VERSION 5.8 ;
BUSBITCHARS "[]" ;
DIVIDERCHAR "/" ;
UNITS
    DATABASE MICRONS 1000 ;
END UNITS

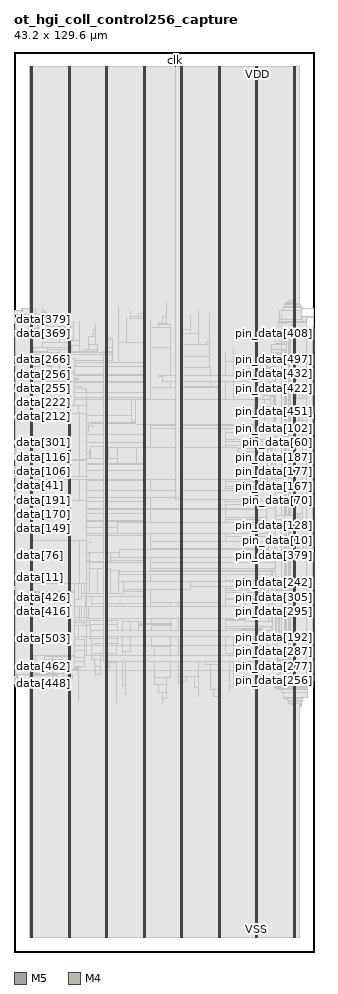
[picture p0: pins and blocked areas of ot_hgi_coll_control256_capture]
MACRO ot_hgi_coll_control256_capture
  FOREIGN ot_hgi_coll_control256_capture 0 0 ;
  CLASS BLOCK ;
  SIZE 43.2 BY 129.6 ;
  PIN clk
    DIRECTION INPUT ;
    USE SIGNAL ;
    PORT
      LAYER M5 ;
        RECT  23.184 129.516 23.208 129.6 ;
    END
    PORT
      LAYER M5 ;
        RECT  23.184 127.463 23.208 129.552 ;
    END
  END clk
  PIN data[0]
    DIRECTION INPUT ;
    USE SIGNAL ;
    PORT
      LAYER M4 ;
        RECT  0 52.848 0.084 52.872 ;
    END
  END data[0]
  PIN data[100]
    DIRECTION INPUT ;
    USE SIGNAL ;
    PORT
      LAYER M4 ;
        RECT  0 68.592 0.084 68.616 ;
    END
  END data[100]
  PIN data[101]
    DIRECTION INPUT ;
    USE SIGNAL ;
    PORT
      LAYER M4 ;
        RECT  0 68.688 0.084 68.712 ;
    END
  END data[101]
  PIN data[102]
    DIRECTION INPUT ;
    USE SIGNAL ;
    PORT
      LAYER M4 ;
        RECT  0 68.784 0.084 68.808 ;
    END
  END data[102]
  PIN data[103]
    DIRECTION INPUT ;
    USE SIGNAL ;
    PORT
      LAYER M4 ;
        RECT  0 68.88 0.084 68.904 ;
    END
  END data[103]
  PIN data[104]
    DIRECTION INPUT ;
    USE SIGNAL ;
    PORT
      LAYER M4 ;
        RECT  0 68.976 0.084 69 ;
    END
  END data[104]
  PIN data[105]
    DIRECTION INPUT ;
    USE SIGNAL ;
    PORT
      LAYER M4 ;
        RECT  0 69.072 0.084 69.096 ;
    END
  END data[105]
  PIN data[106]
    DIRECTION INPUT ;
    USE SIGNAL ;
    PORT
      LAYER M4 ;
        RECT  0 69.168 0.084 69.192 ;
    END
  END data[106]
  PIN data[107]
    DIRECTION INPUT ;
    USE SIGNAL ;
    PORT
      LAYER M4 ;
        RECT  0 69.264 0.084 69.288 ;
    END
  END data[107]
  PIN data[108]
    DIRECTION INPUT ;
    USE SIGNAL ;
    PORT
      LAYER M4 ;
        RECT  0 69.36 0.084 69.384 ;
    END
  END data[108]
  PIN data[109]
    DIRECTION INPUT ;
    USE SIGNAL ;
    PORT
      LAYER M4 ;
        RECT  0 69.456 0.084 69.48 ;
    END
  END data[109]
  PIN data[10]
    DIRECTION INPUT ;
    USE SIGNAL ;
    PORT
      LAYER M4 ;
        RECT  0 53.808 0.084 53.832 ;
    END
  END data[10]
  PIN data[110]
    DIRECTION INPUT ;
    USE SIGNAL ;
    PORT
      LAYER M4 ;
        RECT  0 69.552 0.084 69.576 ;
    END
  END data[110]
  PIN data[111]
    DIRECTION INPUT ;
    USE SIGNAL ;
    PORT
      LAYER M4 ;
        RECT  0 69.648 0.084 69.672 ;
    END
  END data[111]
  PIN data[112]
    DIRECTION INPUT ;
    USE SIGNAL ;
    PORT
      LAYER M4 ;
        RECT  0 69.744 0.084 69.768 ;
    END
  END data[112]
  PIN data[113]
    DIRECTION INPUT ;
    USE SIGNAL ;
    PORT
      LAYER M4 ;
        RECT  0 69.84 0.084 69.864 ;
    END
  END data[113]
  PIN data[114]
    DIRECTION INPUT ;
    USE SIGNAL ;
    PORT
      LAYER M4 ;
        RECT  0 69.936 0.084 69.96 ;
    END
  END data[114]
  PIN data[115]
    DIRECTION INPUT ;
    USE SIGNAL ;
    PORT
      LAYER M4 ;
        RECT  0 70.032 0.084 70.056 ;
    END
  END data[115]
  PIN data[116]
    DIRECTION INPUT ;
    USE SIGNAL ;
    PORT
      LAYER M4 ;
        RECT  0 70.128 0.084 70.152 ;
    END
  END data[116]
  PIN data[117]
    DIRECTION INPUT ;
    USE SIGNAL ;
    PORT
      LAYER M4 ;
        RECT  0 70.224 0.084 70.248 ;
    END
  END data[117]
  PIN data[118]
    DIRECTION INPUT ;
    USE SIGNAL ;
    PORT
      LAYER M4 ;
        RECT  0 70.32 0.084 70.344 ;
    END
  END data[118]
  PIN data[119]
    DIRECTION INPUT ;
    USE SIGNAL ;
    PORT
      LAYER M4 ;
        RECT  0 70.416 0.084 70.44 ;
    END
  END data[119]
  PIN data[11]
    DIRECTION INPUT ;
    USE SIGNAL ;
    PORT
      LAYER M4 ;
        RECT  0 53.904 0.084 53.928 ;
    END
  END data[11]
  PIN data[120]
    DIRECTION INPUT ;
    USE SIGNAL ;
    PORT
      LAYER M4 ;
        RECT  0 70.512 0.084 70.536 ;
    END
  END data[120]
  PIN data[121]
    DIRECTION INPUT ;
    USE SIGNAL ;
    PORT
      LAYER M4 ;
        RECT  0 70.608 0.084 70.632 ;
    END
  END data[121]
  PIN data[122]
    DIRECTION INPUT ;
    USE SIGNAL ;
    PORT
      LAYER M4 ;
        RECT  0 70.704 0.084 70.728 ;
    END
  END data[122]
  PIN data[123]
    DIRECTION INPUT ;
    USE SIGNAL ;
    PORT
      LAYER M4 ;
        RECT  0 70.8 0.084 70.824 ;
    END
  END data[123]
  PIN data[124]
    DIRECTION INPUT ;
    USE SIGNAL ;
    PORT
      LAYER M4 ;
        RECT  0 70.896 0.084 70.92 ;
    END
  END data[124]
  PIN data[125]
    DIRECTION INPUT ;
    USE SIGNAL ;
    PORT
      LAYER M4 ;
        RECT  0 70.992 0.084 71.016 ;
    END
  END data[125]
  PIN data[126]
    DIRECTION INPUT ;
    USE SIGNAL ;
    PORT
      LAYER M4 ;
        RECT  0 71.088 0.084 71.112 ;
    END
  END data[126]
  PIN data[127]
    DIRECTION INPUT ;
    USE SIGNAL ;
    PORT
      LAYER M4 ;
        RECT  0 71.184 0.084 71.208 ;
    END
  END data[127]
  PIN data[128]
    DIRECTION INPUT ;
    USE SIGNAL ;
    PORT
      LAYER M4 ;
        RECT  0 58.992 0.084 59.016 ;
    END
  END data[128]
  PIN data[129]
    DIRECTION INPUT ;
    USE SIGNAL ;
    PORT
      LAYER M4 ;
        RECT  0 59.088 0.084 59.112 ;
    END
  END data[129]
  PIN data[12]
    DIRECTION INPUT ;
    USE SIGNAL ;
    PORT
      LAYER M4 ;
        RECT  0 54 0.084 54.024 ;
    END
  END data[12]
  PIN data[130]
    DIRECTION INPUT ;
    USE SIGNAL ;
    PORT
      LAYER M4 ;
        RECT  0 59.184 0.084 59.208 ;
    END
  END data[130]
  PIN data[131]
    DIRECTION INPUT ;
    USE SIGNAL ;
    PORT
      LAYER M4 ;
        RECT  0 59.28 0.084 59.304 ;
    END
  END data[131]
  PIN data[132]
    DIRECTION INPUT ;
    USE SIGNAL ;
    PORT
      LAYER M4 ;
        RECT  0 59.376 0.084 59.4 ;
    END
  END data[132]
  PIN data[133]
    DIRECTION INPUT ;
    USE SIGNAL ;
    PORT
      LAYER M4 ;
        RECT  0 59.472 0.084 59.496 ;
    END
  END data[133]
  PIN data[134]
    DIRECTION INPUT ;
    USE SIGNAL ;
    PORT
      LAYER M4 ;
        RECT  0 59.568 0.084 59.592 ;
    END
  END data[134]
  PIN data[135]
    DIRECTION INPUT ;
    USE SIGNAL ;
    PORT
      LAYER M4 ;
        RECT  0 59.664 0.084 59.688 ;
    END
  END data[135]
  PIN data[136]
    DIRECTION INPUT ;
    USE SIGNAL ;
    PORT
      LAYER M4 ;
        RECT  0 59.76 0.084 59.784 ;
    END
  END data[136]
  PIN data[137]
    DIRECTION INPUT ;
    USE SIGNAL ;
    PORT
      LAYER M4 ;
        RECT  0 59.856 0.084 59.88 ;
    END
  END data[137]
  PIN data[138]
    DIRECTION INPUT ;
    USE SIGNAL ;
    PORT
      LAYER M4 ;
        RECT  0 59.952 0.084 59.976 ;
    END
  END data[138]
  PIN data[139]
    DIRECTION INPUT ;
    USE SIGNAL ;
    PORT
      LAYER M4 ;
        RECT  0 60.048 0.084 60.072 ;
    END
  END data[139]
  PIN data[13]
    DIRECTION INPUT ;
    USE SIGNAL ;
    PORT
      LAYER M4 ;
        RECT  0 54.096 0.084 54.12 ;
    END
  END data[13]
  PIN data[140]
    DIRECTION INPUT ;
    USE SIGNAL ;
    PORT
      LAYER M4 ;
        RECT  0 60.144 0.084 60.168 ;
    END
  END data[140]
  PIN data[141]
    DIRECTION INPUT ;
    USE SIGNAL ;
    PORT
      LAYER M4 ;
        RECT  0 60.24 0.084 60.264 ;
    END
  END data[141]
  PIN data[142]
    DIRECTION INPUT ;
    USE SIGNAL ;
    PORT
      LAYER M4 ;
        RECT  0 60.336 0.084 60.36 ;
    END
  END data[142]
  PIN data[143]
    DIRECTION INPUT ;
    USE SIGNAL ;
    PORT
      LAYER M4 ;
        RECT  0 60.432 0.084 60.456 ;
    END
  END data[143]
  PIN data[144]
    DIRECTION INPUT ;
    USE SIGNAL ;
    PORT
      LAYER M4 ;
        RECT  0 60.528 0.084 60.552 ;
    END
  END data[144]
  PIN data[145]
    DIRECTION INPUT ;
    USE SIGNAL ;
    PORT
      LAYER M4 ;
        RECT  0 60.624 0.084 60.648 ;
    END
  END data[145]
  PIN data[146]
    DIRECTION INPUT ;
    USE SIGNAL ;
    PORT
      LAYER M4 ;
        RECT  0 60.72 0.084 60.744 ;
    END
  END data[146]
  PIN data[147]
    DIRECTION INPUT ;
    USE SIGNAL ;
    PORT
      LAYER M4 ;
        RECT  0 60.816 0.084 60.84 ;
    END
  END data[147]
  PIN data[148]
    DIRECTION INPUT ;
    USE SIGNAL ;
    PORT
      LAYER M4 ;
        RECT  0 60.912 0.084 60.936 ;
    END
  END data[148]
  PIN data[149]
    DIRECTION INPUT ;
    USE SIGNAL ;
    PORT
      LAYER M4 ;
        RECT  0 61.008 0.084 61.032 ;
    END
  END data[149]
  PIN data[14]
    DIRECTION INPUT ;
    USE SIGNAL ;
    PORT
      LAYER M4 ;
        RECT  0 54.192 0.084 54.216 ;
    END
  END data[14]
  PIN data[150]
    DIRECTION INPUT ;
    USE SIGNAL ;
    PORT
      LAYER M4 ;
        RECT  0 61.104 0.084 61.128 ;
    END
  END data[150]
  PIN data[151]
    DIRECTION INPUT ;
    USE SIGNAL ;
    PORT
      LAYER M4 ;
        RECT  0 61.2 0.084 61.224 ;
    END
  END data[151]
  PIN data[152]
    DIRECTION INPUT ;
    USE SIGNAL ;
    PORT
      LAYER M4 ;
        RECT  0 61.296 0.084 61.32 ;
    END
  END data[152]
  PIN data[153]
    DIRECTION INPUT ;
    USE SIGNAL ;
    PORT
      LAYER M4 ;
        RECT  0 61.392 0.084 61.416 ;
    END
  END data[153]
  PIN data[154]
    DIRECTION INPUT ;
    USE SIGNAL ;
    PORT
      LAYER M4 ;
        RECT  0 61.488 0.084 61.512 ;
    END
  END data[154]
  PIN data[155]
    DIRECTION INPUT ;
    USE SIGNAL ;
    PORT
      LAYER M4 ;
        RECT  0 61.584 0.084 61.608 ;
    END
  END data[155]
  PIN data[156]
    DIRECTION INPUT ;
    USE SIGNAL ;
    PORT
      LAYER M4 ;
        RECT  0 61.68 0.084 61.704 ;
    END
  END data[156]
  PIN data[157]
    DIRECTION INPUT ;
    USE SIGNAL ;
    PORT
      LAYER M4 ;
        RECT  0 61.776 0.084 61.8 ;
    END
  END data[157]
  PIN data[158]
    DIRECTION INPUT ;
    USE SIGNAL ;
    PORT
      LAYER M4 ;
        RECT  0 61.872 0.084 61.896 ;
    END
  END data[158]
  PIN data[159]
    DIRECTION INPUT ;
    USE SIGNAL ;
    PORT
      LAYER M4 ;
        RECT  0 61.968 0.084 61.992 ;
    END
  END data[159]
  PIN data[15]
    DIRECTION INPUT ;
    USE SIGNAL ;
    PORT
      LAYER M4 ;
        RECT  0 54.288 0.084 54.312 ;
    END
  END data[15]
  PIN data[160]
    DIRECTION INPUT ;
    USE SIGNAL ;
    PORT
      LAYER M4 ;
        RECT  0 62.064 0.084 62.088 ;
    END
  END data[160]
  PIN data[161]
    DIRECTION INPUT ;
    USE SIGNAL ;
    PORT
      LAYER M4 ;
        RECT  0 62.16 0.084 62.184 ;
    END
  END data[161]
  PIN data[162]
    DIRECTION INPUT ;
    USE SIGNAL ;
    PORT
      LAYER M4 ;
        RECT  0 62.256 0.084 62.28 ;
    END
  END data[162]
  PIN data[163]
    DIRECTION INPUT ;
    USE SIGNAL ;
    PORT
      LAYER M4 ;
        RECT  0 62.352 0.084 62.376 ;
    END
  END data[163]
  PIN data[164]
    DIRECTION INPUT ;
    USE SIGNAL ;
    PORT
      LAYER M4 ;
        RECT  0 62.448 0.084 62.472 ;
    END
  END data[164]
  PIN data[165]
    DIRECTION INPUT ;
    USE SIGNAL ;
    PORT
      LAYER M4 ;
        RECT  0 62.544 0.084 62.568 ;
    END
  END data[165]
  PIN data[166]
    DIRECTION INPUT ;
    USE SIGNAL ;
    PORT
      LAYER M4 ;
        RECT  0 62.64 0.084 62.664 ;
    END
  END data[166]
  PIN data[167]
    DIRECTION INPUT ;
    USE SIGNAL ;
    PORT
      LAYER M4 ;
        RECT  0 62.736 0.084 62.76 ;
    END
  END data[167]
  PIN data[168]
    DIRECTION INPUT ;
    USE SIGNAL ;
    PORT
      LAYER M4 ;
        RECT  0 62.832 0.084 62.856 ;
    END
  END data[168]
  PIN data[169]
    DIRECTION INPUT ;
    USE SIGNAL ;
    PORT
      LAYER M4 ;
        RECT  0 62.928 0.084 62.952 ;
    END
  END data[169]
  PIN data[16]
    DIRECTION INPUT ;
    USE SIGNAL ;
    PORT
      LAYER M4 ;
        RECT  0 54.384 0.084 54.408 ;
    END
  END data[16]
  PIN data[170]
    DIRECTION INPUT ;
    USE SIGNAL ;
    PORT
      LAYER M4 ;
        RECT  0 63.024 0.084 63.048 ;
    END
  END data[170]
  PIN data[171]
    DIRECTION INPUT ;
    USE SIGNAL ;
    PORT
      LAYER M4 ;
        RECT  0 63.12 0.084 63.144 ;
    END
  END data[171]
  PIN data[172]
    DIRECTION INPUT ;
    USE SIGNAL ;
    PORT
      LAYER M4 ;
        RECT  0 63.216 0.084 63.24 ;
    END
  END data[172]
  PIN data[173]
    DIRECTION INPUT ;
    USE SIGNAL ;
    PORT
      LAYER M4 ;
        RECT  0 63.312 0.084 63.336 ;
    END
  END data[173]
  PIN data[174]
    DIRECTION INPUT ;
    USE SIGNAL ;
    PORT
      LAYER M4 ;
        RECT  0 63.408 0.084 63.432 ;
    END
  END data[174]
  PIN data[175]
    DIRECTION INPUT ;
    USE SIGNAL ;
    PORT
      LAYER M4 ;
        RECT  0 63.504 0.084 63.528 ;
    END
  END data[175]
  PIN data[176]
    DIRECTION INPUT ;
    USE SIGNAL ;
    PORT
      LAYER M4 ;
        RECT  0 63.6 0.084 63.624 ;
    END
  END data[176]
  PIN data[177]
    DIRECTION INPUT ;
    USE SIGNAL ;
    PORT
      LAYER M4 ;
        RECT  0 63.696 0.084 63.72 ;
    END
  END data[177]
  PIN data[178]
    DIRECTION INPUT ;
    USE SIGNAL ;
    PORT
      LAYER M4 ;
        RECT  0 63.792 0.084 63.816 ;
    END
  END data[178]
  PIN data[179]
    DIRECTION INPUT ;
    USE SIGNAL ;
    PORT
      LAYER M4 ;
        RECT  0 63.888 0.084 63.912 ;
    END
  END data[179]
  PIN data[17]
    DIRECTION INPUT ;
    USE SIGNAL ;
    PORT
      LAYER M4 ;
        RECT  0 54.48 0.084 54.504 ;
    END
  END data[17]
  PIN data[180]
    DIRECTION INPUT ;
    USE SIGNAL ;
    PORT
      LAYER M4 ;
        RECT  0 63.984 0.084 64.008 ;
    END
  END data[180]
  PIN data[181]
    DIRECTION INPUT ;
    USE SIGNAL ;
    PORT
      LAYER M4 ;
        RECT  0 64.08 0.084 64.104 ;
    END
  END data[181]
  PIN data[182]
    DIRECTION INPUT ;
    USE SIGNAL ;
    PORT
      LAYER M4 ;
        RECT  0 64.176 0.084 64.2 ;
    END
  END data[182]
  PIN data[183]
    DIRECTION INPUT ;
    USE SIGNAL ;
    PORT
      LAYER M4 ;
        RECT  0 64.272 0.084 64.296 ;
    END
  END data[183]
  PIN data[184]
    DIRECTION INPUT ;
    USE SIGNAL ;
    PORT
      LAYER M4 ;
        RECT  0 64.368 0.084 64.392 ;
    END
  END data[184]
  PIN data[185]
    DIRECTION INPUT ;
    USE SIGNAL ;
    PORT
      LAYER M4 ;
        RECT  0 64.464 0.084 64.488 ;
    END
  END data[185]
  PIN data[186]
    DIRECTION INPUT ;
    USE SIGNAL ;
    PORT
      LAYER M4 ;
        RECT  0 64.56 0.084 64.584 ;
    END
  END data[186]
  PIN data[187]
    DIRECTION INPUT ;
    USE SIGNAL ;
    PORT
      LAYER M4 ;
        RECT  0 64.656 0.084 64.68 ;
    END
  END data[187]
  PIN data[188]
    DIRECTION INPUT ;
    USE SIGNAL ;
    PORT
      LAYER M4 ;
        RECT  0 64.752 0.084 64.776 ;
    END
  END data[188]
  PIN data[189]
    DIRECTION INPUT ;
    USE SIGNAL ;
    PORT
      LAYER M4 ;
        RECT  0 64.848 0.084 64.872 ;
    END
  END data[189]
  PIN data[18]
    DIRECTION INPUT ;
    USE SIGNAL ;
    PORT
      LAYER M4 ;
        RECT  0 54.576 0.084 54.6 ;
    END
  END data[18]
  PIN data[190]
    DIRECTION INPUT ;
    USE SIGNAL ;
    PORT
      LAYER M4 ;
        RECT  0 64.944 0.084 64.968 ;
    END
  END data[190]
  PIN data[191]
    DIRECTION INPUT ;
    USE SIGNAL ;
    PORT
      LAYER M4 ;
        RECT  0 65.04 0.084 65.064 ;
    END
  END data[191]
  PIN data[192]
    DIRECTION INPUT ;
    USE SIGNAL ;
    PORT
      LAYER M4 ;
        RECT  0 75.12 0.084 75.144 ;
    END
  END data[192]
  PIN data[193]
    DIRECTION INPUT ;
    USE SIGNAL ;
    PORT
      LAYER M4 ;
        RECT  0 75.216 0.084 75.24 ;
    END
  END data[193]
  PIN data[194]
    DIRECTION INPUT ;
    USE SIGNAL ;
    PORT
      LAYER M4 ;
        RECT  0 75.312 0.084 75.336 ;
    END
  END data[194]
  PIN data[195]
    DIRECTION INPUT ;
    USE SIGNAL ;
    PORT
      LAYER M4 ;
        RECT  0 75.408 0.084 75.432 ;
    END
  END data[195]
  PIN data[196]
    DIRECTION INPUT ;
    USE SIGNAL ;
    PORT
      LAYER M4 ;
        RECT  0 75.504 0.084 75.528 ;
    END
  END data[196]
  PIN data[197]
    DIRECTION INPUT ;
    USE SIGNAL ;
    PORT
      LAYER M4 ;
        RECT  0 75.6 0.084 75.624 ;
    END
  END data[197]
  PIN data[198]
    DIRECTION INPUT ;
    USE SIGNAL ;
    PORT
      LAYER M4 ;
        RECT  0 75.696 0.084 75.72 ;
    END
  END data[198]
  PIN data[199]
    DIRECTION INPUT ;
    USE SIGNAL ;
    PORT
      LAYER M4 ;
        RECT  0 75.792 0.084 75.816 ;
    END
  END data[199]
  PIN data[19]
    DIRECTION INPUT ;
    USE SIGNAL ;
    PORT
      LAYER M4 ;
        RECT  0 54.672 0.084 54.696 ;
    END
  END data[19]
  PIN data[1]
    DIRECTION INPUT ;
    USE SIGNAL ;
    PORT
      LAYER M4 ;
        RECT  0 52.944 0.084 52.968 ;
    END
  END data[1]
  PIN data[200]
    DIRECTION INPUT ;
    USE SIGNAL ;
    PORT
      LAYER M4 ;
        RECT  0 75.888 0.084 75.912 ;
    END
  END data[200]
  PIN data[201]
    DIRECTION INPUT ;
    USE SIGNAL ;
    PORT
      LAYER M4 ;
        RECT  0 75.984 0.084 76.008 ;
    END
  END data[201]
  PIN data[202]
    DIRECTION INPUT ;
    USE SIGNAL ;
    PORT
      LAYER M4 ;
        RECT  0 76.08 0.084 76.104 ;
    END
  END data[202]
  PIN data[203]
    DIRECTION INPUT ;
    USE SIGNAL ;
    PORT
      LAYER M4 ;
        RECT  0 76.176 0.084 76.2 ;
    END
  END data[203]
  PIN data[204]
    DIRECTION INPUT ;
    USE SIGNAL ;
    PORT
      LAYER M4 ;
        RECT  0 76.272 0.084 76.296 ;
    END
  END data[204]
  PIN data[205]
    DIRECTION INPUT ;
    USE SIGNAL ;
    PORT
      LAYER M4 ;
        RECT  0 76.368 0.084 76.392 ;
    END
  END data[205]
  PIN data[206]
    DIRECTION INPUT ;
    USE SIGNAL ;
    PORT
      LAYER M4 ;
        RECT  0 76.464 0.084 76.488 ;
    END
  END data[206]
  PIN data[207]
    DIRECTION INPUT ;
    USE SIGNAL ;
    PORT
      LAYER M4 ;
        RECT  0 76.56 0.084 76.584 ;
    END
  END data[207]
  PIN data[208]
    DIRECTION INPUT ;
    USE SIGNAL ;
    PORT
      LAYER M4 ;
        RECT  0 76.656 0.084 76.68 ;
    END
  END data[208]
  PIN data[209]
    DIRECTION INPUT ;
    USE SIGNAL ;
    PORT
      LAYER M4 ;
        RECT  0 76.752 0.084 76.776 ;
    END
  END data[209]
  PIN data[20]
    DIRECTION INPUT ;
    USE SIGNAL ;
    PORT
      LAYER M4 ;
        RECT  0 54.768 0.084 54.792 ;
    END
  END data[20]
  PIN data[210]
    DIRECTION INPUT ;
    USE SIGNAL ;
    PORT
      LAYER M4 ;
        RECT  0 76.848 0.084 76.872 ;
    END
  END data[210]
  PIN data[211]
    DIRECTION INPUT ;
    USE SIGNAL ;
    PORT
      LAYER M4 ;
        RECT  0 76.944 0.084 76.968 ;
    END
  END data[211]
  PIN data[212]
    DIRECTION INPUT ;
    USE SIGNAL ;
    PORT
      LAYER M4 ;
        RECT  0 77.04 0.084 77.064 ;
    END
  END data[212]
  PIN data[213]
    DIRECTION INPUT ;
    USE SIGNAL ;
    PORT
      LAYER M4 ;
        RECT  0 77.136 0.084 77.16 ;
    END
  END data[213]
  PIN data[214]
    DIRECTION INPUT ;
    USE SIGNAL ;
    PORT
      LAYER M4 ;
        RECT  0 77.232 0.084 77.256 ;
    END
  END data[214]
  PIN data[215]
    DIRECTION INPUT ;
    USE SIGNAL ;
    PORT
      LAYER M4 ;
        RECT  0 77.328 0.084 77.352 ;
    END
  END data[215]
  PIN data[216]
    DIRECTION INPUT ;
    USE SIGNAL ;
    PORT
      LAYER M4 ;
        RECT  0 77.424 0.084 77.448 ;
    END
  END data[216]
  PIN data[217]
    DIRECTION INPUT ;
    USE SIGNAL ;
    PORT
      LAYER M4 ;
        RECT  0 77.52 0.084 77.544 ;
    END
  END data[217]
  PIN data[218]
    DIRECTION INPUT ;
    USE SIGNAL ;
    PORT
      LAYER M4 ;
        RECT  0 77.616 0.084 77.64 ;
    END
  END data[218]
  PIN data[219]
    DIRECTION INPUT ;
    USE SIGNAL ;
    PORT
      LAYER M4 ;
        RECT  0 77.712 0.084 77.736 ;
    END
  END data[219]
  PIN data[21]
    DIRECTION INPUT ;
    USE SIGNAL ;
    PORT
      LAYER M4 ;
        RECT  0 54.864 0.084 54.888 ;
    END
  END data[21]
  PIN data[220]
    DIRECTION INPUT ;
    USE SIGNAL ;
    PORT
      LAYER M4 ;
        RECT  0 77.808 0.084 77.832 ;
    END
  END data[220]
  PIN data[221]
    DIRECTION INPUT ;
    USE SIGNAL ;
    PORT
      LAYER M4 ;
        RECT  0 77.904 0.084 77.928 ;
    END
  END data[221]
  PIN data[222]
    DIRECTION INPUT ;
    USE SIGNAL ;
    PORT
      LAYER M4 ;
        RECT  0 78 0.084 78.024 ;
    END
  END data[222]
  PIN data[223]
    DIRECTION INPUT ;
    USE SIGNAL ;
    PORT
      LAYER M4 ;
        RECT  0 78.096 0.084 78.12 ;
    END
  END data[223]
  PIN data[224]
    DIRECTION INPUT ;
    USE SIGNAL ;
    PORT
      LAYER M4 ;
        RECT  0 78.192 0.084 78.216 ;
    END
  END data[224]
  PIN data[225]
    DIRECTION INPUT ;
    USE SIGNAL ;
    PORT
      LAYER M4 ;
        RECT  0 78.288 0.084 78.312 ;
    END
  END data[225]
  PIN data[226]
    DIRECTION INPUT ;
    USE SIGNAL ;
    PORT
      LAYER M4 ;
        RECT  0 78.384 0.084 78.408 ;
    END
  END data[226]
  PIN data[227]
    DIRECTION INPUT ;
    USE SIGNAL ;
    PORT
      LAYER M4 ;
        RECT  0 78.48 0.084 78.504 ;
    END
  END data[227]
  PIN data[228]
    DIRECTION INPUT ;
    USE SIGNAL ;
    PORT
      LAYER M4 ;
        RECT  0 78.576 0.084 78.6 ;
    END
  END data[228]
  PIN data[229]
    DIRECTION INPUT ;
    USE SIGNAL ;
    PORT
      LAYER M4 ;
        RECT  0 78.672 0.084 78.696 ;
    END
  END data[229]
  PIN data[22]
    DIRECTION INPUT ;
    USE SIGNAL ;
    PORT
      LAYER M4 ;
        RECT  0 54.96 0.084 54.984 ;
    END
  END data[22]
  PIN data[230]
    DIRECTION INPUT ;
    USE SIGNAL ;
    PORT
      LAYER M4 ;
        RECT  0 78.768 0.084 78.792 ;
    END
  END data[230]
  PIN data[231]
    DIRECTION INPUT ;
    USE SIGNAL ;
    PORT
      LAYER M4 ;
        RECT  0 78.864 0.084 78.888 ;
    END
  END data[231]
  PIN data[232]
    DIRECTION INPUT ;
    USE SIGNAL ;
    PORT
      LAYER M4 ;
        RECT  0 78.96 0.084 78.984 ;
    END
  END data[232]
  PIN data[233]
    DIRECTION INPUT ;
    USE SIGNAL ;
    PORT
      LAYER M4 ;
        RECT  0 79.056 0.084 79.08 ;
    END
  END data[233]
  PIN data[234]
    DIRECTION INPUT ;
    USE SIGNAL ;
    PORT
      LAYER M4 ;
        RECT  0 79.152 0.084 79.176 ;
    END
  END data[234]
  PIN data[235]
    DIRECTION INPUT ;
    USE SIGNAL ;
    PORT
      LAYER M4 ;
        RECT  0 79.248 0.084 79.272 ;
    END
  END data[235]
  PIN data[236]
    DIRECTION INPUT ;
    USE SIGNAL ;
    PORT
      LAYER M4 ;
        RECT  0 79.344 0.084 79.368 ;
    END
  END data[236]
  PIN data[237]
    DIRECTION INPUT ;
    USE SIGNAL ;
    PORT
      LAYER M4 ;
        RECT  0 79.44 0.084 79.464 ;
    END
  END data[237]
  PIN data[238]
    DIRECTION INPUT ;
    USE SIGNAL ;
    PORT
      LAYER M4 ;
        RECT  0 79.536 0.084 79.56 ;
    END
  END data[238]
  PIN data[239]
    DIRECTION INPUT ;
    USE SIGNAL ;
    PORT
      LAYER M4 ;
        RECT  0 79.632 0.084 79.656 ;
    END
  END data[239]
  PIN data[23]
    DIRECTION INPUT ;
    USE SIGNAL ;
    PORT
      LAYER M4 ;
        RECT  0 55.056 0.084 55.08 ;
    END
  END data[23]
  PIN data[240]
    DIRECTION INPUT ;
    USE SIGNAL ;
    PORT
      LAYER M4 ;
        RECT  0 79.728 0.084 79.752 ;
    END
  END data[240]
  PIN data[241]
    DIRECTION INPUT ;
    USE SIGNAL ;
    PORT
      LAYER M4 ;
        RECT  0 79.824 0.084 79.848 ;
    END
  END data[241]
  PIN data[242]
    DIRECTION INPUT ;
    USE SIGNAL ;
    PORT
      LAYER M4 ;
        RECT  0 79.92 0.084 79.944 ;
    END
  END data[242]
  PIN data[243]
    DIRECTION INPUT ;
    USE SIGNAL ;
    PORT
      LAYER M4 ;
        RECT  0 80.016 0.084 80.04 ;
    END
  END data[243]
  PIN data[244]
    DIRECTION INPUT ;
    USE SIGNAL ;
    PORT
      LAYER M4 ;
        RECT  0 80.112 0.084 80.136 ;
    END
  END data[244]
  PIN data[245]
    DIRECTION INPUT ;
    USE SIGNAL ;
    PORT
      LAYER M4 ;
        RECT  0 80.208 0.084 80.232 ;
    END
  END data[245]
  PIN data[246]
    DIRECTION INPUT ;
    USE SIGNAL ;
    PORT
      LAYER M4 ;
        RECT  0 80.304 0.084 80.328 ;
    END
  END data[246]
  PIN data[247]
    DIRECTION INPUT ;
    USE SIGNAL ;
    PORT
      LAYER M4 ;
        RECT  0 80.4 0.084 80.424 ;
    END
  END data[247]
  PIN data[248]
    DIRECTION INPUT ;
    USE SIGNAL ;
    PORT
      LAYER M4 ;
        RECT  0 80.496 0.084 80.52 ;
    END
  END data[248]
  PIN data[249]
    DIRECTION INPUT ;
    USE SIGNAL ;
    PORT
      LAYER M4 ;
        RECT  0 80.592 0.084 80.616 ;
    END
  END data[249]
  PIN data[24]
    DIRECTION INPUT ;
    USE SIGNAL ;
    PORT
      LAYER M4 ;
        RECT  0 55.152 0.084 55.176 ;
    END
  END data[24]
  PIN data[250]
    DIRECTION INPUT ;
    USE SIGNAL ;
    PORT
      LAYER M4 ;
        RECT  0 80.688 0.084 80.712 ;
    END
  END data[250]
  PIN data[251]
    DIRECTION INPUT ;
    USE SIGNAL ;
    PORT
      LAYER M4 ;
        RECT  0 80.784 0.084 80.808 ;
    END
  END data[251]
  PIN data[252]
    DIRECTION INPUT ;
    USE SIGNAL ;
    PORT
      LAYER M4 ;
        RECT  0 80.88 0.084 80.904 ;
    END
  END data[252]
  PIN data[253]
    DIRECTION INPUT ;
    USE SIGNAL ;
    PORT
      LAYER M4 ;
        RECT  0 80.976 0.084 81 ;
    END
  END data[253]
  PIN data[254]
    DIRECTION INPUT ;
    USE SIGNAL ;
    PORT
      LAYER M4 ;
        RECT  0 81.072 0.084 81.096 ;
    END
  END data[254]
  PIN data[255]
    DIRECTION INPUT ;
    USE SIGNAL ;
    PORT
      LAYER M4 ;
        RECT  0 81.168 0.084 81.192 ;
    END
  END data[255]
  PIN data[256]
    DIRECTION INPUT ;
    USE SIGNAL ;
    PORT
      LAYER M4 ;
        RECT  0 84.336 0.084 84.36 ;
    END
  END data[256]
  PIN data[257]
    DIRECTION INPUT ;
    USE SIGNAL ;
    PORT
      LAYER M4 ;
        RECT  0 84.432 0.084 84.456 ;
    END
  END data[257]
  PIN data[258]
    DIRECTION INPUT ;
    USE SIGNAL ;
    PORT
      LAYER M4 ;
        RECT  0 84.528 0.084 84.552 ;
    END
  END data[258]
  PIN data[259]
    DIRECTION INPUT ;
    USE SIGNAL ;
    PORT
      LAYER M4 ;
        RECT  0 84.624 0.084 84.648 ;
    END
  END data[259]
  PIN data[25]
    DIRECTION INPUT ;
    USE SIGNAL ;
    PORT
      LAYER M4 ;
        RECT  0 55.248 0.084 55.272 ;
    END
  END data[25]
  PIN data[260]
    DIRECTION INPUT ;
    USE SIGNAL ;
    PORT
      LAYER M4 ;
        RECT  0 84.72 0.084 84.744 ;
    END
  END data[260]
  PIN data[261]
    DIRECTION INPUT ;
    USE SIGNAL ;
    PORT
      LAYER M4 ;
        RECT  0 84.816 0.084 84.84 ;
    END
  END data[261]
  PIN data[262]
    DIRECTION INPUT ;
    USE SIGNAL ;
    PORT
      LAYER M4 ;
        RECT  0 84.912 0.084 84.936 ;
    END
  END data[262]
  PIN data[263]
    DIRECTION INPUT ;
    USE SIGNAL ;
    PORT
      LAYER M4 ;
        RECT  0 85.008 0.084 85.032 ;
    END
  END data[263]
  PIN data[264]
    DIRECTION INPUT ;
    USE SIGNAL ;
    PORT
      LAYER M4 ;
        RECT  0 85.104 0.084 85.128 ;
    END
  END data[264]
  PIN data[265]
    DIRECTION INPUT ;
    USE SIGNAL ;
    PORT
      LAYER M4 ;
        RECT  0 85.2 0.084 85.224 ;
    END
  END data[265]
  PIN data[266]
    DIRECTION INPUT ;
    USE SIGNAL ;
    PORT
      LAYER M4 ;
        RECT  0 85.296 0.084 85.32 ;
    END
  END data[266]
  PIN data[267]
    DIRECTION INPUT ;
    USE SIGNAL ;
    PORT
      LAYER M4 ;
        RECT  0 85.392 0.084 85.416 ;
    END
  END data[267]
  PIN data[268]
    DIRECTION INPUT ;
    USE SIGNAL ;
    PORT
      LAYER M4 ;
        RECT  0 85.488 0.084 85.512 ;
    END
  END data[268]
  PIN data[269]
    DIRECTION INPUT ;
    USE SIGNAL ;
    PORT
      LAYER M4 ;
        RECT  0 85.584 0.084 85.608 ;
    END
  END data[269]
  PIN data[26]
    DIRECTION INPUT ;
    USE SIGNAL ;
    PORT
      LAYER M4 ;
        RECT  0 55.344 0.084 55.368 ;
    END
  END data[26]
  PIN data[270]
    DIRECTION INPUT ;
    USE SIGNAL ;
    PORT
      LAYER M4 ;
        RECT  0 85.68 0.084 85.704 ;
    END
  END data[270]
  PIN data[271]
    DIRECTION INPUT ;
    USE SIGNAL ;
    PORT
      LAYER M4 ;
        RECT  0 85.776 0.084 85.8 ;
    END
  END data[271]
  PIN data[272]
    DIRECTION INPUT ;
    USE SIGNAL ;
    PORT
      LAYER M4 ;
        RECT  0 85.872 0.084 85.896 ;
    END
  END data[272]
  PIN data[273]
    DIRECTION INPUT ;
    USE SIGNAL ;
    PORT
      LAYER M4 ;
        RECT  0 85.968 0.084 85.992 ;
    END
  END data[273]
  PIN data[274]
    DIRECTION INPUT ;
    USE SIGNAL ;
    PORT
      LAYER M4 ;
        RECT  0 86.064 0.084 86.088 ;
    END
  END data[274]
  PIN data[275]
    DIRECTION INPUT ;
    USE SIGNAL ;
    PORT
      LAYER M4 ;
        RECT  0 86.16 0.084 86.184 ;
    END
  END data[275]
  PIN data[276]
    DIRECTION INPUT ;
    USE SIGNAL ;
    PORT
      LAYER M4 ;
        RECT  0 86.256 0.084 86.28 ;
    END
  END data[276]
  PIN data[277]
    DIRECTION INPUT ;
    USE SIGNAL ;
    PORT
      LAYER M4 ;
        RECT  0 86.352 0.084 86.376 ;
    END
  END data[277]
  PIN data[278]
    DIRECTION INPUT ;
    USE SIGNAL ;
    PORT
      LAYER M4 ;
        RECT  0 86.448 0.084 86.472 ;
    END
  END data[278]
  PIN data[279]
    DIRECTION INPUT ;
    USE SIGNAL ;
    PORT
      LAYER M4 ;
        RECT  0 86.544 0.084 86.568 ;
    END
  END data[279]
  PIN data[27]
    DIRECTION INPUT ;
    USE SIGNAL ;
    PORT
      LAYER M4 ;
        RECT  0 55.44 0.084 55.464 ;
    END
  END data[27]
  PIN data[280]
    DIRECTION INPUT ;
    USE SIGNAL ;
    PORT
      LAYER M4 ;
        RECT  0 86.64 0.084 86.664 ;
    END
  END data[280]
  PIN data[281]
    DIRECTION INPUT ;
    USE SIGNAL ;
    PORT
      LAYER M4 ;
        RECT  0 86.736 0.084 86.76 ;
    END
  END data[281]
  PIN data[282]
    DIRECTION INPUT ;
    USE SIGNAL ;
    PORT
      LAYER M4 ;
        RECT  0 86.832 0.084 86.856 ;
    END
  END data[282]
  PIN data[283]
    DIRECTION INPUT ;
    USE SIGNAL ;
    PORT
      LAYER M4 ;
        RECT  0 86.928 0.084 86.952 ;
    END
  END data[283]
  PIN data[284]
    DIRECTION INPUT ;
    USE SIGNAL ;
    PORT
      LAYER M4 ;
        RECT  0 87.024 0.084 87.048 ;
    END
  END data[284]
  PIN data[285]
    DIRECTION INPUT ;
    USE SIGNAL ;
    PORT
      LAYER M4 ;
        RECT  0 87.12 0.084 87.144 ;
    END
  END data[285]
  PIN data[286]
    DIRECTION INPUT ;
    USE SIGNAL ;
    PORT
      LAYER M4 ;
        RECT  0 87.216 0.084 87.24 ;
    END
  END data[286]
  PIN data[287]
    DIRECTION INPUT ;
    USE SIGNAL ;
    PORT
      LAYER M4 ;
        RECT  0 87.312 0.084 87.336 ;
    END
  END data[287]
  PIN data[288]
    DIRECTION INPUT ;
    USE SIGNAL ;
    PORT
      LAYER M4 ;
        RECT  0 72.048 0.084 72.072 ;
    END
  END data[288]
  PIN data[289]
    DIRECTION INPUT ;
    USE SIGNAL ;
    PORT
      LAYER M4 ;
        RECT  0 72.144 0.084 72.168 ;
    END
  END data[289]
  PIN data[28]
    DIRECTION INPUT ;
    USE SIGNAL ;
    PORT
      LAYER M4 ;
        RECT  0 55.536 0.084 55.56 ;
    END
  END data[28]
  PIN data[290]
    DIRECTION INPUT ;
    USE SIGNAL ;
    PORT
      LAYER M4 ;
        RECT  0 72.24 0.084 72.264 ;
    END
  END data[290]
  PIN data[291]
    DIRECTION INPUT ;
    USE SIGNAL ;
    PORT
      LAYER M4 ;
        RECT  0 72.336 0.084 72.36 ;
    END
  END data[291]
  PIN data[292]
    DIRECTION INPUT ;
    USE SIGNAL ;
    PORT
      LAYER M4 ;
        RECT  0 72.432 0.084 72.456 ;
    END
  END data[292]
  PIN data[293]
    DIRECTION INPUT ;
    USE SIGNAL ;
    PORT
      LAYER M4 ;
        RECT  0 72.528 0.084 72.552 ;
    END
  END data[293]
  PIN data[294]
    DIRECTION INPUT ;
    USE SIGNAL ;
    PORT
      LAYER M4 ;
        RECT  0 72.624 0.084 72.648 ;
    END
  END data[294]
  PIN data[295]
    DIRECTION INPUT ;
    USE SIGNAL ;
    PORT
      LAYER M4 ;
        RECT  0 72.72 0.084 72.744 ;
    END
  END data[295]
  PIN data[296]
    DIRECTION INPUT ;
    USE SIGNAL ;
    PORT
      LAYER M4 ;
        RECT  0 72.816 0.084 72.84 ;
    END
  END data[296]
  PIN data[297]
    DIRECTION INPUT ;
    USE SIGNAL ;
    PORT
      LAYER M4 ;
        RECT  0 72.912 0.084 72.936 ;
    END
  END data[297]
  PIN data[298]
    DIRECTION INPUT ;
    USE SIGNAL ;
    PORT
      LAYER M4 ;
        RECT  0 73.008 0.084 73.032 ;
    END
  END data[298]
  PIN data[299]
    DIRECTION INPUT ;
    USE SIGNAL ;
    PORT
      LAYER M4 ;
        RECT  0 73.104 0.084 73.128 ;
    END
  END data[299]
  PIN data[29]
    DIRECTION INPUT ;
    USE SIGNAL ;
    PORT
      LAYER M4 ;
        RECT  0 55.632 0.084 55.656 ;
    END
  END data[29]
  PIN data[2]
    DIRECTION INPUT ;
    USE SIGNAL ;
    PORT
      LAYER M4 ;
        RECT  0 53.04 0.084 53.064 ;
    END
  END data[2]
  PIN data[300]
    DIRECTION INPUT ;
    USE SIGNAL ;
    PORT
      LAYER M4 ;
        RECT  0 73.2 0.084 73.224 ;
    END
  END data[300]
  PIN data[301]
    DIRECTION INPUT ;
    USE SIGNAL ;
    PORT
      LAYER M4 ;
        RECT  0 73.296 0.084 73.32 ;
    END
  END data[301]
  PIN data[302]
    DIRECTION INPUT ;
    USE SIGNAL ;
    PORT
      LAYER M4 ;
        RECT  0 73.392 0.084 73.416 ;
    END
  END data[302]
  PIN data[303]
    DIRECTION INPUT ;
    USE SIGNAL ;
    PORT
      LAYER M4 ;
        RECT  0 73.488 0.084 73.512 ;
    END
  END data[303]
  PIN data[304]
    DIRECTION INPUT ;
    USE SIGNAL ;
    PORT
      LAYER M4 ;
        RECT  0 73.584 0.084 73.608 ;
    END
  END data[304]
  PIN data[305]
    DIRECTION INPUT ;
    USE SIGNAL ;
    PORT
      LAYER M4 ;
        RECT  0 73.68 0.084 73.704 ;
    END
  END data[305]
  PIN data[306]
    DIRECTION INPUT ;
    USE SIGNAL ;
    PORT
      LAYER M4 ;
        RECT  0 73.776 0.084 73.8 ;
    END
  END data[306]
  PIN data[307]
    DIRECTION INPUT ;
    USE SIGNAL ;
    PORT
      LAYER M4 ;
        RECT  0 73.872 0.084 73.896 ;
    END
  END data[307]
  PIN data[308]
    DIRECTION INPUT ;
    USE SIGNAL ;
    PORT
      LAYER M4 ;
        RECT  0 73.968 0.084 73.992 ;
    END
  END data[308]
  PIN data[309]
    DIRECTION INPUT ;
    USE SIGNAL ;
    PORT
      LAYER M4 ;
        RECT  0 74.064 0.084 74.088 ;
    END
  END data[309]
  PIN data[30]
    DIRECTION INPUT ;
    USE SIGNAL ;
    PORT
      LAYER M4 ;
        RECT  0 55.728 0.084 55.752 ;
    END
  END data[30]
  PIN data[310]
    DIRECTION INPUT ;
    USE SIGNAL ;
    PORT
      LAYER M4 ;
        RECT  0 74.16 0.084 74.184 ;
    END
  END data[310]
  PIN data[311]
    DIRECTION INPUT ;
    USE SIGNAL ;
    PORT
      LAYER M4 ;
        RECT  0 74.256 0.084 74.28 ;
    END
  END data[311]
  PIN data[312]
    DIRECTION INPUT ;
    USE SIGNAL ;
    PORT
      LAYER M4 ;
        RECT  0 74.352 0.084 74.376 ;
    END
  END data[312]
  PIN data[313]
    DIRECTION INPUT ;
    USE SIGNAL ;
    PORT
      LAYER M4 ;
        RECT  0 74.448 0.084 74.472 ;
    END
  END data[313]
  PIN data[314]
    DIRECTION INPUT ;
    USE SIGNAL ;
    PORT
      LAYER M4 ;
        RECT  0 74.544 0.084 74.568 ;
    END
  END data[314]
  PIN data[315]
    DIRECTION INPUT ;
    USE SIGNAL ;
    PORT
      LAYER M4 ;
        RECT  0 74.64 0.084 74.664 ;
    END
  END data[315]
  PIN data[316]
    DIRECTION INPUT ;
    USE SIGNAL ;
    PORT
      LAYER M4 ;
        RECT  0 74.736 0.084 74.76 ;
    END
  END data[316]
  PIN data[317]
    DIRECTION INPUT ;
    USE SIGNAL ;
    PORT
      LAYER M4 ;
        RECT  0 74.832 0.084 74.856 ;
    END
  END data[317]
  PIN data[318]
    DIRECTION INPUT ;
    USE SIGNAL ;
    PORT
      LAYER M4 ;
        RECT  0 74.928 0.084 74.952 ;
    END
  END data[318]
  PIN data[319]
    DIRECTION INPUT ;
    USE SIGNAL ;
    PORT
      LAYER M4 ;
        RECT  0 75.024 0.084 75.048 ;
    END
  END data[319]
  PIN data[31]
    DIRECTION INPUT ;
    USE SIGNAL ;
    PORT
      LAYER M4 ;
        RECT  0 55.824 0.084 55.848 ;
    END
  END data[31]
  PIN data[320]
    DIRECTION INPUT ;
    USE SIGNAL ;
    PORT
      LAYER M4 ;
        RECT  0 81.264 0.084 81.288 ;
    END
  END data[320]
  PIN data[321]
    DIRECTION INPUT ;
    USE SIGNAL ;
    PORT
      LAYER M4 ;
        RECT  0 81.36 0.084 81.384 ;
    END
  END data[321]
  PIN data[322]
    DIRECTION INPUT ;
    USE SIGNAL ;
    PORT
      LAYER M4 ;
        RECT  0 81.456 0.084 81.48 ;
    END
  END data[322]
  PIN data[323]
    DIRECTION INPUT ;
    USE SIGNAL ;
    PORT
      LAYER M4 ;
        RECT  0 81.552 0.084 81.576 ;
    END
  END data[323]
  PIN data[324]
    DIRECTION INPUT ;
    USE SIGNAL ;
    PORT
      LAYER M4 ;
        RECT  0 81.648 0.084 81.672 ;
    END
  END data[324]
  PIN data[325]
    DIRECTION INPUT ;
    USE SIGNAL ;
    PORT
      LAYER M4 ;
        RECT  0 81.744 0.084 81.768 ;
    END
  END data[325]
  PIN data[326]
    DIRECTION INPUT ;
    USE SIGNAL ;
    PORT
      LAYER M4 ;
        RECT  0 81.84 0.084 81.864 ;
    END
  END data[326]
  PIN data[327]
    DIRECTION INPUT ;
    USE SIGNAL ;
    PORT
      LAYER M4 ;
        RECT  0 81.936 0.084 81.96 ;
    END
  END data[327]
  PIN data[328]
    DIRECTION INPUT ;
    USE SIGNAL ;
    PORT
      LAYER M4 ;
        RECT  0 82.032 0.084 82.056 ;
    END
  END data[328]
  PIN data[329]
    DIRECTION INPUT ;
    USE SIGNAL ;
    PORT
      LAYER M4 ;
        RECT  0 82.128 0.084 82.152 ;
    END
  END data[329]
  PIN data[32]
    DIRECTION INPUT ;
    USE SIGNAL ;
    PORT
      LAYER M4 ;
        RECT  0 65.136 0.084 65.16 ;
    END
  END data[32]
  PIN data[330]
    DIRECTION INPUT ;
    USE SIGNAL ;
    PORT
      LAYER M4 ;
        RECT  0 82.224 0.084 82.248 ;
    END
  END data[330]
  PIN data[331]
    DIRECTION INPUT ;
    USE SIGNAL ;
    PORT
      LAYER M4 ;
        RECT  0 82.32 0.084 82.344 ;
    END
  END data[331]
  PIN data[332]
    DIRECTION INPUT ;
    USE SIGNAL ;
    PORT
      LAYER M4 ;
        RECT  0 82.416 0.084 82.44 ;
    END
  END data[332]
  PIN data[333]
    DIRECTION INPUT ;
    USE SIGNAL ;
    PORT
      LAYER M4 ;
        RECT  0 82.512 0.084 82.536 ;
    END
  END data[333]
  PIN data[334]
    DIRECTION INPUT ;
    USE SIGNAL ;
    PORT
      LAYER M4 ;
        RECT  0 82.608 0.084 82.632 ;
    END
  END data[334]
  PIN data[335]
    DIRECTION INPUT ;
    USE SIGNAL ;
    PORT
      LAYER M4 ;
        RECT  0 82.704 0.084 82.728 ;
    END
  END data[335]
  PIN data[336]
    DIRECTION INPUT ;
    USE SIGNAL ;
    PORT
      LAYER M4 ;
        RECT  0 82.8 0.084 82.824 ;
    END
  END data[336]
  PIN data[337]
    DIRECTION INPUT ;
    USE SIGNAL ;
    PORT
      LAYER M4 ;
        RECT  0 82.896 0.084 82.92 ;
    END
  END data[337]
  PIN data[338]
    DIRECTION INPUT ;
    USE SIGNAL ;
    PORT
      LAYER M4 ;
        RECT  0 82.992 0.084 83.016 ;
    END
  END data[338]
  PIN data[339]
    DIRECTION INPUT ;
    USE SIGNAL ;
    PORT
      LAYER M4 ;
        RECT  0 83.088 0.084 83.112 ;
    END
  END data[339]
  PIN data[33]
    DIRECTION INPUT ;
    USE SIGNAL ;
    PORT
      LAYER M4 ;
        RECT  0 65.232 0.084 65.256 ;
    END
  END data[33]
  PIN data[340]
    DIRECTION INPUT ;
    USE SIGNAL ;
    PORT
      LAYER M4 ;
        RECT  0 83.184 0.084 83.208 ;
    END
  END data[340]
  PIN data[341]
    DIRECTION INPUT ;
    USE SIGNAL ;
    PORT
      LAYER M4 ;
        RECT  0 83.28 0.084 83.304 ;
    END
  END data[341]
  PIN data[342]
    DIRECTION INPUT ;
    USE SIGNAL ;
    PORT
      LAYER M4 ;
        RECT  0 83.376 0.084 83.4 ;
    END
  END data[342]
  PIN data[343]
    DIRECTION INPUT ;
    USE SIGNAL ;
    PORT
      LAYER M4 ;
        RECT  0 83.472 0.084 83.496 ;
    END
  END data[343]
  PIN data[344]
    DIRECTION INPUT ;
    USE SIGNAL ;
    PORT
      LAYER M4 ;
        RECT  0 83.568 0.084 83.592 ;
    END
  END data[344]
  PIN data[345]
    DIRECTION INPUT ;
    USE SIGNAL ;
    PORT
      LAYER M4 ;
        RECT  0 83.664 0.084 83.688 ;
    END
  END data[345]
  PIN data[346]
    DIRECTION INPUT ;
    USE SIGNAL ;
    PORT
      LAYER M4 ;
        RECT  0 83.76 0.084 83.784 ;
    END
  END data[346]
  PIN data[347]
    DIRECTION INPUT ;
    USE SIGNAL ;
    PORT
      LAYER M4 ;
        RECT  0 83.856 0.084 83.88 ;
    END
  END data[347]
  PIN data[348]
    DIRECTION INPUT ;
    USE SIGNAL ;
    PORT
      LAYER M4 ;
        RECT  0 83.952 0.084 83.976 ;
    END
  END data[348]
  PIN data[349]
    DIRECTION INPUT ;
    USE SIGNAL ;
    PORT
      LAYER M4 ;
        RECT  0 84.048 0.084 84.072 ;
    END
  END data[349]
  PIN data[34]
    DIRECTION INPUT ;
    USE SIGNAL ;
    PORT
      LAYER M4 ;
        RECT  0 65.328 0.084 65.352 ;
    END
  END data[34]
  PIN data[350]
    DIRECTION INPUT ;
    USE SIGNAL ;
    PORT
      LAYER M4 ;
        RECT  0 84.144 0.084 84.168 ;
    END
  END data[350]
  PIN data[351]
    DIRECTION INPUT ;
    USE SIGNAL ;
    PORT
      LAYER M4 ;
        RECT  0 84.24 0.084 84.264 ;
    END
  END data[351]
  PIN data[352]
    DIRECTION INPUT ;
    USE SIGNAL ;
    PORT
      LAYER M4 ;
        RECT  0 87.408 0.084 87.432 ;
    END
  END data[352]
  PIN data[353]
    DIRECTION INPUT ;
    USE SIGNAL ;
    PORT
      LAYER M4 ;
        RECT  0 87.504 0.084 87.528 ;
    END
  END data[353]
  PIN data[354]
    DIRECTION INPUT ;
    USE SIGNAL ;
    PORT
      LAYER M4 ;
        RECT  0 87.6 0.084 87.624 ;
    END
  END data[354]
  PIN data[355]
    DIRECTION INPUT ;
    USE SIGNAL ;
    PORT
      LAYER M4 ;
        RECT  0 87.696 0.084 87.72 ;
    END
  END data[355]
  PIN data[356]
    DIRECTION INPUT ;
    USE SIGNAL ;
    PORT
      LAYER M4 ;
        RECT  0 87.792 0.084 87.816 ;
    END
  END data[356]
  PIN data[357]
    DIRECTION INPUT ;
    USE SIGNAL ;
    PORT
      LAYER M4 ;
        RECT  0 87.888 0.084 87.912 ;
    END
  END data[357]
  PIN data[358]
    DIRECTION INPUT ;
    USE SIGNAL ;
    PORT
      LAYER M4 ;
        RECT  0 87.984 0.084 88.008 ;
    END
  END data[358]
  PIN data[359]
    DIRECTION INPUT ;
    USE SIGNAL ;
    PORT
      LAYER M4 ;
        RECT  0 88.08 0.084 88.104 ;
    END
  END data[359]
  PIN data[35]
    DIRECTION INPUT ;
    USE SIGNAL ;
    PORT
      LAYER M4 ;
        RECT  0 65.424 0.084 65.448 ;
    END
  END data[35]
  PIN data[360]
    DIRECTION INPUT ;
    USE SIGNAL ;
    PORT
      LAYER M4 ;
        RECT  0 88.176 0.084 88.2 ;
    END
  END data[360]
  PIN data[361]
    DIRECTION INPUT ;
    USE SIGNAL ;
    PORT
      LAYER M4 ;
        RECT  0 88.272 0.084 88.296 ;
    END
  END data[361]
  PIN data[362]
    DIRECTION INPUT ;
    USE SIGNAL ;
    PORT
      LAYER M4 ;
        RECT  0 88.368 0.084 88.392 ;
    END
  END data[362]
  PIN data[363]
    DIRECTION INPUT ;
    USE SIGNAL ;
    PORT
      LAYER M4 ;
        RECT  0 88.464 0.084 88.488 ;
    END
  END data[363]
  PIN data[364]
    DIRECTION INPUT ;
    USE SIGNAL ;
    PORT
      LAYER M4 ;
        RECT  0 88.56 0.084 88.584 ;
    END
  END data[364]
  PIN data[365]
    DIRECTION INPUT ;
    USE SIGNAL ;
    PORT
      LAYER M4 ;
        RECT  0 88.656 0.084 88.68 ;
    END
  END data[365]
  PIN data[366]
    DIRECTION INPUT ;
    USE SIGNAL ;
    PORT
      LAYER M4 ;
        RECT  0 88.752 0.084 88.776 ;
    END
  END data[366]
  PIN data[367]
    DIRECTION INPUT ;
    USE SIGNAL ;
    PORT
      LAYER M4 ;
        RECT  0 88.848 0.084 88.872 ;
    END
  END data[367]
  PIN data[368]
    DIRECTION INPUT ;
    USE SIGNAL ;
    PORT
      LAYER M4 ;
        RECT  0 88.944 0.084 88.968 ;
    END
  END data[368]
  PIN data[369]
    DIRECTION INPUT ;
    USE SIGNAL ;
    PORT
      LAYER M4 ;
        RECT  0 89.04 0.084 89.064 ;
    END
  END data[369]
  PIN data[36]
    DIRECTION INPUT ;
    USE SIGNAL ;
    PORT
      LAYER M4 ;
        RECT  0 65.52 0.084 65.544 ;
    END
  END data[36]
  PIN data[370]
    DIRECTION INPUT ;
    USE SIGNAL ;
    PORT
      LAYER M4 ;
        RECT  0 89.136 0.084 89.16 ;
    END
  END data[370]
  PIN data[371]
    DIRECTION INPUT ;
    USE SIGNAL ;
    PORT
      LAYER M4 ;
        RECT  0 89.232 0.084 89.256 ;
    END
  END data[371]
  PIN data[372]
    DIRECTION INPUT ;
    USE SIGNAL ;
    PORT
      LAYER M4 ;
        RECT  0 89.328 0.084 89.352 ;
    END
  END data[372]
  PIN data[373]
    DIRECTION INPUT ;
    USE SIGNAL ;
    PORT
      LAYER M4 ;
        RECT  0 89.424 0.084 89.448 ;
    END
  END data[373]
  PIN data[374]
    DIRECTION INPUT ;
    USE SIGNAL ;
    PORT
      LAYER M4 ;
        RECT  0 89.52 0.084 89.544 ;
    END
  END data[374]
  PIN data[375]
    DIRECTION INPUT ;
    USE SIGNAL ;
    PORT
      LAYER M4 ;
        RECT  0 89.616 0.084 89.64 ;
    END
  END data[375]
  PIN data[376]
    DIRECTION INPUT ;
    USE SIGNAL ;
    PORT
      LAYER M4 ;
        RECT  0 89.712 0.084 89.736 ;
    END
  END data[376]
  PIN data[377]
    DIRECTION INPUT ;
    USE SIGNAL ;
    PORT
      LAYER M4 ;
        RECT  0 89.808 0.084 89.832 ;
    END
  END data[377]
  PIN data[378]
    DIRECTION INPUT ;
    USE SIGNAL ;
    PORT
      LAYER M4 ;
        RECT  0 89.904 0.084 89.928 ;
    END
  END data[378]
  PIN data[379]
    DIRECTION INPUT ;
    USE SIGNAL ;
    PORT
      LAYER M4 ;
        RECT  0 90 0.084 90.024 ;
    END
  END data[379]
  PIN data[37]
    DIRECTION INPUT ;
    USE SIGNAL ;
    PORT
      LAYER M4 ;
        RECT  0 65.616 0.084 65.64 ;
    END
  END data[37]
  PIN data[380]
    DIRECTION INPUT ;
    USE SIGNAL ;
    PORT
      LAYER M4 ;
        RECT  0 90.096 0.084 90.12 ;
    END
  END data[380]
  PIN data[381]
    DIRECTION INPUT ;
    USE SIGNAL ;
    PORT
      LAYER M4 ;
        RECT  0 90.192 0.084 90.216 ;
    END
  END data[381]
  PIN data[382]
    DIRECTION INPUT ;
    USE SIGNAL ;
    PORT
      LAYER M4 ;
        RECT  0 90.288 0.084 90.312 ;
    END
  END data[382]
  PIN data[383]
    DIRECTION INPUT ;
    USE SIGNAL ;
    PORT
      LAYER M4 ;
        RECT  0 90.384 0.084 90.408 ;
    END
  END data[383]
  PIN data[384]
    DIRECTION INPUT ;
    USE SIGNAL ;
    PORT
      LAYER M4 ;
        RECT  0 45.936 0.084 45.96 ;
    END
  END data[384]
  PIN data[385]
    DIRECTION INPUT ;
    USE SIGNAL ;
    PORT
      LAYER M4 ;
        RECT  0 46.032 0.084 46.056 ;
    END
  END data[385]
  PIN data[386]
    DIRECTION INPUT ;
    USE SIGNAL ;
    PORT
      LAYER M4 ;
        RECT  0 46.128 0.084 46.152 ;
    END
  END data[386]
  PIN data[387]
    DIRECTION INPUT ;
    USE SIGNAL ;
    PORT
      LAYER M4 ;
        RECT  0 46.224 0.084 46.248 ;
    END
  END data[387]
  PIN data[388]
    DIRECTION INPUT ;
    USE SIGNAL ;
    PORT
      LAYER M4 ;
        RECT  0 46.32 0.084 46.344 ;
    END
  END data[388]
  PIN data[389]
    DIRECTION INPUT ;
    USE SIGNAL ;
    PORT
      LAYER M4 ;
        RECT  0 46.416 0.084 46.44 ;
    END
  END data[389]
  PIN data[38]
    DIRECTION INPUT ;
    USE SIGNAL ;
    PORT
      LAYER M4 ;
        RECT  0 65.712 0.084 65.736 ;
    END
  END data[38]
  PIN data[390]
    DIRECTION INPUT ;
    USE SIGNAL ;
    PORT
      LAYER M4 ;
        RECT  0 46.512 0.084 46.536 ;
    END
  END data[390]
  PIN data[391]
    DIRECTION INPUT ;
    USE SIGNAL ;
    PORT
      LAYER M4 ;
        RECT  0 46.608 0.084 46.632 ;
    END
  END data[391]
  PIN data[392]
    DIRECTION INPUT ;
    USE SIGNAL ;
    PORT
      LAYER M4 ;
        RECT  0 46.704 0.084 46.728 ;
    END
  END data[392]
  PIN data[393]
    DIRECTION INPUT ;
    USE SIGNAL ;
    PORT
      LAYER M4 ;
        RECT  0 46.8 0.084 46.824 ;
    END
  END data[393]
  PIN data[394]
    DIRECTION INPUT ;
    USE SIGNAL ;
    PORT
      LAYER M4 ;
        RECT  0 46.896 0.084 46.92 ;
    END
  END data[394]
  PIN data[395]
    DIRECTION INPUT ;
    USE SIGNAL ;
    PORT
      LAYER M4 ;
        RECT  0 46.992 0.084 47.016 ;
    END
  END data[395]
  PIN data[396]
    DIRECTION INPUT ;
    USE SIGNAL ;
    PORT
      LAYER M4 ;
        RECT  0 47.088 0.084 47.112 ;
    END
  END data[396]
  PIN data[397]
    DIRECTION INPUT ;
    USE SIGNAL ;
    PORT
      LAYER M4 ;
        RECT  0 47.184 0.084 47.208 ;
    END
  END data[397]
  PIN data[398]
    DIRECTION INPUT ;
    USE SIGNAL ;
    PORT
      LAYER M4 ;
        RECT  0 47.28 0.084 47.304 ;
    END
  END data[398]
  PIN data[399]
    DIRECTION INPUT ;
    USE SIGNAL ;
    PORT
      LAYER M4 ;
        RECT  0 47.376 0.084 47.4 ;
    END
  END data[399]
  PIN data[39]
    DIRECTION INPUT ;
    USE SIGNAL ;
    PORT
      LAYER M4 ;
        RECT  0 65.808 0.084 65.832 ;
    END
  END data[39]
  PIN data[3]
    DIRECTION INPUT ;
    USE SIGNAL ;
    PORT
      LAYER M4 ;
        RECT  0 53.136 0.084 53.16 ;
    END
  END data[3]
  PIN data[400]
    DIRECTION INPUT ;
    USE SIGNAL ;
    PORT
      LAYER M4 ;
        RECT  0 47.472 0.084 47.496 ;
    END
  END data[400]
  PIN data[401]
    DIRECTION INPUT ;
    USE SIGNAL ;
    PORT
      LAYER M4 ;
        RECT  0 47.568 0.084 47.592 ;
    END
  END data[401]
  PIN data[402]
    DIRECTION INPUT ;
    USE SIGNAL ;
    PORT
      LAYER M4 ;
        RECT  0 47.664 0.084 47.688 ;
    END
  END data[402]
  PIN data[403]
    DIRECTION INPUT ;
    USE SIGNAL ;
    PORT
      LAYER M4 ;
        RECT  0 47.76 0.084 47.784 ;
    END
  END data[403]
  PIN data[404]
    DIRECTION INPUT ;
    USE SIGNAL ;
    PORT
      LAYER M4 ;
        RECT  0 47.856 0.084 47.88 ;
    END
  END data[404]
  PIN data[405]
    DIRECTION INPUT ;
    USE SIGNAL ;
    PORT
      LAYER M4 ;
        RECT  0 47.952 0.084 47.976 ;
    END
  END data[405]
  PIN data[406]
    DIRECTION INPUT ;
    USE SIGNAL ;
    PORT
      LAYER M4 ;
        RECT  0 48.048 0.084 48.072 ;
    END
  END data[406]
  PIN data[407]
    DIRECTION INPUT ;
    USE SIGNAL ;
    PORT
      LAYER M4 ;
        RECT  0 48.144 0.084 48.168 ;
    END
  END data[407]
  PIN data[408]
    DIRECTION INPUT ;
    USE SIGNAL ;
    PORT
      LAYER M4 ;
        RECT  0 48.24 0.084 48.264 ;
    END
  END data[408]
  PIN data[409]
    DIRECTION INPUT ;
    USE SIGNAL ;
    PORT
      LAYER M4 ;
        RECT  0 48.336 0.084 48.36 ;
    END
  END data[409]
  PIN data[40]
    DIRECTION INPUT ;
    USE SIGNAL ;
    PORT
      LAYER M4 ;
        RECT  0 65.904 0.084 65.928 ;
    END
  END data[40]
  PIN data[410]
    DIRECTION INPUT ;
    USE SIGNAL ;
    PORT
      LAYER M4 ;
        RECT  0 48.432 0.084 48.456 ;
    END
  END data[410]
  PIN data[411]
    DIRECTION INPUT ;
    USE SIGNAL ;
    PORT
      LAYER M4 ;
        RECT  0 48.528 0.084 48.552 ;
    END
  END data[411]
  PIN data[412]
    DIRECTION INPUT ;
    USE SIGNAL ;
    PORT
      LAYER M4 ;
        RECT  0 48.624 0.084 48.648 ;
    END
  END data[412]
  PIN data[413]
    DIRECTION INPUT ;
    USE SIGNAL ;
    PORT
      LAYER M4 ;
        RECT  0 48.72 0.084 48.744 ;
    END
  END data[413]
  PIN data[414]
    DIRECTION INPUT ;
    USE SIGNAL ;
    PORT
      LAYER M4 ;
        RECT  0 48.816 0.084 48.84 ;
    END
  END data[414]
  PIN data[415]
    DIRECTION INPUT ;
    USE SIGNAL ;
    PORT
      LAYER M4 ;
        RECT  0 48.912 0.084 48.936 ;
    END
  END data[415]
  PIN data[416]
    DIRECTION INPUT ;
    USE SIGNAL ;
    PORT
      LAYER M4 ;
        RECT  0 49.008 0.084 49.032 ;
    END
  END data[416]
  PIN data[417]
    DIRECTION INPUT ;
    USE SIGNAL ;
    PORT
      LAYER M4 ;
        RECT  0 49.104 0.084 49.128 ;
    END
  END data[417]
  PIN data[418]
    DIRECTION INPUT ;
    USE SIGNAL ;
    PORT
      LAYER M4 ;
        RECT  0 49.2 0.084 49.224 ;
    END
  END data[418]
  PIN data[419]
    DIRECTION INPUT ;
    USE SIGNAL ;
    PORT
      LAYER M4 ;
        RECT  0 49.296 0.084 49.32 ;
    END
  END data[419]
  PIN data[41]
    DIRECTION INPUT ;
    USE SIGNAL ;
    PORT
      LAYER M4 ;
        RECT  0 66 0.084 66.024 ;
    END
  END data[41]
  PIN data[420]
    DIRECTION INPUT ;
    USE SIGNAL ;
    PORT
      LAYER M4 ;
        RECT  0 49.392 0.084 49.416 ;
    END
  END data[420]
  PIN data[421]
    DIRECTION INPUT ;
    USE SIGNAL ;
    PORT
      LAYER M4 ;
        RECT  0 49.488 0.084 49.512 ;
    END
  END data[421]
  PIN data[422]
    DIRECTION INPUT ;
    USE SIGNAL ;
    PORT
      LAYER M4 ;
        RECT  0 49.584 0.084 49.608 ;
    END
  END data[422]
  PIN data[423]
    DIRECTION INPUT ;
    USE SIGNAL ;
    PORT
      LAYER M4 ;
        RECT  0 49.68 0.084 49.704 ;
    END
  END data[423]
  PIN data[424]
    DIRECTION INPUT ;
    USE SIGNAL ;
    PORT
      LAYER M4 ;
        RECT  0 49.776 0.084 49.8 ;
    END
  END data[424]
  PIN data[425]
    DIRECTION INPUT ;
    USE SIGNAL ;
    PORT
      LAYER M4 ;
        RECT  0 49.872 0.084 49.896 ;
    END
  END data[425]
  PIN data[426]
    DIRECTION INPUT ;
    USE SIGNAL ;
    PORT
      LAYER M4 ;
        RECT  0 49.968 0.084 49.992 ;
    END
  END data[426]
  PIN data[427]
    DIRECTION INPUT ;
    USE SIGNAL ;
    PORT
      LAYER M4 ;
        RECT  0 50.064 0.084 50.088 ;
    END
  END data[427]
  PIN data[428]
    DIRECTION INPUT ;
    USE SIGNAL ;
    PORT
      LAYER M4 ;
        RECT  0 50.16 0.084 50.184 ;
    END
  END data[428]
  PIN data[429]
    DIRECTION INPUT ;
    USE SIGNAL ;
    PORT
      LAYER M4 ;
        RECT  0 50.256 0.084 50.28 ;
    END
  END data[429]
  PIN data[42]
    DIRECTION INPUT ;
    USE SIGNAL ;
    PORT
      LAYER M4 ;
        RECT  0 66.096 0.084 66.12 ;
    END
  END data[42]
  PIN data[430]
    DIRECTION INPUT ;
    USE SIGNAL ;
    PORT
      LAYER M4 ;
        RECT  0 50.352 0.084 50.376 ;
    END
  END data[430]
  PIN data[431]
    DIRECTION INPUT ;
    USE SIGNAL ;
    PORT
      LAYER M4 ;
        RECT  0 50.448 0.084 50.472 ;
    END
  END data[431]
  PIN data[432]
    DIRECTION INPUT ;
    USE SIGNAL ;
    PORT
      LAYER M4 ;
        RECT  0 50.544 0.084 50.568 ;
    END
  END data[432]
  PIN data[433]
    DIRECTION INPUT ;
    USE SIGNAL ;
    PORT
      LAYER M4 ;
        RECT  0 50.64 0.084 50.664 ;
    END
  END data[433]
  PIN data[434]
    DIRECTION INPUT ;
    USE SIGNAL ;
    PORT
      LAYER M4 ;
        RECT  0 50.736 0.084 50.76 ;
    END
  END data[434]
  PIN data[435]
    DIRECTION INPUT ;
    USE SIGNAL ;
    PORT
      LAYER M4 ;
        RECT  0 50.832 0.084 50.856 ;
    END
  END data[435]
  PIN data[436]
    DIRECTION INPUT ;
    USE SIGNAL ;
    PORT
      LAYER M4 ;
        RECT  0 50.928 0.084 50.952 ;
    END
  END data[436]
  PIN data[437]
    DIRECTION INPUT ;
    USE SIGNAL ;
    PORT
      LAYER M4 ;
        RECT  0 51.024 0.084 51.048 ;
    END
  END data[437]
  PIN data[438]
    DIRECTION INPUT ;
    USE SIGNAL ;
    PORT
      LAYER M4 ;
        RECT  0 51.12 0.084 51.144 ;
    END
  END data[438]
  PIN data[439]
    DIRECTION INPUT ;
    USE SIGNAL ;
    PORT
      LAYER M4 ;
        RECT  0 51.216 0.084 51.24 ;
    END
  END data[439]
  PIN data[43]
    DIRECTION INPUT ;
    USE SIGNAL ;
    PORT
      LAYER M4 ;
        RECT  0 66.192 0.084 66.216 ;
    END
  END data[43]
  PIN data[440]
    DIRECTION INPUT ;
    USE SIGNAL ;
    PORT
      LAYER M4 ;
        RECT  0 51.312 0.084 51.336 ;
    END
  END data[440]
  PIN data[441]
    DIRECTION INPUT ;
    USE SIGNAL ;
    PORT
      LAYER M4 ;
        RECT  0 51.408 0.084 51.432 ;
    END
  END data[441]
  PIN data[442]
    DIRECTION INPUT ;
    USE SIGNAL ;
    PORT
      LAYER M4 ;
        RECT  0 51.504 0.084 51.528 ;
    END
  END data[442]
  PIN data[443]
    DIRECTION INPUT ;
    USE SIGNAL ;
    PORT
      LAYER M4 ;
        RECT  0 51.6 0.084 51.624 ;
    END
  END data[443]
  PIN data[444]
    DIRECTION INPUT ;
    USE SIGNAL ;
    PORT
      LAYER M4 ;
        RECT  0 51.696 0.084 51.72 ;
    END
  END data[444]
  PIN data[445]
    DIRECTION INPUT ;
    USE SIGNAL ;
    PORT
      LAYER M4 ;
        RECT  0 51.792 0.084 51.816 ;
    END
  END data[445]
  PIN data[446]
    DIRECTION INPUT ;
    USE SIGNAL ;
    PORT
      LAYER M4 ;
        RECT  0 51.888 0.084 51.912 ;
    END
  END data[446]
  PIN data[447]
    DIRECTION INPUT ;
    USE SIGNAL ;
    PORT
      LAYER M4 ;
        RECT  0 51.984 0.084 52.008 ;
    END
  END data[447]
  PIN data[448]
    DIRECTION INPUT ;
    USE SIGNAL ;
    PORT
      LAYER M4 ;
        RECT  0 39.792 0.084 39.816 ;
    END
  END data[448]
  PIN data[449]
    DIRECTION INPUT ;
    USE SIGNAL ;
    PORT
      LAYER M4 ;
        RECT  0 39.888 0.084 39.912 ;
    END
  END data[449]
  PIN data[44]
    DIRECTION INPUT ;
    USE SIGNAL ;
    PORT
      LAYER M4 ;
        RECT  0 66.288 0.084 66.312 ;
    END
  END data[44]
  PIN data[450]
    DIRECTION INPUT ;
    USE SIGNAL ;
    PORT
      LAYER M4 ;
        RECT  0 39.984 0.084 40.008 ;
    END
  END data[450]
  PIN data[451]
    DIRECTION INPUT ;
    USE SIGNAL ;
    PORT
      LAYER M4 ;
        RECT  0 40.08 0.084 40.104 ;
    END
  END data[451]
  PIN data[452]
    DIRECTION INPUT ;
    USE SIGNAL ;
    PORT
      LAYER M4 ;
        RECT  0 40.176 0.084 40.2 ;
    END
  END data[452]
  PIN data[453]
    DIRECTION INPUT ;
    USE SIGNAL ;
    PORT
      LAYER M4 ;
        RECT  0 40.272 0.084 40.296 ;
    END
  END data[453]
  PIN data[454]
    DIRECTION INPUT ;
    USE SIGNAL ;
    PORT
      LAYER M4 ;
        RECT  0 40.368 0.084 40.392 ;
    END
  END data[454]
  PIN data[455]
    DIRECTION INPUT ;
    USE SIGNAL ;
    PORT
      LAYER M4 ;
        RECT  0 40.464 0.084 40.488 ;
    END
  END data[455]
  PIN data[456]
    DIRECTION INPUT ;
    USE SIGNAL ;
    PORT
      LAYER M4 ;
        RECT  0 40.56 0.084 40.584 ;
    END
  END data[456]
  PIN data[457]
    DIRECTION INPUT ;
    USE SIGNAL ;
    PORT
      LAYER M4 ;
        RECT  0 40.656 0.084 40.68 ;
    END
  END data[457]
  PIN data[458]
    DIRECTION INPUT ;
    USE SIGNAL ;
    PORT
      LAYER M4 ;
        RECT  0 40.752 0.084 40.776 ;
    END
  END data[458]
  PIN data[459]
    DIRECTION INPUT ;
    USE SIGNAL ;
    PORT
      LAYER M4 ;
        RECT  0 40.848 0.084 40.872 ;
    END
  END data[459]
  PIN data[45]
    DIRECTION INPUT ;
    USE SIGNAL ;
    PORT
      LAYER M4 ;
        RECT  0 66.384 0.084 66.408 ;
    END
  END data[45]
  PIN data[460]
    DIRECTION INPUT ;
    USE SIGNAL ;
    PORT
      LAYER M4 ;
        RECT  0 40.944 0.084 40.968 ;
    END
  END data[460]
  PIN data[461]
    DIRECTION INPUT ;
    USE SIGNAL ;
    PORT
      LAYER M4 ;
        RECT  0 41.04 0.084 41.064 ;
    END
  END data[461]
  PIN data[462]
    DIRECTION INPUT ;
    USE SIGNAL ;
    PORT
      LAYER M4 ;
        RECT  0 41.136 0.084 41.16 ;
    END
  END data[462]
  PIN data[463]
    DIRECTION INPUT ;
    USE SIGNAL ;
    PORT
      LAYER M4 ;
        RECT  0 41.232 0.084 41.256 ;
    END
  END data[463]
  PIN data[464]
    DIRECTION INPUT ;
    USE SIGNAL ;
    PORT
      LAYER M4 ;
        RECT  0 41.328 0.084 41.352 ;
    END
  END data[464]
  PIN data[465]
    DIRECTION INPUT ;
    USE SIGNAL ;
    PORT
      LAYER M4 ;
        RECT  0 41.424 0.084 41.448 ;
    END
  END data[465]
  PIN data[466]
    DIRECTION INPUT ;
    USE SIGNAL ;
    PORT
      LAYER M4 ;
        RECT  0 41.52 0.084 41.544 ;
    END
  END data[466]
  PIN data[467]
    DIRECTION INPUT ;
    USE SIGNAL ;
    PORT
      LAYER M4 ;
        RECT  0 41.616 0.084 41.64 ;
    END
  END data[467]
  PIN data[468]
    DIRECTION INPUT ;
    USE SIGNAL ;
    PORT
      LAYER M4 ;
        RECT  0 41.712 0.084 41.736 ;
    END
  END data[468]
  PIN data[469]
    DIRECTION INPUT ;
    USE SIGNAL ;
    PORT
      LAYER M4 ;
        RECT  0 41.808 0.084 41.832 ;
    END
  END data[469]
  PIN data[46]
    DIRECTION INPUT ;
    USE SIGNAL ;
    PORT
      LAYER M4 ;
        RECT  0 66.48 0.084 66.504 ;
    END
  END data[46]
  PIN data[470]
    DIRECTION INPUT ;
    USE SIGNAL ;
    PORT
      LAYER M4 ;
        RECT  0 41.904 0.084 41.928 ;
    END
  END data[470]
  PIN data[471]
    DIRECTION INPUT ;
    USE SIGNAL ;
    PORT
      LAYER M4 ;
        RECT  0 42 0.084 42.024 ;
    END
  END data[471]
  PIN data[472]
    DIRECTION INPUT ;
    USE SIGNAL ;
    PORT
      LAYER M4 ;
        RECT  0 42.096 0.084 42.12 ;
    END
  END data[472]
  PIN data[473]
    DIRECTION INPUT ;
    USE SIGNAL ;
    PORT
      LAYER M4 ;
        RECT  0 42.192 0.084 42.216 ;
    END
  END data[473]
  PIN data[474]
    DIRECTION INPUT ;
    USE SIGNAL ;
    PORT
      LAYER M4 ;
        RECT  0 42.288 0.084 42.312 ;
    END
  END data[474]
  PIN data[475]
    DIRECTION INPUT ;
    USE SIGNAL ;
    PORT
      LAYER M4 ;
        RECT  0 42.384 0.084 42.408 ;
    END
  END data[475]
  PIN data[476]
    DIRECTION INPUT ;
    USE SIGNAL ;
    PORT
      LAYER M4 ;
        RECT  0 42.48 0.084 42.504 ;
    END
  END data[476]
  PIN data[477]
    DIRECTION INPUT ;
    USE SIGNAL ;
    PORT
      LAYER M4 ;
        RECT  0 42.576 0.084 42.6 ;
    END
  END data[477]
  PIN data[478]
    DIRECTION INPUT ;
    USE SIGNAL ;
    PORT
      LAYER M4 ;
        RECT  0 42.672 0.084 42.696 ;
    END
  END data[478]
  PIN data[479]
    DIRECTION INPUT ;
    USE SIGNAL ;
    PORT
      LAYER M4 ;
        RECT  0 42.768 0.084 42.792 ;
    END
  END data[479]
  PIN data[47]
    DIRECTION INPUT ;
    USE SIGNAL ;
    PORT
      LAYER M4 ;
        RECT  0 66.576 0.084 66.6 ;
    END
  END data[47]
  PIN data[480]
    DIRECTION INPUT ;
    USE SIGNAL ;
    PORT
      LAYER M4 ;
        RECT  0 42.864 0.084 42.888 ;
    END
  END data[480]
  PIN data[481]
    DIRECTION INPUT ;
    USE SIGNAL ;
    PORT
      LAYER M4 ;
        RECT  0 42.96 0.084 42.984 ;
    END
  END data[481]
  PIN data[482]
    DIRECTION INPUT ;
    USE SIGNAL ;
    PORT
      LAYER M4 ;
        RECT  0 43.056 0.084 43.08 ;
    END
  END data[482]
  PIN data[483]
    DIRECTION INPUT ;
    USE SIGNAL ;
    PORT
      LAYER M4 ;
        RECT  0 43.152 0.084 43.176 ;
    END
  END data[483]
  PIN data[484]
    DIRECTION INPUT ;
    USE SIGNAL ;
    PORT
      LAYER M4 ;
        RECT  0 43.248 0.084 43.272 ;
    END
  END data[484]
  PIN data[485]
    DIRECTION INPUT ;
    USE SIGNAL ;
    PORT
      LAYER M4 ;
        RECT  0 43.344 0.084 43.368 ;
    END
  END data[485]
  PIN data[486]
    DIRECTION INPUT ;
    USE SIGNAL ;
    PORT
      LAYER M4 ;
        RECT  0 43.44 0.084 43.464 ;
    END
  END data[486]
  PIN data[487]
    DIRECTION INPUT ;
    USE SIGNAL ;
    PORT
      LAYER M4 ;
        RECT  0 43.536 0.084 43.56 ;
    END
  END data[487]
  PIN data[488]
    DIRECTION INPUT ;
    USE SIGNAL ;
    PORT
      LAYER M4 ;
        RECT  0 43.632 0.084 43.656 ;
    END
  END data[488]
  PIN data[489]
    DIRECTION INPUT ;
    USE SIGNAL ;
    PORT
      LAYER M4 ;
        RECT  0 43.728 0.084 43.752 ;
    END
  END data[489]
  PIN data[48]
    DIRECTION INPUT ;
    USE SIGNAL ;
    PORT
      LAYER M4 ;
        RECT  0 66.672 0.084 66.696 ;
    END
  END data[48]
  PIN data[490]
    DIRECTION INPUT ;
    USE SIGNAL ;
    PORT
      LAYER M4 ;
        RECT  0 43.824 0.084 43.848 ;
    END
  END data[490]
  PIN data[491]
    DIRECTION INPUT ;
    USE SIGNAL ;
    PORT
      LAYER M4 ;
        RECT  0 43.92 0.084 43.944 ;
    END
  END data[491]
  PIN data[492]
    DIRECTION INPUT ;
    USE SIGNAL ;
    PORT
      LAYER M4 ;
        RECT  0 44.016 0.084 44.04 ;
    END
  END data[492]
  PIN data[493]
    DIRECTION INPUT ;
    USE SIGNAL ;
    PORT
      LAYER M4 ;
        RECT  0 44.112 0.084 44.136 ;
    END
  END data[493]
  PIN data[494]
    DIRECTION INPUT ;
    USE SIGNAL ;
    PORT
      LAYER M4 ;
        RECT  0 44.208 0.084 44.232 ;
    END
  END data[494]
  PIN data[495]
    DIRECTION INPUT ;
    USE SIGNAL ;
    PORT
      LAYER M4 ;
        RECT  0 44.304 0.084 44.328 ;
    END
  END data[495]
  PIN data[496]
    DIRECTION INPUT ;
    USE SIGNAL ;
    PORT
      LAYER M4 ;
        RECT  0 44.4 0.084 44.424 ;
    END
  END data[496]
  PIN data[497]
    DIRECTION INPUT ;
    USE SIGNAL ;
    PORT
      LAYER M4 ;
        RECT  0 44.496 0.084 44.52 ;
    END
  END data[497]
  PIN data[498]
    DIRECTION INPUT ;
    USE SIGNAL ;
    PORT
      LAYER M4 ;
        RECT  0 44.592 0.084 44.616 ;
    END
  END data[498]
  PIN data[499]
    DIRECTION INPUT ;
    USE SIGNAL ;
    PORT
      LAYER M4 ;
        RECT  0 44.688 0.084 44.712 ;
    END
  END data[499]
  PIN data[49]
    DIRECTION INPUT ;
    USE SIGNAL ;
    PORT
      LAYER M4 ;
        RECT  0 66.768 0.084 66.792 ;
    END
  END data[49]
  PIN data[4]
    DIRECTION INPUT ;
    USE SIGNAL ;
    PORT
      LAYER M4 ;
        RECT  0 53.232 0.084 53.256 ;
    END
  END data[4]
  PIN data[500]
    DIRECTION INPUT ;
    USE SIGNAL ;
    PORT
      LAYER M4 ;
        RECT  0 44.784 0.084 44.808 ;
    END
  END data[500]
  PIN data[501]
    DIRECTION INPUT ;
    USE SIGNAL ;
    PORT
      LAYER M4 ;
        RECT  0 44.88 0.084 44.904 ;
    END
  END data[501]
  PIN data[502]
    DIRECTION INPUT ;
    USE SIGNAL ;
    PORT
      LAYER M4 ;
        RECT  0 44.976 0.084 45 ;
    END
  END data[502]
  PIN data[503]
    DIRECTION INPUT ;
    USE SIGNAL ;
    PORT
      LAYER M4 ;
        RECT  0 45.072 0.084 45.096 ;
    END
  END data[503]
  PIN data[504]
    DIRECTION INPUT ;
    USE SIGNAL ;
    PORT
      LAYER M4 ;
        RECT  0 45.168 0.084 45.192 ;
    END
  END data[504]
  PIN data[505]
    DIRECTION INPUT ;
    USE SIGNAL ;
    PORT
      LAYER M4 ;
        RECT  0 45.264 0.084 45.288 ;
    END
  END data[505]
  PIN data[506]
    DIRECTION INPUT ;
    USE SIGNAL ;
    PORT
      LAYER M4 ;
        RECT  0 45.36 0.084 45.384 ;
    END
  END data[506]
  PIN data[507]
    DIRECTION INPUT ;
    USE SIGNAL ;
    PORT
      LAYER M4 ;
        RECT  0 45.456 0.084 45.48 ;
    END
  END data[507]
  PIN data[508]
    DIRECTION INPUT ;
    USE SIGNAL ;
    PORT
      LAYER M4 ;
        RECT  0 45.552 0.084 45.576 ;
    END
  END data[508]
  PIN data[509]
    DIRECTION INPUT ;
    USE SIGNAL ;
    PORT
      LAYER M4 ;
        RECT  0 45.648 0.084 45.672 ;
    END
  END data[509]
  PIN data[50]
    DIRECTION INPUT ;
    USE SIGNAL ;
    PORT
      LAYER M4 ;
        RECT  0 66.864 0.084 66.888 ;
    END
  END data[50]
  PIN data[510]
    DIRECTION INPUT ;
    USE SIGNAL ;
    PORT
      LAYER M4 ;
        RECT  0 45.744 0.084 45.768 ;
    END
  END data[510]
  PIN data[511]
    DIRECTION INPUT ;
    USE SIGNAL ;
    PORT
      LAYER M4 ;
        RECT  0 45.84 0.084 45.864 ;
    END
  END data[511]
  PIN data[51]
    DIRECTION INPUT ;
    USE SIGNAL ;
    PORT
      LAYER M4 ;
        RECT  0 66.96 0.084 66.984 ;
    END
  END data[51]
  PIN data[52]
    DIRECTION INPUT ;
    USE SIGNAL ;
    PORT
      LAYER M4 ;
        RECT  0 67.056 0.084 67.08 ;
    END
  END data[52]
  PIN data[53]
    DIRECTION INPUT ;
    USE SIGNAL ;
    PORT
      LAYER M4 ;
        RECT  0 67.152 0.084 67.176 ;
    END
  END data[53]
  PIN data[54]
    DIRECTION INPUT ;
    USE SIGNAL ;
    PORT
      LAYER M4 ;
        RECT  0 67.248 0.084 67.272 ;
    END
  END data[54]
  PIN data[55]
    DIRECTION INPUT ;
    USE SIGNAL ;
    PORT
      LAYER M4 ;
        RECT  0 67.344 0.084 67.368 ;
    END
  END data[55]
  PIN data[56]
    DIRECTION INPUT ;
    USE SIGNAL ;
    PORT
      LAYER M4 ;
        RECT  0 67.44 0.084 67.464 ;
    END
  END data[56]
  PIN data[57]
    DIRECTION INPUT ;
    USE SIGNAL ;
    PORT
      LAYER M4 ;
        RECT  0 67.536 0.084 67.56 ;
    END
  END data[57]
  PIN data[58]
    DIRECTION INPUT ;
    USE SIGNAL ;
    PORT
      LAYER M4 ;
        RECT  0 67.632 0.084 67.656 ;
    END
  END data[58]
  PIN data[59]
    DIRECTION INPUT ;
    USE SIGNAL ;
    PORT
      LAYER M4 ;
        RECT  0 67.728 0.084 67.752 ;
    END
  END data[59]
  PIN data[5]
    DIRECTION INPUT ;
    USE SIGNAL ;
    PORT
      LAYER M4 ;
        RECT  0 53.328 0.084 53.352 ;
    END
  END data[5]
  PIN data[60]
    DIRECTION INPUT ;
    USE SIGNAL ;
    PORT
      LAYER M4 ;
        RECT  0 67.824 0.084 67.848 ;
    END
  END data[60]
  PIN data[61]
    DIRECTION INPUT ;
    USE SIGNAL ;
    PORT
      LAYER M4 ;
        RECT  0 67.92 0.084 67.944 ;
    END
  END data[61]
  PIN data[62]
    DIRECTION INPUT ;
    USE SIGNAL ;
    PORT
      LAYER M4 ;
        RECT  0 68.016 0.084 68.04 ;
    END
  END data[62]
  PIN data[63]
    DIRECTION INPUT ;
    USE SIGNAL ;
    PORT
      LAYER M4 ;
        RECT  0 68.112 0.084 68.136 ;
    END
  END data[63]
  PIN data[64]
    DIRECTION INPUT ;
    USE SIGNAL ;
    PORT
      LAYER M4 ;
        RECT  0 55.92 0.084 55.944 ;
    END
  END data[64]
  PIN data[65]
    DIRECTION INPUT ;
    USE SIGNAL ;
    PORT
      LAYER M4 ;
        RECT  0 56.016 0.084 56.04 ;
    END
  END data[65]
  PIN data[66]
    DIRECTION INPUT ;
    USE SIGNAL ;
    PORT
      LAYER M4 ;
        RECT  0 56.112 0.084 56.136 ;
    END
  END data[66]
  PIN data[67]
    DIRECTION INPUT ;
    USE SIGNAL ;
    PORT
      LAYER M4 ;
        RECT  0 56.208 0.084 56.232 ;
    END
  END data[67]
  PIN data[68]
    DIRECTION INPUT ;
    USE SIGNAL ;
    PORT
      LAYER M4 ;
        RECT  0 56.304 0.084 56.328 ;
    END
  END data[68]
  PIN data[69]
    DIRECTION INPUT ;
    USE SIGNAL ;
    PORT
      LAYER M4 ;
        RECT  0 56.4 0.084 56.424 ;
    END
  END data[69]
  PIN data[6]
    DIRECTION INPUT ;
    USE SIGNAL ;
    PORT
      LAYER M4 ;
        RECT  0 53.424 0.084 53.448 ;
    END
  END data[6]
  PIN data[70]
    DIRECTION INPUT ;
    USE SIGNAL ;
    PORT
      LAYER M4 ;
        RECT  0 56.496 0.084 56.52 ;
    END
  END data[70]
  PIN data[71]
    DIRECTION INPUT ;
    USE SIGNAL ;
    PORT
      LAYER M4 ;
        RECT  0 56.592 0.084 56.616 ;
    END
  END data[71]
  PIN data[72]
    DIRECTION INPUT ;
    USE SIGNAL ;
    PORT
      LAYER M4 ;
        RECT  0 56.688 0.084 56.712 ;
    END
  END data[72]
  PIN data[73]
    DIRECTION INPUT ;
    USE SIGNAL ;
    PORT
      LAYER M4 ;
        RECT  0 56.784 0.084 56.808 ;
    END
  END data[73]
  PIN data[74]
    DIRECTION INPUT ;
    USE SIGNAL ;
    PORT
      LAYER M4 ;
        RECT  0 56.88 0.084 56.904 ;
    END
  END data[74]
  PIN data[75]
    DIRECTION INPUT ;
    USE SIGNAL ;
    PORT
      LAYER M4 ;
        RECT  0 56.976 0.084 57 ;
    END
  END data[75]
  PIN data[76]
    DIRECTION INPUT ;
    USE SIGNAL ;
    PORT
      LAYER M4 ;
        RECT  0 57.072 0.084 57.096 ;
    END
  END data[76]
  PIN data[77]
    DIRECTION INPUT ;
    USE SIGNAL ;
    PORT
      LAYER M4 ;
        RECT  0 57.168 0.084 57.192 ;
    END
  END data[77]
  PIN data[78]
    DIRECTION INPUT ;
    USE SIGNAL ;
    PORT
      LAYER M4 ;
        RECT  0 57.264 0.084 57.288 ;
    END
  END data[78]
  PIN data[79]
    DIRECTION INPUT ;
    USE SIGNAL ;
    PORT
      LAYER M4 ;
        RECT  0 57.36 0.084 57.384 ;
    END
  END data[79]
  PIN data[7]
    DIRECTION INPUT ;
    USE SIGNAL ;
    PORT
      LAYER M4 ;
        RECT  0 53.52 0.084 53.544 ;
    END
  END data[7]
  PIN data[80]
    DIRECTION INPUT ;
    USE SIGNAL ;
    PORT
      LAYER M4 ;
        RECT  0 57.456 0.084 57.48 ;
    END
  END data[80]
  PIN data[81]
    DIRECTION INPUT ;
    USE SIGNAL ;
    PORT
      LAYER M4 ;
        RECT  0 57.552 0.084 57.576 ;
    END
  END data[81]
  PIN data[82]
    DIRECTION INPUT ;
    USE SIGNAL ;
    PORT
      LAYER M4 ;
        RECT  0 57.648 0.084 57.672 ;
    END
  END data[82]
  PIN data[83]
    DIRECTION INPUT ;
    USE SIGNAL ;
    PORT
      LAYER M4 ;
        RECT  0 57.744 0.084 57.768 ;
    END
  END data[83]
  PIN data[84]
    DIRECTION INPUT ;
    USE SIGNAL ;
    PORT
      LAYER M4 ;
        RECT  0 57.84 0.084 57.864 ;
    END
  END data[84]
  PIN data[85]
    DIRECTION INPUT ;
    USE SIGNAL ;
    PORT
      LAYER M4 ;
        RECT  0 57.936 0.084 57.96 ;
    END
  END data[85]
  PIN data[86]
    DIRECTION INPUT ;
    USE SIGNAL ;
    PORT
      LAYER M4 ;
        RECT  0 58.032 0.084 58.056 ;
    END
  END data[86]
  PIN data[87]
    DIRECTION INPUT ;
    USE SIGNAL ;
    PORT
      LAYER M4 ;
        RECT  0 58.128 0.084 58.152 ;
    END
  END data[87]
  PIN data[88]
    DIRECTION INPUT ;
    USE SIGNAL ;
    PORT
      LAYER M4 ;
        RECT  0 58.224 0.084 58.248 ;
    END
  END data[88]
  PIN data[89]
    DIRECTION INPUT ;
    USE SIGNAL ;
    PORT
      LAYER M4 ;
        RECT  0 58.32 0.084 58.344 ;
    END
  END data[89]
  PIN data[8]
    DIRECTION INPUT ;
    USE SIGNAL ;
    PORT
      LAYER M4 ;
        RECT  0 53.616 0.084 53.64 ;
    END
  END data[8]
  PIN data[90]
    DIRECTION INPUT ;
    USE SIGNAL ;
    PORT
      LAYER M4 ;
        RECT  0 58.416 0.084 58.44 ;
    END
  END data[90]
  PIN data[91]
    DIRECTION INPUT ;
    USE SIGNAL ;
    PORT
      LAYER M4 ;
        RECT  0 58.512 0.084 58.536 ;
    END
  END data[91]
  PIN data[92]
    DIRECTION INPUT ;
    USE SIGNAL ;
    PORT
      LAYER M4 ;
        RECT  0 58.608 0.084 58.632 ;
    END
  END data[92]
  PIN data[93]
    DIRECTION INPUT ;
    USE SIGNAL ;
    PORT
      LAYER M4 ;
        RECT  0 58.704 0.084 58.728 ;
    END
  END data[93]
  PIN data[94]
    DIRECTION INPUT ;
    USE SIGNAL ;
    PORT
      LAYER M4 ;
        RECT  0 58.8 0.084 58.824 ;
    END
  END data[94]
  PIN data[95]
    DIRECTION INPUT ;
    USE SIGNAL ;
    PORT
      LAYER M4 ;
        RECT  0 58.896 0.084 58.92 ;
    END
  END data[95]
  PIN data[96]
    DIRECTION INPUT ;
    USE SIGNAL ;
    PORT
      LAYER M4 ;
        RECT  0 68.208 0.084 68.232 ;
    END
  END data[96]
  PIN data[97]
    DIRECTION INPUT ;
    USE SIGNAL ;
    PORT
      LAYER M4 ;
        RECT  0 68.304 0.084 68.328 ;
    END
  END data[97]
  PIN data[98]
    DIRECTION INPUT ;
    USE SIGNAL ;
    PORT
      LAYER M4 ;
        RECT  0 68.4 0.084 68.424 ;
    END
  END data[98]
  PIN data[99]
    DIRECTION INPUT ;
    USE SIGNAL ;
    PORT
      LAYER M4 ;
        RECT  0 68.496 0.084 68.52 ;
    END
  END data[99]
  PIN data[9]
    DIRECTION INPUT ;
    USE SIGNAL ;
    PORT
      LAYER M4 ;
        RECT  0 53.712 0.084 53.736 ;
    END
  END data[9]
  PIN pin_data[0]
    DIRECTION OUTPUT ;
    USE SIGNAL ;
    PORT
      LAYER M4 ;
        RECT  43.116 58.32 43.2 58.344 ;
    END
  END pin_data[0]
  PIN pin_data[100]
    DIRECTION OUTPUT ;
    USE SIGNAL ;
    PORT
      LAYER M4 ;
        RECT  43.116 74.064 43.2 74.088 ;
    END
  END pin_data[100]
  PIN pin_data[101]
    DIRECTION OUTPUT ;
    USE SIGNAL ;
    PORT
      LAYER M4 ;
        RECT  43.116 74.16 43.2 74.184 ;
    END
  END pin_data[101]
  PIN pin_data[102]
    DIRECTION OUTPUT ;
    USE SIGNAL ;
    PORT
      LAYER M4 ;
        RECT  43.116 74.256 43.2 74.28 ;
    END
  END pin_data[102]
  PIN pin_data[103]
    DIRECTION OUTPUT ;
    USE SIGNAL ;
    PORT
      LAYER M4 ;
        RECT  43.116 74.352 43.2 74.376 ;
    END
  END pin_data[103]
  PIN pin_data[104]
    DIRECTION OUTPUT ;
    USE SIGNAL ;
    PORT
      LAYER M4 ;
        RECT  43.116 74.448 43.2 74.472 ;
    END
  END pin_data[104]
  PIN pin_data[105]
    DIRECTION OUTPUT ;
    USE SIGNAL ;
    PORT
      LAYER M4 ;
        RECT  43.116 74.544 43.2 74.568 ;
    END
  END pin_data[105]
  PIN pin_data[106]
    DIRECTION OUTPUT ;
    USE SIGNAL ;
    PORT
      LAYER M4 ;
        RECT  43.116 74.64 43.2 74.664 ;
    END
  END pin_data[106]
  PIN pin_data[107]
    DIRECTION OUTPUT ;
    USE SIGNAL ;
    PORT
      LAYER M4 ;
        RECT  43.116 74.736 43.2 74.76 ;
    END
  END pin_data[107]
  PIN pin_data[108]
    DIRECTION OUTPUT ;
    USE SIGNAL ;
    PORT
      LAYER M4 ;
        RECT  43.116 74.832 43.2 74.856 ;
    END
  END pin_data[108]
  PIN pin_data[109]
    DIRECTION OUTPUT ;
    USE SIGNAL ;
    PORT
      LAYER M4 ;
        RECT  43.116 74.928 43.2 74.952 ;
    END
  END pin_data[109]
  PIN pin_data[10]
    DIRECTION OUTPUT ;
    USE SIGNAL ;
    PORT
      LAYER M4 ;
        RECT  43.116 59.28 43.2 59.304 ;
    END
  END pin_data[10]
  PIN pin_data[110]
    DIRECTION OUTPUT ;
    USE SIGNAL ;
    PORT
      LAYER M4 ;
        RECT  43.116 75.024 43.2 75.048 ;
    END
  END pin_data[110]
  PIN pin_data[111]
    DIRECTION OUTPUT ;
    USE SIGNAL ;
    PORT
      LAYER M4 ;
        RECT  43.116 75.12 43.2 75.144 ;
    END
  END pin_data[111]
  PIN pin_data[112]
    DIRECTION OUTPUT ;
    USE SIGNAL ;
    PORT
      LAYER M4 ;
        RECT  43.116 75.216 43.2 75.24 ;
    END
  END pin_data[112]
  PIN pin_data[113]
    DIRECTION OUTPUT ;
    USE SIGNAL ;
    PORT
      LAYER M4 ;
        RECT  43.116 75.312 43.2 75.336 ;
    END
  END pin_data[113]
  PIN pin_data[114]
    DIRECTION OUTPUT ;
    USE SIGNAL ;
    PORT
      LAYER M4 ;
        RECT  43.116 75.408 43.2 75.432 ;
    END
  END pin_data[114]
  PIN pin_data[115]
    DIRECTION OUTPUT ;
    USE SIGNAL ;
    PORT
      LAYER M4 ;
        RECT  43.116 75.504 43.2 75.528 ;
    END
  END pin_data[115]
  PIN pin_data[116]
    DIRECTION OUTPUT ;
    USE SIGNAL ;
    PORT
      LAYER M4 ;
        RECT  43.116 75.6 43.2 75.624 ;
    END
  END pin_data[116]
  PIN pin_data[117]
    DIRECTION OUTPUT ;
    USE SIGNAL ;
    PORT
      LAYER M4 ;
        RECT  43.116 75.696 43.2 75.72 ;
    END
  END pin_data[117]
  PIN pin_data[118]
    DIRECTION OUTPUT ;
    USE SIGNAL ;
    PORT
      LAYER M4 ;
        RECT  43.116 75.792 43.2 75.816 ;
    END
  END pin_data[118]
  PIN pin_data[119]
    DIRECTION OUTPUT ;
    USE SIGNAL ;
    PORT
      LAYER M4 ;
        RECT  43.116 75.888 43.2 75.912 ;
    END
  END pin_data[119]
  PIN pin_data[11]
    DIRECTION OUTPUT ;
    USE SIGNAL ;
    PORT
      LAYER M4 ;
        RECT  43.116 59.376 43.2 59.4 ;
    END
  END pin_data[11]
  PIN pin_data[120]
    DIRECTION OUTPUT ;
    USE SIGNAL ;
    PORT
      LAYER M4 ;
        RECT  43.116 75.984 43.2 76.008 ;
    END
  END pin_data[120]
  PIN pin_data[121]
    DIRECTION OUTPUT ;
    USE SIGNAL ;
    PORT
      LAYER M4 ;
        RECT  43.116 76.08 43.2 76.104 ;
    END
  END pin_data[121]
  PIN pin_data[122]
    DIRECTION OUTPUT ;
    USE SIGNAL ;
    PORT
      LAYER M4 ;
        RECT  43.116 76.176 43.2 76.2 ;
    END
  END pin_data[122]
  PIN pin_data[123]
    DIRECTION OUTPUT ;
    USE SIGNAL ;
    PORT
      LAYER M4 ;
        RECT  43.116 76.272 43.2 76.296 ;
    END
  END pin_data[123]
  PIN pin_data[124]
    DIRECTION OUTPUT ;
    USE SIGNAL ;
    PORT
      LAYER M4 ;
        RECT  43.116 76.368 43.2 76.392 ;
    END
  END pin_data[124]
  PIN pin_data[125]
    DIRECTION OUTPUT ;
    USE SIGNAL ;
    PORT
      LAYER M4 ;
        RECT  43.116 76.464 43.2 76.488 ;
    END
  END pin_data[125]
  PIN pin_data[126]
    DIRECTION OUTPUT ;
    USE SIGNAL ;
    PORT
      LAYER M4 ;
        RECT  43.116 76.56 43.2 76.584 ;
    END
  END pin_data[126]
  PIN pin_data[127]
    DIRECTION OUTPUT ;
    USE SIGNAL ;
    PORT
      LAYER M4 ;
        RECT  43.116 76.656 43.2 76.68 ;
    END
  END pin_data[127]
  PIN pin_data[128]
    DIRECTION OUTPUT ;
    USE SIGNAL ;
    PORT
      LAYER M4 ;
        RECT  43.116 61.392 43.2 61.416 ;
    END
  END pin_data[128]
  PIN pin_data[129]
    DIRECTION OUTPUT ;
    USE SIGNAL ;
    PORT
      LAYER M4 ;
        RECT  43.116 61.488 43.2 61.512 ;
    END
  END pin_data[129]
  PIN pin_data[12]
    DIRECTION OUTPUT ;
    USE SIGNAL ;
    PORT
      LAYER M4 ;
        RECT  43.116 59.472 43.2 59.496 ;
    END
  END pin_data[12]
  PIN pin_data[130]
    DIRECTION OUTPUT ;
    USE SIGNAL ;
    PORT
      LAYER M4 ;
        RECT  43.116 61.584 43.2 61.608 ;
    END
  END pin_data[130]
  PIN pin_data[131]
    DIRECTION OUTPUT ;
    USE SIGNAL ;
    PORT
      LAYER M4 ;
        RECT  43.116 61.68 43.2 61.704 ;
    END
  END pin_data[131]
  PIN pin_data[132]
    DIRECTION OUTPUT ;
    USE SIGNAL ;
    PORT
      LAYER M4 ;
        RECT  43.116 61.776 43.2 61.8 ;
    END
  END pin_data[132]
  PIN pin_data[133]
    DIRECTION OUTPUT ;
    USE SIGNAL ;
    PORT
      LAYER M4 ;
        RECT  43.116 61.872 43.2 61.896 ;
    END
  END pin_data[133]
  PIN pin_data[134]
    DIRECTION OUTPUT ;
    USE SIGNAL ;
    PORT
      LAYER M4 ;
        RECT  43.116 61.968 43.2 61.992 ;
    END
  END pin_data[134]
  PIN pin_data[135]
    DIRECTION OUTPUT ;
    USE SIGNAL ;
    PORT
      LAYER M4 ;
        RECT  43.116 62.064 43.2 62.088 ;
    END
  END pin_data[135]
  PIN pin_data[136]
    DIRECTION OUTPUT ;
    USE SIGNAL ;
    PORT
      LAYER M4 ;
        RECT  43.116 62.16 43.2 62.184 ;
    END
  END pin_data[136]
  PIN pin_data[137]
    DIRECTION OUTPUT ;
    USE SIGNAL ;
    PORT
      LAYER M4 ;
        RECT  43.116 62.256 43.2 62.28 ;
    END
  END pin_data[137]
  PIN pin_data[138]
    DIRECTION OUTPUT ;
    USE SIGNAL ;
    PORT
      LAYER M4 ;
        RECT  43.116 62.352 43.2 62.376 ;
    END
  END pin_data[138]
  PIN pin_data[139]
    DIRECTION OUTPUT ;
    USE SIGNAL ;
    PORT
      LAYER M4 ;
        RECT  43.116 62.448 43.2 62.472 ;
    END
  END pin_data[139]
  PIN pin_data[13]
    DIRECTION OUTPUT ;
    USE SIGNAL ;
    PORT
      LAYER M4 ;
        RECT  43.116 59.568 43.2 59.592 ;
    END
  END pin_data[13]
  PIN pin_data[140]
    DIRECTION OUTPUT ;
    USE SIGNAL ;
    PORT
      LAYER M4 ;
        RECT  43.116 62.544 43.2 62.568 ;
    END
  END pin_data[140]
  PIN pin_data[141]
    DIRECTION OUTPUT ;
    USE SIGNAL ;
    PORT
      LAYER M4 ;
        RECT  43.116 62.64 43.2 62.664 ;
    END
  END pin_data[141]
  PIN pin_data[142]
    DIRECTION OUTPUT ;
    USE SIGNAL ;
    PORT
      LAYER M4 ;
        RECT  43.116 62.736 43.2 62.76 ;
    END
  END pin_data[142]
  PIN pin_data[143]
    DIRECTION OUTPUT ;
    USE SIGNAL ;
    PORT
      LAYER M4 ;
        RECT  43.116 62.832 43.2 62.856 ;
    END
  END pin_data[143]
  PIN pin_data[144]
    DIRECTION OUTPUT ;
    USE SIGNAL ;
    PORT
      LAYER M4 ;
        RECT  43.116 62.928 43.2 62.952 ;
    END
  END pin_data[144]
  PIN pin_data[145]
    DIRECTION OUTPUT ;
    USE SIGNAL ;
    PORT
      LAYER M4 ;
        RECT  43.116 63.024 43.2 63.048 ;
    END
  END pin_data[145]
  PIN pin_data[146]
    DIRECTION OUTPUT ;
    USE SIGNAL ;
    PORT
      LAYER M4 ;
        RECT  43.116 63.12 43.2 63.144 ;
    END
  END pin_data[146]
  PIN pin_data[147]
    DIRECTION OUTPUT ;
    USE SIGNAL ;
    PORT
      LAYER M4 ;
        RECT  43.116 63.216 43.2 63.24 ;
    END
  END pin_data[147]
  PIN pin_data[148]
    DIRECTION OUTPUT ;
    USE SIGNAL ;
    PORT
      LAYER M4 ;
        RECT  43.116 63.312 43.2 63.336 ;
    END
  END pin_data[148]
  PIN pin_data[149]
    DIRECTION OUTPUT ;
    USE SIGNAL ;
    PORT
      LAYER M4 ;
        RECT  43.116 63.408 43.2 63.432 ;
    END
  END pin_data[149]
  PIN pin_data[14]
    DIRECTION OUTPUT ;
    USE SIGNAL ;
    PORT
      LAYER M4 ;
        RECT  43.116 59.664 43.2 59.688 ;
    END
  END pin_data[14]
  PIN pin_data[150]
    DIRECTION OUTPUT ;
    USE SIGNAL ;
    PORT
      LAYER M4 ;
        RECT  43.116 63.504 43.2 63.528 ;
    END
  END pin_data[150]
  PIN pin_data[151]
    DIRECTION OUTPUT ;
    USE SIGNAL ;
    PORT
      LAYER M4 ;
        RECT  43.116 63.6 43.2 63.624 ;
    END
  END pin_data[151]
  PIN pin_data[152]
    DIRECTION OUTPUT ;
    USE SIGNAL ;
    PORT
      LAYER M4 ;
        RECT  43.116 63.696 43.2 63.72 ;
    END
  END pin_data[152]
  PIN pin_data[153]
    DIRECTION OUTPUT ;
    USE SIGNAL ;
    PORT
      LAYER M4 ;
        RECT  43.116 63.792 43.2 63.816 ;
    END
  END pin_data[153]
  PIN pin_data[154]
    DIRECTION OUTPUT ;
    USE SIGNAL ;
    PORT
      LAYER M4 ;
        RECT  43.116 63.888 43.2 63.912 ;
    END
  END pin_data[154]
  PIN pin_data[155]
    DIRECTION OUTPUT ;
    USE SIGNAL ;
    PORT
      LAYER M4 ;
        RECT  43.116 63.984 43.2 64.008 ;
    END
  END pin_data[155]
  PIN pin_data[156]
    DIRECTION OUTPUT ;
    USE SIGNAL ;
    PORT
      LAYER M4 ;
        RECT  43.116 64.08 43.2 64.104 ;
    END
  END pin_data[156]
  PIN pin_data[157]
    DIRECTION OUTPUT ;
    USE SIGNAL ;
    PORT
      LAYER M4 ;
        RECT  43.116 64.176 43.2 64.2 ;
    END
  END pin_data[157]
  PIN pin_data[158]
    DIRECTION OUTPUT ;
    USE SIGNAL ;
    PORT
      LAYER M4 ;
        RECT  43.116 64.272 43.2 64.296 ;
    END
  END pin_data[158]
  PIN pin_data[159]
    DIRECTION OUTPUT ;
    USE SIGNAL ;
    PORT
      LAYER M4 ;
        RECT  43.116 64.368 43.2 64.392 ;
    END
  END pin_data[159]
  PIN pin_data[15]
    DIRECTION OUTPUT ;
    USE SIGNAL ;
    PORT
      LAYER M4 ;
        RECT  43.116 59.76 43.2 59.784 ;
    END
  END pin_data[15]
  PIN pin_data[160]
    DIRECTION OUTPUT ;
    USE SIGNAL ;
    PORT
      LAYER M4 ;
        RECT  43.116 67.536 43.2 67.56 ;
    END
  END pin_data[160]
  PIN pin_data[161]
    DIRECTION OUTPUT ;
    USE SIGNAL ;
    PORT
      LAYER M4 ;
        RECT  43.116 67.632 43.2 67.656 ;
    END
  END pin_data[161]
  PIN pin_data[162]
    DIRECTION OUTPUT ;
    USE SIGNAL ;
    PORT
      LAYER M4 ;
        RECT  43.116 67.728 43.2 67.752 ;
    END
  END pin_data[162]
  PIN pin_data[163]
    DIRECTION OUTPUT ;
    USE SIGNAL ;
    PORT
      LAYER M4 ;
        RECT  43.116 67.824 43.2 67.848 ;
    END
  END pin_data[163]
  PIN pin_data[164]
    DIRECTION OUTPUT ;
    USE SIGNAL ;
    PORT
      LAYER M4 ;
        RECT  43.116 67.92 43.2 67.944 ;
    END
  END pin_data[164]
  PIN pin_data[165]
    DIRECTION OUTPUT ;
    USE SIGNAL ;
    PORT
      LAYER M4 ;
        RECT  43.116 68.016 43.2 68.04 ;
    END
  END pin_data[165]
  PIN pin_data[166]
    DIRECTION OUTPUT ;
    USE SIGNAL ;
    PORT
      LAYER M4 ;
        RECT  43.116 68.112 43.2 68.136 ;
    END
  END pin_data[166]
  PIN pin_data[167]
    DIRECTION OUTPUT ;
    USE SIGNAL ;
    PORT
      LAYER M4 ;
        RECT  43.116 68.208 43.2 68.232 ;
    END
  END pin_data[167]
  PIN pin_data[168]
    DIRECTION OUTPUT ;
    USE SIGNAL ;
    PORT
      LAYER M4 ;
        RECT  43.116 68.304 43.2 68.328 ;
    END
  END pin_data[168]
  PIN pin_data[169]
    DIRECTION OUTPUT ;
    USE SIGNAL ;
    PORT
      LAYER M4 ;
        RECT  43.116 68.4 43.2 68.424 ;
    END
  END pin_data[169]
  PIN pin_data[16]
    DIRECTION OUTPUT ;
    USE SIGNAL ;
    PORT
      LAYER M4 ;
        RECT  43.116 59.856 43.2 59.88 ;
    END
  END pin_data[16]
  PIN pin_data[170]
    DIRECTION OUTPUT ;
    USE SIGNAL ;
    PORT
      LAYER M4 ;
        RECT  43.116 68.496 43.2 68.52 ;
    END
  END pin_data[170]
  PIN pin_data[171]
    DIRECTION OUTPUT ;
    USE SIGNAL ;
    PORT
      LAYER M4 ;
        RECT  43.116 68.592 43.2 68.616 ;
    END
  END pin_data[171]
  PIN pin_data[172]
    DIRECTION OUTPUT ;
    USE SIGNAL ;
    PORT
      LAYER M4 ;
        RECT  43.116 68.688 43.2 68.712 ;
    END
  END pin_data[172]
  PIN pin_data[173]
    DIRECTION OUTPUT ;
    USE SIGNAL ;
    PORT
      LAYER M4 ;
        RECT  43.116 68.784 43.2 68.808 ;
    END
  END pin_data[173]
  PIN pin_data[174]
    DIRECTION OUTPUT ;
    USE SIGNAL ;
    PORT
      LAYER M4 ;
        RECT  43.116 68.88 43.2 68.904 ;
    END
  END pin_data[174]
  PIN pin_data[175]
    DIRECTION OUTPUT ;
    USE SIGNAL ;
    PORT
      LAYER M4 ;
        RECT  43.116 68.976 43.2 69 ;
    END
  END pin_data[175]
  PIN pin_data[176]
    DIRECTION OUTPUT ;
    USE SIGNAL ;
    PORT
      LAYER M4 ;
        RECT  43.116 69.072 43.2 69.096 ;
    END
  END pin_data[176]
  PIN pin_data[177]
    DIRECTION OUTPUT ;
    USE SIGNAL ;
    PORT
      LAYER M4 ;
        RECT  43.116 69.168 43.2 69.192 ;
    END
  END pin_data[177]
  PIN pin_data[178]
    DIRECTION OUTPUT ;
    USE SIGNAL ;
    PORT
      LAYER M4 ;
        RECT  43.116 69.264 43.2 69.288 ;
    END
  END pin_data[178]
  PIN pin_data[179]
    DIRECTION OUTPUT ;
    USE SIGNAL ;
    PORT
      LAYER M4 ;
        RECT  43.116 69.36 43.2 69.384 ;
    END
  END pin_data[179]
  PIN pin_data[17]
    DIRECTION OUTPUT ;
    USE SIGNAL ;
    PORT
      LAYER M4 ;
        RECT  43.116 59.952 43.2 59.976 ;
    END
  END pin_data[17]
  PIN pin_data[180]
    DIRECTION OUTPUT ;
    USE SIGNAL ;
    PORT
      LAYER M4 ;
        RECT  43.116 69.456 43.2 69.48 ;
    END
  END pin_data[180]
  PIN pin_data[181]
    DIRECTION OUTPUT ;
    USE SIGNAL ;
    PORT
      LAYER M4 ;
        RECT  43.116 69.552 43.2 69.576 ;
    END
  END pin_data[181]
  PIN pin_data[182]
    DIRECTION OUTPUT ;
    USE SIGNAL ;
    PORT
      LAYER M4 ;
        RECT  43.116 69.648 43.2 69.672 ;
    END
  END pin_data[182]
  PIN pin_data[183]
    DIRECTION OUTPUT ;
    USE SIGNAL ;
    PORT
      LAYER M4 ;
        RECT  43.116 69.744 43.2 69.768 ;
    END
  END pin_data[183]
  PIN pin_data[184]
    DIRECTION OUTPUT ;
    USE SIGNAL ;
    PORT
      LAYER M4 ;
        RECT  43.116 69.84 43.2 69.864 ;
    END
  END pin_data[184]
  PIN pin_data[185]
    DIRECTION OUTPUT ;
    USE SIGNAL ;
    PORT
      LAYER M4 ;
        RECT  43.116 69.936 43.2 69.96 ;
    END
  END pin_data[185]
  PIN pin_data[186]
    DIRECTION OUTPUT ;
    USE SIGNAL ;
    PORT
      LAYER M4 ;
        RECT  43.116 70.032 43.2 70.056 ;
    END
  END pin_data[186]
  PIN pin_data[187]
    DIRECTION OUTPUT ;
    USE SIGNAL ;
    PORT
      LAYER M4 ;
        RECT  43.116 70.128 43.2 70.152 ;
    END
  END pin_data[187]
  PIN pin_data[188]
    DIRECTION OUTPUT ;
    USE SIGNAL ;
    PORT
      LAYER M4 ;
        RECT  43.116 70.224 43.2 70.248 ;
    END
  END pin_data[188]
  PIN pin_data[189]
    DIRECTION OUTPUT ;
    USE SIGNAL ;
    PORT
      LAYER M4 ;
        RECT  43.116 70.32 43.2 70.344 ;
    END
  END pin_data[189]
  PIN pin_data[18]
    DIRECTION OUTPUT ;
    USE SIGNAL ;
    PORT
      LAYER M4 ;
        RECT  43.116 60.048 43.2 60.072 ;
    END
  END pin_data[18]
  PIN pin_data[190]
    DIRECTION OUTPUT ;
    USE SIGNAL ;
    PORT
      LAYER M4 ;
        RECT  43.116 70.416 43.2 70.44 ;
    END
  END pin_data[190]
  PIN pin_data[191]
    DIRECTION OUTPUT ;
    USE SIGNAL ;
    PORT
      LAYER M4 ;
        RECT  43.116 70.512 43.2 70.536 ;
    END
  END pin_data[191]
  PIN pin_data[192]
    DIRECTION OUTPUT ;
    USE SIGNAL ;
    PORT
      LAYER M4 ;
        RECT  43.116 45.264 43.2 45.288 ;
    END
  END pin_data[192]
  PIN pin_data[193]
    DIRECTION OUTPUT ;
    USE SIGNAL ;
    PORT
      LAYER M4 ;
        RECT  43.116 45.36 43.2 45.384 ;
    END
  END pin_data[193]
  PIN pin_data[194]
    DIRECTION OUTPUT ;
    USE SIGNAL ;
    PORT
      LAYER M4 ;
        RECT  43.116 45.456 43.2 45.48 ;
    END
  END pin_data[194]
  PIN pin_data[195]
    DIRECTION OUTPUT ;
    USE SIGNAL ;
    PORT
      LAYER M4 ;
        RECT  43.116 45.552 43.2 45.576 ;
    END
  END pin_data[195]
  PIN pin_data[196]
    DIRECTION OUTPUT ;
    USE SIGNAL ;
    PORT
      LAYER M4 ;
        RECT  43.116 45.648 43.2 45.672 ;
    END
  END pin_data[196]
  PIN pin_data[197]
    DIRECTION OUTPUT ;
    USE SIGNAL ;
    PORT
      LAYER M4 ;
        RECT  43.116 45.744 43.2 45.768 ;
    END
  END pin_data[197]
  PIN pin_data[198]
    DIRECTION OUTPUT ;
    USE SIGNAL ;
    PORT
      LAYER M4 ;
        RECT  43.116 45.84 43.2 45.864 ;
    END
  END pin_data[198]
  PIN pin_data[199]
    DIRECTION OUTPUT ;
    USE SIGNAL ;
    PORT
      LAYER M4 ;
        RECT  43.116 45.936 43.2 45.96 ;
    END
  END pin_data[199]
  PIN pin_data[19]
    DIRECTION OUTPUT ;
    USE SIGNAL ;
    PORT
      LAYER M4 ;
        RECT  43.116 60.144 43.2 60.168 ;
    END
  END pin_data[19]
  PIN pin_data[1]
    DIRECTION OUTPUT ;
    USE SIGNAL ;
    PORT
      LAYER M4 ;
        RECT  43.116 58.416 43.2 58.44 ;
    END
  END pin_data[1]
  PIN pin_data[200]
    DIRECTION OUTPUT ;
    USE SIGNAL ;
    PORT
      LAYER M4 ;
        RECT  43.116 46.032 43.2 46.056 ;
    END
  END pin_data[200]
  PIN pin_data[201]
    DIRECTION OUTPUT ;
    USE SIGNAL ;
    PORT
      LAYER M4 ;
        RECT  43.116 46.128 43.2 46.152 ;
    END
  END pin_data[201]
  PIN pin_data[202]
    DIRECTION OUTPUT ;
    USE SIGNAL ;
    PORT
      LAYER M4 ;
        RECT  43.116 46.224 43.2 46.248 ;
    END
  END pin_data[202]
  PIN pin_data[203]
    DIRECTION OUTPUT ;
    USE SIGNAL ;
    PORT
      LAYER M4 ;
        RECT  43.116 46.32 43.2 46.344 ;
    END
  END pin_data[203]
  PIN pin_data[204]
    DIRECTION OUTPUT ;
    USE SIGNAL ;
    PORT
      LAYER M4 ;
        RECT  43.116 46.416 43.2 46.44 ;
    END
  END pin_data[204]
  PIN pin_data[205]
    DIRECTION OUTPUT ;
    USE SIGNAL ;
    PORT
      LAYER M4 ;
        RECT  43.116 46.512 43.2 46.536 ;
    END
  END pin_data[205]
  PIN pin_data[206]
    DIRECTION OUTPUT ;
    USE SIGNAL ;
    PORT
      LAYER M4 ;
        RECT  43.116 46.608 43.2 46.632 ;
    END
  END pin_data[206]
  PIN pin_data[207]
    DIRECTION OUTPUT ;
    USE SIGNAL ;
    PORT
      LAYER M4 ;
        RECT  43.116 46.704 43.2 46.728 ;
    END
  END pin_data[207]
  PIN pin_data[208]
    DIRECTION OUTPUT ;
    USE SIGNAL ;
    PORT
      LAYER M4 ;
        RECT  43.116 46.8 43.2 46.824 ;
    END
  END pin_data[208]
  PIN pin_data[209]
    DIRECTION OUTPUT ;
    USE SIGNAL ;
    PORT
      LAYER M4 ;
        RECT  43.116 46.896 43.2 46.92 ;
    END
  END pin_data[209]
  PIN pin_data[20]
    DIRECTION OUTPUT ;
    USE SIGNAL ;
    PORT
      LAYER M4 ;
        RECT  43.116 60.24 43.2 60.264 ;
    END
  END pin_data[20]
  PIN pin_data[210]
    DIRECTION OUTPUT ;
    USE SIGNAL ;
    PORT
      LAYER M4 ;
        RECT  43.116 46.992 43.2 47.016 ;
    END
  END pin_data[210]
  PIN pin_data[211]
    DIRECTION OUTPUT ;
    USE SIGNAL ;
    PORT
      LAYER M4 ;
        RECT  43.116 47.088 43.2 47.112 ;
    END
  END pin_data[211]
  PIN pin_data[212]
    DIRECTION OUTPUT ;
    USE SIGNAL ;
    PORT
      LAYER M4 ;
        RECT  43.116 47.184 43.2 47.208 ;
    END
  END pin_data[212]
  PIN pin_data[213]
    DIRECTION OUTPUT ;
    USE SIGNAL ;
    PORT
      LAYER M4 ;
        RECT  43.116 47.28 43.2 47.304 ;
    END
  END pin_data[213]
  PIN pin_data[214]
    DIRECTION OUTPUT ;
    USE SIGNAL ;
    PORT
      LAYER M4 ;
        RECT  43.116 47.376 43.2 47.4 ;
    END
  END pin_data[214]
  PIN pin_data[215]
    DIRECTION OUTPUT ;
    USE SIGNAL ;
    PORT
      LAYER M4 ;
        RECT  43.116 47.472 43.2 47.496 ;
    END
  END pin_data[215]
  PIN pin_data[216]
    DIRECTION OUTPUT ;
    USE SIGNAL ;
    PORT
      LAYER M4 ;
        RECT  43.116 47.568 43.2 47.592 ;
    END
  END pin_data[216]
  PIN pin_data[217]
    DIRECTION OUTPUT ;
    USE SIGNAL ;
    PORT
      LAYER M4 ;
        RECT  43.116 47.664 43.2 47.688 ;
    END
  END pin_data[217]
  PIN pin_data[218]
    DIRECTION OUTPUT ;
    USE SIGNAL ;
    PORT
      LAYER M4 ;
        RECT  43.116 47.76 43.2 47.784 ;
    END
  END pin_data[218]
  PIN pin_data[219]
    DIRECTION OUTPUT ;
    USE SIGNAL ;
    PORT
      LAYER M4 ;
        RECT  43.116 47.856 43.2 47.88 ;
    END
  END pin_data[219]
  PIN pin_data[21]
    DIRECTION OUTPUT ;
    USE SIGNAL ;
    PORT
      LAYER M4 ;
        RECT  43.116 60.336 43.2 60.36 ;
    END
  END pin_data[21]
  PIN pin_data[220]
    DIRECTION OUTPUT ;
    USE SIGNAL ;
    PORT
      LAYER M4 ;
        RECT  43.116 47.952 43.2 47.976 ;
    END
  END pin_data[220]
  PIN pin_data[221]
    DIRECTION OUTPUT ;
    USE SIGNAL ;
    PORT
      LAYER M4 ;
        RECT  43.116 48.048 43.2 48.072 ;
    END
  END pin_data[221]
  PIN pin_data[222]
    DIRECTION OUTPUT ;
    USE SIGNAL ;
    PORT
      LAYER M4 ;
        RECT  43.116 48.144 43.2 48.168 ;
    END
  END pin_data[222]
  PIN pin_data[223]
    DIRECTION OUTPUT ;
    USE SIGNAL ;
    PORT
      LAYER M4 ;
        RECT  43.116 48.24 43.2 48.264 ;
    END
  END pin_data[223]
  PIN pin_data[224]
    DIRECTION OUTPUT ;
    USE SIGNAL ;
    PORT
      LAYER M4 ;
        RECT  43.116 51.408 43.2 51.432 ;
    END
  END pin_data[224]
  PIN pin_data[225]
    DIRECTION OUTPUT ;
    USE SIGNAL ;
    PORT
      LAYER M4 ;
        RECT  43.116 51.504 43.2 51.528 ;
    END
  END pin_data[225]
  PIN pin_data[226]
    DIRECTION OUTPUT ;
    USE SIGNAL ;
    PORT
      LAYER M4 ;
        RECT  43.116 51.6 43.2 51.624 ;
    END
  END pin_data[226]
  PIN pin_data[227]
    DIRECTION OUTPUT ;
    USE SIGNAL ;
    PORT
      LAYER M4 ;
        RECT  43.116 51.696 43.2 51.72 ;
    END
  END pin_data[227]
  PIN pin_data[228]
    DIRECTION OUTPUT ;
    USE SIGNAL ;
    PORT
      LAYER M4 ;
        RECT  43.116 51.792 43.2 51.816 ;
    END
  END pin_data[228]
  PIN pin_data[229]
    DIRECTION OUTPUT ;
    USE SIGNAL ;
    PORT
      LAYER M4 ;
        RECT  43.116 51.888 43.2 51.912 ;
    END
  END pin_data[229]
  PIN pin_data[22]
    DIRECTION OUTPUT ;
    USE SIGNAL ;
    PORT
      LAYER M4 ;
        RECT  43.116 60.432 43.2 60.456 ;
    END
  END pin_data[22]
  PIN pin_data[230]
    DIRECTION OUTPUT ;
    USE SIGNAL ;
    PORT
      LAYER M4 ;
        RECT  43.116 51.984 43.2 52.008 ;
    END
  END pin_data[230]
  PIN pin_data[231]
    DIRECTION OUTPUT ;
    USE SIGNAL ;
    PORT
      LAYER M4 ;
        RECT  43.116 52.08 43.2 52.104 ;
    END
  END pin_data[231]
  PIN pin_data[232]
    DIRECTION OUTPUT ;
    USE SIGNAL ;
    PORT
      LAYER M4 ;
        RECT  43.116 52.176 43.2 52.2 ;
    END
  END pin_data[232]
  PIN pin_data[233]
    DIRECTION OUTPUT ;
    USE SIGNAL ;
    PORT
      LAYER M4 ;
        RECT  43.116 52.272 43.2 52.296 ;
    END
  END pin_data[233]
  PIN pin_data[234]
    DIRECTION OUTPUT ;
    USE SIGNAL ;
    PORT
      LAYER M4 ;
        RECT  43.116 52.368 43.2 52.392 ;
    END
  END pin_data[234]
  PIN pin_data[235]
    DIRECTION OUTPUT ;
    USE SIGNAL ;
    PORT
      LAYER M4 ;
        RECT  43.116 52.464 43.2 52.488 ;
    END
  END pin_data[235]
  PIN pin_data[236]
    DIRECTION OUTPUT ;
    USE SIGNAL ;
    PORT
      LAYER M4 ;
        RECT  43.116 52.56 43.2 52.584 ;
    END
  END pin_data[236]
  PIN pin_data[237]
    DIRECTION OUTPUT ;
    USE SIGNAL ;
    PORT
      LAYER M4 ;
        RECT  43.116 52.656 43.2 52.68 ;
    END
  END pin_data[237]
  PIN pin_data[238]
    DIRECTION OUTPUT ;
    USE SIGNAL ;
    PORT
      LAYER M4 ;
        RECT  43.116 52.752 43.2 52.776 ;
    END
  END pin_data[238]
  PIN pin_data[239]
    DIRECTION OUTPUT ;
    USE SIGNAL ;
    PORT
      LAYER M4 ;
        RECT  43.116 52.848 43.2 52.872 ;
    END
  END pin_data[239]
  PIN pin_data[23]
    DIRECTION OUTPUT ;
    USE SIGNAL ;
    PORT
      LAYER M4 ;
        RECT  43.116 60.528 43.2 60.552 ;
    END
  END pin_data[23]
  PIN pin_data[240]
    DIRECTION OUTPUT ;
    USE SIGNAL ;
    PORT
      LAYER M4 ;
        RECT  43.116 52.944 43.2 52.968 ;
    END
  END pin_data[240]
  PIN pin_data[241]
    DIRECTION OUTPUT ;
    USE SIGNAL ;
    PORT
      LAYER M4 ;
        RECT  43.116 53.04 43.2 53.064 ;
    END
  END pin_data[241]
  PIN pin_data[242]
    DIRECTION OUTPUT ;
    USE SIGNAL ;
    PORT
      LAYER M4 ;
        RECT  43.116 53.136 43.2 53.16 ;
    END
  END pin_data[242]
  PIN pin_data[243]
    DIRECTION OUTPUT ;
    USE SIGNAL ;
    PORT
      LAYER M4 ;
        RECT  43.116 53.232 43.2 53.256 ;
    END
  END pin_data[243]
  PIN pin_data[244]
    DIRECTION OUTPUT ;
    USE SIGNAL ;
    PORT
      LAYER M4 ;
        RECT  43.116 53.328 43.2 53.352 ;
    END
  END pin_data[244]
  PIN pin_data[245]
    DIRECTION OUTPUT ;
    USE SIGNAL ;
    PORT
      LAYER M4 ;
        RECT  43.116 53.424 43.2 53.448 ;
    END
  END pin_data[245]
  PIN pin_data[246]
    DIRECTION OUTPUT ;
    USE SIGNAL ;
    PORT
      LAYER M4 ;
        RECT  43.116 53.52 43.2 53.544 ;
    END
  END pin_data[246]
  PIN pin_data[247]
    DIRECTION OUTPUT ;
    USE SIGNAL ;
    PORT
      LAYER M4 ;
        RECT  43.116 53.616 43.2 53.64 ;
    END
  END pin_data[247]
  PIN pin_data[248]
    DIRECTION OUTPUT ;
    USE SIGNAL ;
    PORT
      LAYER M4 ;
        RECT  43.116 53.712 43.2 53.736 ;
    END
  END pin_data[248]
  PIN pin_data[249]
    DIRECTION OUTPUT ;
    USE SIGNAL ;
    PORT
      LAYER M4 ;
        RECT  43.116 53.808 43.2 53.832 ;
    END
  END pin_data[249]
  PIN pin_data[24]
    DIRECTION OUTPUT ;
    USE SIGNAL ;
    PORT
      LAYER M4 ;
        RECT  43.116 60.624 43.2 60.648 ;
    END
  END pin_data[24]
  PIN pin_data[250]
    DIRECTION OUTPUT ;
    USE SIGNAL ;
    PORT
      LAYER M4 ;
        RECT  43.116 53.904 43.2 53.928 ;
    END
  END pin_data[250]
  PIN pin_data[251]
    DIRECTION OUTPUT ;
    USE SIGNAL ;
    PORT
      LAYER M4 ;
        RECT  43.116 54 43.2 54.024 ;
    END
  END pin_data[251]
  PIN pin_data[252]
    DIRECTION OUTPUT ;
    USE SIGNAL ;
    PORT
      LAYER M4 ;
        RECT  43.116 54.096 43.2 54.12 ;
    END
  END pin_data[252]
  PIN pin_data[253]
    DIRECTION OUTPUT ;
    USE SIGNAL ;
    PORT
      LAYER M4 ;
        RECT  43.116 54.192 43.2 54.216 ;
    END
  END pin_data[253]
  PIN pin_data[254]
    DIRECTION OUTPUT ;
    USE SIGNAL ;
    PORT
      LAYER M4 ;
        RECT  43.116 54.288 43.2 54.312 ;
    END
  END pin_data[254]
  PIN pin_data[255]
    DIRECTION OUTPUT ;
    USE SIGNAL ;
    PORT
      LAYER M4 ;
        RECT  43.116 54.384 43.2 54.408 ;
    END
  END pin_data[255]
  PIN pin_data[256]
    DIRECTION OUTPUT ;
    USE SIGNAL ;
    PORT
      LAYER M4 ;
        RECT  43.116 39.12 43.2 39.144 ;
    END
  END pin_data[256]
  PIN pin_data[257]
    DIRECTION OUTPUT ;
    USE SIGNAL ;
    PORT
      LAYER M4 ;
        RECT  43.116 39.216 43.2 39.24 ;
    END
  END pin_data[257]
  PIN pin_data[258]
    DIRECTION OUTPUT ;
    USE SIGNAL ;
    PORT
      LAYER M4 ;
        RECT  43.116 39.312 43.2 39.336 ;
    END
  END pin_data[258]
  PIN pin_data[259]
    DIRECTION OUTPUT ;
    USE SIGNAL ;
    PORT
      LAYER M4 ;
        RECT  43.116 39.408 43.2 39.432 ;
    END
  END pin_data[259]
  PIN pin_data[25]
    DIRECTION OUTPUT ;
    USE SIGNAL ;
    PORT
      LAYER M4 ;
        RECT  43.116 60.72 43.2 60.744 ;
    END
  END pin_data[25]
  PIN pin_data[260]
    DIRECTION OUTPUT ;
    USE SIGNAL ;
    PORT
      LAYER M4 ;
        RECT  43.116 39.504 43.2 39.528 ;
    END
  END pin_data[260]
  PIN pin_data[261]
    DIRECTION OUTPUT ;
    USE SIGNAL ;
    PORT
      LAYER M4 ;
        RECT  43.116 39.6 43.2 39.624 ;
    END
  END pin_data[261]
  PIN pin_data[262]
    DIRECTION OUTPUT ;
    USE SIGNAL ;
    PORT
      LAYER M4 ;
        RECT  43.116 39.696 43.2 39.72 ;
    END
  END pin_data[262]
  PIN pin_data[263]
    DIRECTION OUTPUT ;
    USE SIGNAL ;
    PORT
      LAYER M4 ;
        RECT  43.116 39.792 43.2 39.816 ;
    END
  END pin_data[263]
  PIN pin_data[264]
    DIRECTION OUTPUT ;
    USE SIGNAL ;
    PORT
      LAYER M4 ;
        RECT  43.116 39.888 43.2 39.912 ;
    END
  END pin_data[264]
  PIN pin_data[265]
    DIRECTION OUTPUT ;
    USE SIGNAL ;
    PORT
      LAYER M4 ;
        RECT  43.116 39.984 43.2 40.008 ;
    END
  END pin_data[265]
  PIN pin_data[266]
    DIRECTION OUTPUT ;
    USE SIGNAL ;
    PORT
      LAYER M4 ;
        RECT  43.116 40.08 43.2 40.104 ;
    END
  END pin_data[266]
  PIN pin_data[267]
    DIRECTION OUTPUT ;
    USE SIGNAL ;
    PORT
      LAYER M4 ;
        RECT  43.116 40.176 43.2 40.2 ;
    END
  END pin_data[267]
  PIN pin_data[268]
    DIRECTION OUTPUT ;
    USE SIGNAL ;
    PORT
      LAYER M4 ;
        RECT  43.116 40.272 43.2 40.296 ;
    END
  END pin_data[268]
  PIN pin_data[269]
    DIRECTION OUTPUT ;
    USE SIGNAL ;
    PORT
      LAYER M4 ;
        RECT  43.116 40.368 43.2 40.392 ;
    END
  END pin_data[269]
  PIN pin_data[26]
    DIRECTION OUTPUT ;
    USE SIGNAL ;
    PORT
      LAYER M4 ;
        RECT  43.116 60.816 43.2 60.84 ;
    END
  END pin_data[26]
  PIN pin_data[270]
    DIRECTION OUTPUT ;
    USE SIGNAL ;
    PORT
      LAYER M4 ;
        RECT  43.116 40.464 43.2 40.488 ;
    END
  END pin_data[270]
  PIN pin_data[271]
    DIRECTION OUTPUT ;
    USE SIGNAL ;
    PORT
      LAYER M4 ;
        RECT  43.116 40.56 43.2 40.584 ;
    END
  END pin_data[271]
  PIN pin_data[272]
    DIRECTION OUTPUT ;
    USE SIGNAL ;
    PORT
      LAYER M4 ;
        RECT  43.116 40.656 43.2 40.68 ;
    END
  END pin_data[272]
  PIN pin_data[273]
    DIRECTION OUTPUT ;
    USE SIGNAL ;
    PORT
      LAYER M4 ;
        RECT  43.116 40.752 43.2 40.776 ;
    END
  END pin_data[273]
  PIN pin_data[274]
    DIRECTION OUTPUT ;
    USE SIGNAL ;
    PORT
      LAYER M4 ;
        RECT  43.116 40.848 43.2 40.872 ;
    END
  END pin_data[274]
  PIN pin_data[275]
    DIRECTION OUTPUT ;
    USE SIGNAL ;
    PORT
      LAYER M4 ;
        RECT  43.116 40.944 43.2 40.968 ;
    END
  END pin_data[275]
  PIN pin_data[276]
    DIRECTION OUTPUT ;
    USE SIGNAL ;
    PORT
      LAYER M4 ;
        RECT  43.116 41.04 43.2 41.064 ;
    END
  END pin_data[276]
  PIN pin_data[277]
    DIRECTION OUTPUT ;
    USE SIGNAL ;
    PORT
      LAYER M4 ;
        RECT  43.116 41.136 43.2 41.16 ;
    END
  END pin_data[277]
  PIN pin_data[278]
    DIRECTION OUTPUT ;
    USE SIGNAL ;
    PORT
      LAYER M4 ;
        RECT  43.116 41.232 43.2 41.256 ;
    END
  END pin_data[278]
  PIN pin_data[279]
    DIRECTION OUTPUT ;
    USE SIGNAL ;
    PORT
      LAYER M4 ;
        RECT  43.116 41.328 43.2 41.352 ;
    END
  END pin_data[279]
  PIN pin_data[27]
    DIRECTION OUTPUT ;
    USE SIGNAL ;
    PORT
      LAYER M4 ;
        RECT  43.116 60.912 43.2 60.936 ;
    END
  END pin_data[27]
  PIN pin_data[280]
    DIRECTION OUTPUT ;
    USE SIGNAL ;
    PORT
      LAYER M4 ;
        RECT  43.116 41.424 43.2 41.448 ;
    END
  END pin_data[280]
  PIN pin_data[281]
    DIRECTION OUTPUT ;
    USE SIGNAL ;
    PORT
      LAYER M4 ;
        RECT  43.116 41.52 43.2 41.544 ;
    END
  END pin_data[281]
  PIN pin_data[282]
    DIRECTION OUTPUT ;
    USE SIGNAL ;
    PORT
      LAYER M4 ;
        RECT  43.116 41.616 43.2 41.64 ;
    END
  END pin_data[282]
  PIN pin_data[283]
    DIRECTION OUTPUT ;
    USE SIGNAL ;
    PORT
      LAYER M4 ;
        RECT  43.116 41.712 43.2 41.736 ;
    END
  END pin_data[283]
  PIN pin_data[284]
    DIRECTION OUTPUT ;
    USE SIGNAL ;
    PORT
      LAYER M4 ;
        RECT  43.116 41.808 43.2 41.832 ;
    END
  END pin_data[284]
  PIN pin_data[285]
    DIRECTION OUTPUT ;
    USE SIGNAL ;
    PORT
      LAYER M4 ;
        RECT  43.116 41.904 43.2 41.928 ;
    END
  END pin_data[285]
  PIN pin_data[286]
    DIRECTION OUTPUT ;
    USE SIGNAL ;
    PORT
      LAYER M4 ;
        RECT  43.116 42 43.2 42.024 ;
    END
  END pin_data[286]
  PIN pin_data[287]
    DIRECTION OUTPUT ;
    USE SIGNAL ;
    PORT
      LAYER M4 ;
        RECT  43.116 42.096 43.2 42.12 ;
    END
  END pin_data[287]
  PIN pin_data[288]
    DIRECTION OUTPUT ;
    USE SIGNAL ;
    PORT
      LAYER M4 ;
        RECT  43.116 48.336 43.2 48.36 ;
    END
  END pin_data[288]
  PIN pin_data[289]
    DIRECTION OUTPUT ;
    USE SIGNAL ;
    PORT
      LAYER M4 ;
        RECT  43.116 48.432 43.2 48.456 ;
    END
  END pin_data[289]
  PIN pin_data[28]
    DIRECTION OUTPUT ;
    USE SIGNAL ;
    PORT
      LAYER M4 ;
        RECT  43.116 61.008 43.2 61.032 ;
    END
  END pin_data[28]
  PIN pin_data[290]
    DIRECTION OUTPUT ;
    USE SIGNAL ;
    PORT
      LAYER M4 ;
        RECT  43.116 48.528 43.2 48.552 ;
    END
  END pin_data[290]
  PIN pin_data[291]
    DIRECTION OUTPUT ;
    USE SIGNAL ;
    PORT
      LAYER M4 ;
        RECT  43.116 48.624 43.2 48.648 ;
    END
  END pin_data[291]
  PIN pin_data[292]
    DIRECTION OUTPUT ;
    USE SIGNAL ;
    PORT
      LAYER M4 ;
        RECT  43.116 48.72 43.2 48.744 ;
    END
  END pin_data[292]
  PIN pin_data[293]
    DIRECTION OUTPUT ;
    USE SIGNAL ;
    PORT
      LAYER M4 ;
        RECT  43.116 48.816 43.2 48.84 ;
    END
  END pin_data[293]
  PIN pin_data[294]
    DIRECTION OUTPUT ;
    USE SIGNAL ;
    PORT
      LAYER M4 ;
        RECT  43.116 48.912 43.2 48.936 ;
    END
  END pin_data[294]
  PIN pin_data[295]
    DIRECTION OUTPUT ;
    USE SIGNAL ;
    PORT
      LAYER M4 ;
        RECT  43.116 49.008 43.2 49.032 ;
    END
  END pin_data[295]
  PIN pin_data[296]
    DIRECTION OUTPUT ;
    USE SIGNAL ;
    PORT
      LAYER M4 ;
        RECT  43.116 49.104 43.2 49.128 ;
    END
  END pin_data[296]
  PIN pin_data[297]
    DIRECTION OUTPUT ;
    USE SIGNAL ;
    PORT
      LAYER M4 ;
        RECT  43.116 49.2 43.2 49.224 ;
    END
  END pin_data[297]
  PIN pin_data[298]
    DIRECTION OUTPUT ;
    USE SIGNAL ;
    PORT
      LAYER M4 ;
        RECT  43.116 49.296 43.2 49.32 ;
    END
  END pin_data[298]
  PIN pin_data[299]
    DIRECTION OUTPUT ;
    USE SIGNAL ;
    PORT
      LAYER M4 ;
        RECT  43.116 49.392 43.2 49.416 ;
    END
  END pin_data[299]
  PIN pin_data[29]
    DIRECTION OUTPUT ;
    USE SIGNAL ;
    PORT
      LAYER M4 ;
        RECT  43.116 61.104 43.2 61.128 ;
    END
  END pin_data[29]
  PIN pin_data[2]
    DIRECTION OUTPUT ;
    USE SIGNAL ;
    PORT
      LAYER M4 ;
        RECT  43.116 58.512 43.2 58.536 ;
    END
  END pin_data[2]
  PIN pin_data[300]
    DIRECTION OUTPUT ;
    USE SIGNAL ;
    PORT
      LAYER M4 ;
        RECT  43.116 49.488 43.2 49.512 ;
    END
  END pin_data[300]
  PIN pin_data[301]
    DIRECTION OUTPUT ;
    USE SIGNAL ;
    PORT
      LAYER M4 ;
        RECT  43.116 49.584 43.2 49.608 ;
    END
  END pin_data[301]
  PIN pin_data[302]
    DIRECTION OUTPUT ;
    USE SIGNAL ;
    PORT
      LAYER M4 ;
        RECT  43.116 49.68 43.2 49.704 ;
    END
  END pin_data[302]
  PIN pin_data[303]
    DIRECTION OUTPUT ;
    USE SIGNAL ;
    PORT
      LAYER M4 ;
        RECT  43.116 49.776 43.2 49.8 ;
    END
  END pin_data[303]
  PIN pin_data[304]
    DIRECTION OUTPUT ;
    USE SIGNAL ;
    PORT
      LAYER M4 ;
        RECT  43.116 49.872 43.2 49.896 ;
    END
  END pin_data[304]
  PIN pin_data[305]
    DIRECTION OUTPUT ;
    USE SIGNAL ;
    PORT
      LAYER M4 ;
        RECT  43.116 49.968 43.2 49.992 ;
    END
  END pin_data[305]
  PIN pin_data[306]
    DIRECTION OUTPUT ;
    USE SIGNAL ;
    PORT
      LAYER M4 ;
        RECT  43.116 50.064 43.2 50.088 ;
    END
  END pin_data[306]
  PIN pin_data[307]
    DIRECTION OUTPUT ;
    USE SIGNAL ;
    PORT
      LAYER M4 ;
        RECT  43.116 50.16 43.2 50.184 ;
    END
  END pin_data[307]
  PIN pin_data[308]
    DIRECTION OUTPUT ;
    USE SIGNAL ;
    PORT
      LAYER M4 ;
        RECT  43.116 50.256 43.2 50.28 ;
    END
  END pin_data[308]
  PIN pin_data[309]
    DIRECTION OUTPUT ;
    USE SIGNAL ;
    PORT
      LAYER M4 ;
        RECT  43.116 50.352 43.2 50.376 ;
    END
  END pin_data[309]
  PIN pin_data[30]
    DIRECTION OUTPUT ;
    USE SIGNAL ;
    PORT
      LAYER M4 ;
        RECT  43.116 61.2 43.2 61.224 ;
    END
  END pin_data[30]
  PIN pin_data[310]
    DIRECTION OUTPUT ;
    USE SIGNAL ;
    PORT
      LAYER M4 ;
        RECT  43.116 50.448 43.2 50.472 ;
    END
  END pin_data[310]
  PIN pin_data[311]
    DIRECTION OUTPUT ;
    USE SIGNAL ;
    PORT
      LAYER M4 ;
        RECT  43.116 50.544 43.2 50.568 ;
    END
  END pin_data[311]
  PIN pin_data[312]
    DIRECTION OUTPUT ;
    USE SIGNAL ;
    PORT
      LAYER M4 ;
        RECT  43.116 50.64 43.2 50.664 ;
    END
  END pin_data[312]
  PIN pin_data[313]
    DIRECTION OUTPUT ;
    USE SIGNAL ;
    PORT
      LAYER M4 ;
        RECT  43.116 50.736 43.2 50.76 ;
    END
  END pin_data[313]
  PIN pin_data[314]
    DIRECTION OUTPUT ;
    USE SIGNAL ;
    PORT
      LAYER M4 ;
        RECT  43.116 50.832 43.2 50.856 ;
    END
  END pin_data[314]
  PIN pin_data[315]
    DIRECTION OUTPUT ;
    USE SIGNAL ;
    PORT
      LAYER M4 ;
        RECT  43.116 50.928 43.2 50.952 ;
    END
  END pin_data[315]
  PIN pin_data[316]
    DIRECTION OUTPUT ;
    USE SIGNAL ;
    PORT
      LAYER M4 ;
        RECT  43.116 51.024 43.2 51.048 ;
    END
  END pin_data[316]
  PIN pin_data[317]
    DIRECTION OUTPUT ;
    USE SIGNAL ;
    PORT
      LAYER M4 ;
        RECT  43.116 51.12 43.2 51.144 ;
    END
  END pin_data[317]
  PIN pin_data[318]
    DIRECTION OUTPUT ;
    USE SIGNAL ;
    PORT
      LAYER M4 ;
        RECT  43.116 51.216 43.2 51.24 ;
    END
  END pin_data[318]
  PIN pin_data[319]
    DIRECTION OUTPUT ;
    USE SIGNAL ;
    PORT
      LAYER M4 ;
        RECT  43.116 51.312 43.2 51.336 ;
    END
  END pin_data[319]
  PIN pin_data[31]
    DIRECTION OUTPUT ;
    USE SIGNAL ;
    PORT
      LAYER M4 ;
        RECT  43.116 61.296 43.2 61.32 ;
    END
  END pin_data[31]
  PIN pin_data[320]
    DIRECTION OUTPUT ;
    USE SIGNAL ;
    PORT
      LAYER M4 ;
        RECT  43.116 42.192 43.2 42.216 ;
    END
  END pin_data[320]
  PIN pin_data[321]
    DIRECTION OUTPUT ;
    USE SIGNAL ;
    PORT
      LAYER M4 ;
        RECT  43.116 42.288 43.2 42.312 ;
    END
  END pin_data[321]
  PIN pin_data[322]
    DIRECTION OUTPUT ;
    USE SIGNAL ;
    PORT
      LAYER M4 ;
        RECT  43.116 42.384 43.2 42.408 ;
    END
  END pin_data[322]
  PIN pin_data[323]
    DIRECTION OUTPUT ;
    USE SIGNAL ;
    PORT
      LAYER M4 ;
        RECT  43.116 42.48 43.2 42.504 ;
    END
  END pin_data[323]
  PIN pin_data[324]
    DIRECTION OUTPUT ;
    USE SIGNAL ;
    PORT
      LAYER M4 ;
        RECT  43.116 42.576 43.2 42.6 ;
    END
  END pin_data[324]
  PIN pin_data[325]
    DIRECTION OUTPUT ;
    USE SIGNAL ;
    PORT
      LAYER M4 ;
        RECT  43.116 42.672 43.2 42.696 ;
    END
  END pin_data[325]
  PIN pin_data[326]
    DIRECTION OUTPUT ;
    USE SIGNAL ;
    PORT
      LAYER M4 ;
        RECT  43.116 42.768 43.2 42.792 ;
    END
  END pin_data[326]
  PIN pin_data[327]
    DIRECTION OUTPUT ;
    USE SIGNAL ;
    PORT
      LAYER M4 ;
        RECT  43.116 42.864 43.2 42.888 ;
    END
  END pin_data[327]
  PIN pin_data[328]
    DIRECTION OUTPUT ;
    USE SIGNAL ;
    PORT
      LAYER M4 ;
        RECT  43.116 42.96 43.2 42.984 ;
    END
  END pin_data[328]
  PIN pin_data[329]
    DIRECTION OUTPUT ;
    USE SIGNAL ;
    PORT
      LAYER M4 ;
        RECT  43.116 43.056 43.2 43.08 ;
    END
  END pin_data[329]
  PIN pin_data[32]
    DIRECTION OUTPUT ;
    USE SIGNAL ;
    PORT
      LAYER M4 ;
        RECT  43.116 70.608 43.2 70.632 ;
    END
  END pin_data[32]
  PIN pin_data[330]
    DIRECTION OUTPUT ;
    USE SIGNAL ;
    PORT
      LAYER M4 ;
        RECT  43.116 43.152 43.2 43.176 ;
    END
  END pin_data[330]
  PIN pin_data[331]
    DIRECTION OUTPUT ;
    USE SIGNAL ;
    PORT
      LAYER M4 ;
        RECT  43.116 43.248 43.2 43.272 ;
    END
  END pin_data[331]
  PIN pin_data[332]
    DIRECTION OUTPUT ;
    USE SIGNAL ;
    PORT
      LAYER M4 ;
        RECT  43.116 43.344 43.2 43.368 ;
    END
  END pin_data[332]
  PIN pin_data[333]
    DIRECTION OUTPUT ;
    USE SIGNAL ;
    PORT
      LAYER M4 ;
        RECT  43.116 43.44 43.2 43.464 ;
    END
  END pin_data[333]
  PIN pin_data[334]
    DIRECTION OUTPUT ;
    USE SIGNAL ;
    PORT
      LAYER M4 ;
        RECT  43.116 43.536 43.2 43.56 ;
    END
  END pin_data[334]
  PIN pin_data[335]
    DIRECTION OUTPUT ;
    USE SIGNAL ;
    PORT
      LAYER M4 ;
        RECT  43.116 43.632 43.2 43.656 ;
    END
  END pin_data[335]
  PIN pin_data[336]
    DIRECTION OUTPUT ;
    USE SIGNAL ;
    PORT
      LAYER M4 ;
        RECT  43.116 43.728 43.2 43.752 ;
    END
  END pin_data[336]
  PIN pin_data[337]
    DIRECTION OUTPUT ;
    USE SIGNAL ;
    PORT
      LAYER M4 ;
        RECT  43.116 43.824 43.2 43.848 ;
    END
  END pin_data[337]
  PIN pin_data[338]
    DIRECTION OUTPUT ;
    USE SIGNAL ;
    PORT
      LAYER M4 ;
        RECT  43.116 43.92 43.2 43.944 ;
    END
  END pin_data[338]
  PIN pin_data[339]
    DIRECTION OUTPUT ;
    USE SIGNAL ;
    PORT
      LAYER M4 ;
        RECT  43.116 44.016 43.2 44.04 ;
    END
  END pin_data[339]
  PIN pin_data[33]
    DIRECTION OUTPUT ;
    USE SIGNAL ;
    PORT
      LAYER M4 ;
        RECT  43.116 70.704 43.2 70.728 ;
    END
  END pin_data[33]
  PIN pin_data[340]
    DIRECTION OUTPUT ;
    USE SIGNAL ;
    PORT
      LAYER M4 ;
        RECT  43.116 44.112 43.2 44.136 ;
    END
  END pin_data[340]
  PIN pin_data[341]
    DIRECTION OUTPUT ;
    USE SIGNAL ;
    PORT
      LAYER M4 ;
        RECT  43.116 44.208 43.2 44.232 ;
    END
  END pin_data[341]
  PIN pin_data[342]
    DIRECTION OUTPUT ;
    USE SIGNAL ;
    PORT
      LAYER M4 ;
        RECT  43.116 44.304 43.2 44.328 ;
    END
  END pin_data[342]
  PIN pin_data[343]
    DIRECTION OUTPUT ;
    USE SIGNAL ;
    PORT
      LAYER M4 ;
        RECT  43.116 44.4 43.2 44.424 ;
    END
  END pin_data[343]
  PIN pin_data[344]
    DIRECTION OUTPUT ;
    USE SIGNAL ;
    PORT
      LAYER M4 ;
        RECT  43.116 44.496 43.2 44.52 ;
    END
  END pin_data[344]
  PIN pin_data[345]
    DIRECTION OUTPUT ;
    USE SIGNAL ;
    PORT
      LAYER M4 ;
        RECT  43.116 44.592 43.2 44.616 ;
    END
  END pin_data[345]
  PIN pin_data[346]
    DIRECTION OUTPUT ;
    USE SIGNAL ;
    PORT
      LAYER M4 ;
        RECT  43.116 44.688 43.2 44.712 ;
    END
  END pin_data[346]
  PIN pin_data[347]
    DIRECTION OUTPUT ;
    USE SIGNAL ;
    PORT
      LAYER M4 ;
        RECT  43.116 44.784 43.2 44.808 ;
    END
  END pin_data[347]
  PIN pin_data[348]
    DIRECTION OUTPUT ;
    USE SIGNAL ;
    PORT
      LAYER M4 ;
        RECT  43.116 44.88 43.2 44.904 ;
    END
  END pin_data[348]
  PIN pin_data[349]
    DIRECTION OUTPUT ;
    USE SIGNAL ;
    PORT
      LAYER M4 ;
        RECT  43.116 44.976 43.2 45 ;
    END
  END pin_data[349]
  PIN pin_data[34]
    DIRECTION OUTPUT ;
    USE SIGNAL ;
    PORT
      LAYER M4 ;
        RECT  43.116 70.8 43.2 70.824 ;
    END
  END pin_data[34]
  PIN pin_data[350]
    DIRECTION OUTPUT ;
    USE SIGNAL ;
    PORT
      LAYER M4 ;
        RECT  43.116 45.072 43.2 45.096 ;
    END
  END pin_data[350]
  PIN pin_data[351]
    DIRECTION OUTPUT ;
    USE SIGNAL ;
    PORT
      LAYER M4 ;
        RECT  43.116 45.168 43.2 45.192 ;
    END
  END pin_data[351]
  PIN pin_data[352]
    DIRECTION OUTPUT ;
    USE SIGNAL ;
    PORT
      LAYER M4 ;
        RECT  43.116 54.48 43.2 54.504 ;
    END
  END pin_data[352]
  PIN pin_data[353]
    DIRECTION OUTPUT ;
    USE SIGNAL ;
    PORT
      LAYER M4 ;
        RECT  43.116 54.576 43.2 54.6 ;
    END
  END pin_data[353]
  PIN pin_data[354]
    DIRECTION OUTPUT ;
    USE SIGNAL ;
    PORT
      LAYER M4 ;
        RECT  43.116 54.672 43.2 54.696 ;
    END
  END pin_data[354]
  PIN pin_data[355]
    DIRECTION OUTPUT ;
    USE SIGNAL ;
    PORT
      LAYER M4 ;
        RECT  43.116 54.768 43.2 54.792 ;
    END
  END pin_data[355]
  PIN pin_data[356]
    DIRECTION OUTPUT ;
    USE SIGNAL ;
    PORT
      LAYER M4 ;
        RECT  43.116 54.864 43.2 54.888 ;
    END
  END pin_data[356]
  PIN pin_data[357]
    DIRECTION OUTPUT ;
    USE SIGNAL ;
    PORT
      LAYER M4 ;
        RECT  43.116 54.96 43.2 54.984 ;
    END
  END pin_data[357]
  PIN pin_data[358]
    DIRECTION OUTPUT ;
    USE SIGNAL ;
    PORT
      LAYER M4 ;
        RECT  43.116 55.056 43.2 55.08 ;
    END
  END pin_data[358]
  PIN pin_data[359]
    DIRECTION OUTPUT ;
    USE SIGNAL ;
    PORT
      LAYER M4 ;
        RECT  43.116 55.152 43.2 55.176 ;
    END
  END pin_data[359]
  PIN pin_data[35]
    DIRECTION OUTPUT ;
    USE SIGNAL ;
    PORT
      LAYER M4 ;
        RECT  43.116 70.896 43.2 70.92 ;
    END
  END pin_data[35]
  PIN pin_data[360]
    DIRECTION OUTPUT ;
    USE SIGNAL ;
    PORT
      LAYER M4 ;
        RECT  43.116 55.248 43.2 55.272 ;
    END
  END pin_data[360]
  PIN pin_data[361]
    DIRECTION OUTPUT ;
    USE SIGNAL ;
    PORT
      LAYER M4 ;
        RECT  43.116 55.344 43.2 55.368 ;
    END
  END pin_data[361]
  PIN pin_data[362]
    DIRECTION OUTPUT ;
    USE SIGNAL ;
    PORT
      LAYER M4 ;
        RECT  43.116 55.44 43.2 55.464 ;
    END
  END pin_data[362]
  PIN pin_data[363]
    DIRECTION OUTPUT ;
    USE SIGNAL ;
    PORT
      LAYER M4 ;
        RECT  43.116 55.536 43.2 55.56 ;
    END
  END pin_data[363]
  PIN pin_data[364]
    DIRECTION OUTPUT ;
    USE SIGNAL ;
    PORT
      LAYER M4 ;
        RECT  43.116 55.632 43.2 55.656 ;
    END
  END pin_data[364]
  PIN pin_data[365]
    DIRECTION OUTPUT ;
    USE SIGNAL ;
    PORT
      LAYER M4 ;
        RECT  43.116 55.728 43.2 55.752 ;
    END
  END pin_data[365]
  PIN pin_data[366]
    DIRECTION OUTPUT ;
    USE SIGNAL ;
    PORT
      LAYER M4 ;
        RECT  43.116 55.824 43.2 55.848 ;
    END
  END pin_data[366]
  PIN pin_data[367]
    DIRECTION OUTPUT ;
    USE SIGNAL ;
    PORT
      LAYER M4 ;
        RECT  43.116 55.92 43.2 55.944 ;
    END
  END pin_data[367]
  PIN pin_data[368]
    DIRECTION OUTPUT ;
    USE SIGNAL ;
    PORT
      LAYER M4 ;
        RECT  43.116 56.016 43.2 56.04 ;
    END
  END pin_data[368]
  PIN pin_data[369]
    DIRECTION OUTPUT ;
    USE SIGNAL ;
    PORT
      LAYER M4 ;
        RECT  43.116 56.112 43.2 56.136 ;
    END
  END pin_data[369]
  PIN pin_data[36]
    DIRECTION OUTPUT ;
    USE SIGNAL ;
    PORT
      LAYER M4 ;
        RECT  43.116 70.992 43.2 71.016 ;
    END
  END pin_data[36]
  PIN pin_data[370]
    DIRECTION OUTPUT ;
    USE SIGNAL ;
    PORT
      LAYER M4 ;
        RECT  43.116 56.208 43.2 56.232 ;
    END
  END pin_data[370]
  PIN pin_data[371]
    DIRECTION OUTPUT ;
    USE SIGNAL ;
    PORT
      LAYER M4 ;
        RECT  43.116 56.304 43.2 56.328 ;
    END
  END pin_data[371]
  PIN pin_data[372]
    DIRECTION OUTPUT ;
    USE SIGNAL ;
    PORT
      LAYER M4 ;
        RECT  43.116 56.4 43.2 56.424 ;
    END
  END pin_data[372]
  PIN pin_data[373]
    DIRECTION OUTPUT ;
    USE SIGNAL ;
    PORT
      LAYER M4 ;
        RECT  43.116 56.496 43.2 56.52 ;
    END
  END pin_data[373]
  PIN pin_data[374]
    DIRECTION OUTPUT ;
    USE SIGNAL ;
    PORT
      LAYER M4 ;
        RECT  43.116 56.592 43.2 56.616 ;
    END
  END pin_data[374]
  PIN pin_data[375]
    DIRECTION OUTPUT ;
    USE SIGNAL ;
    PORT
      LAYER M4 ;
        RECT  43.116 56.688 43.2 56.712 ;
    END
  END pin_data[375]
  PIN pin_data[376]
    DIRECTION OUTPUT ;
    USE SIGNAL ;
    PORT
      LAYER M4 ;
        RECT  43.116 56.784 43.2 56.808 ;
    END
  END pin_data[376]
  PIN pin_data[377]
    DIRECTION OUTPUT ;
    USE SIGNAL ;
    PORT
      LAYER M4 ;
        RECT  43.116 56.88 43.2 56.904 ;
    END
  END pin_data[377]
  PIN pin_data[378]
    DIRECTION OUTPUT ;
    USE SIGNAL ;
    PORT
      LAYER M4 ;
        RECT  43.116 56.976 43.2 57 ;
    END
  END pin_data[378]
  PIN pin_data[379]
    DIRECTION OUTPUT ;
    USE SIGNAL ;
    PORT
      LAYER M4 ;
        RECT  43.116 57.072 43.2 57.096 ;
    END
  END pin_data[379]
  PIN pin_data[37]
    DIRECTION OUTPUT ;
    USE SIGNAL ;
    PORT
      LAYER M4 ;
        RECT  43.116 71.088 43.2 71.112 ;
    END
  END pin_data[37]
  PIN pin_data[380]
    DIRECTION OUTPUT ;
    USE SIGNAL ;
    PORT
      LAYER M4 ;
        RECT  43.116 57.168 43.2 57.192 ;
    END
  END pin_data[380]
  PIN pin_data[381]
    DIRECTION OUTPUT ;
    USE SIGNAL ;
    PORT
      LAYER M4 ;
        RECT  43.116 57.264 43.2 57.288 ;
    END
  END pin_data[381]
  PIN pin_data[382]
    DIRECTION OUTPUT ;
    USE SIGNAL ;
    PORT
      LAYER M4 ;
        RECT  43.116 57.36 43.2 57.384 ;
    END
  END pin_data[382]
  PIN pin_data[383]
    DIRECTION OUTPUT ;
    USE SIGNAL ;
    PORT
      LAYER M4 ;
        RECT  43.116 57.456 43.2 57.48 ;
    END
  END pin_data[383]
  PIN pin_data[384]
    DIRECTION OUTPUT ;
    USE SIGNAL ;
    PORT
      LAYER M4 ;
        RECT  43.116 86.736 43.2 86.76 ;
    END
  END pin_data[384]
  PIN pin_data[385]
    DIRECTION OUTPUT ;
    USE SIGNAL ;
    PORT
      LAYER M4 ;
        RECT  43.116 86.832 43.2 86.856 ;
    END
  END pin_data[385]
  PIN pin_data[386]
    DIRECTION OUTPUT ;
    USE SIGNAL ;
    PORT
      LAYER M4 ;
        RECT  43.116 86.928 43.2 86.952 ;
    END
  END pin_data[386]
  PIN pin_data[387]
    DIRECTION OUTPUT ;
    USE SIGNAL ;
    PORT
      LAYER M4 ;
        RECT  43.116 87.024 43.2 87.048 ;
    END
  END pin_data[387]
  PIN pin_data[388]
    DIRECTION OUTPUT ;
    USE SIGNAL ;
    PORT
      LAYER M4 ;
        RECT  43.116 87.12 43.2 87.144 ;
    END
  END pin_data[388]
  PIN pin_data[389]
    DIRECTION OUTPUT ;
    USE SIGNAL ;
    PORT
      LAYER M4 ;
        RECT  43.116 87.216 43.2 87.24 ;
    END
  END pin_data[389]
  PIN pin_data[38]
    DIRECTION OUTPUT ;
    USE SIGNAL ;
    PORT
      LAYER M4 ;
        RECT  43.116 71.184 43.2 71.208 ;
    END
  END pin_data[38]
  PIN pin_data[390]
    DIRECTION OUTPUT ;
    USE SIGNAL ;
    PORT
      LAYER M4 ;
        RECT  43.116 87.312 43.2 87.336 ;
    END
  END pin_data[390]
  PIN pin_data[391]
    DIRECTION OUTPUT ;
    USE SIGNAL ;
    PORT
      LAYER M4 ;
        RECT  43.116 87.408 43.2 87.432 ;
    END
  END pin_data[391]
  PIN pin_data[392]
    DIRECTION OUTPUT ;
    USE SIGNAL ;
    PORT
      LAYER M4 ;
        RECT  43.116 87.504 43.2 87.528 ;
    END
  END pin_data[392]
  PIN pin_data[393]
    DIRECTION OUTPUT ;
    USE SIGNAL ;
    PORT
      LAYER M4 ;
        RECT  43.116 87.6 43.2 87.624 ;
    END
  END pin_data[393]
  PIN pin_data[394]
    DIRECTION OUTPUT ;
    USE SIGNAL ;
    PORT
      LAYER M4 ;
        RECT  43.116 87.696 43.2 87.72 ;
    END
  END pin_data[394]
  PIN pin_data[395]
    DIRECTION OUTPUT ;
    USE SIGNAL ;
    PORT
      LAYER M4 ;
        RECT  43.116 87.792 43.2 87.816 ;
    END
  END pin_data[395]
  PIN pin_data[396]
    DIRECTION OUTPUT ;
    USE SIGNAL ;
    PORT
      LAYER M4 ;
        RECT  43.116 87.888 43.2 87.912 ;
    END
  END pin_data[396]
  PIN pin_data[397]
    DIRECTION OUTPUT ;
    USE SIGNAL ;
    PORT
      LAYER M4 ;
        RECT  43.116 87.984 43.2 88.008 ;
    END
  END pin_data[397]
  PIN pin_data[398]
    DIRECTION OUTPUT ;
    USE SIGNAL ;
    PORT
      LAYER M4 ;
        RECT  43.116 88.08 43.2 88.104 ;
    END
  END pin_data[398]
  PIN pin_data[399]
    DIRECTION OUTPUT ;
    USE SIGNAL ;
    PORT
      LAYER M4 ;
        RECT  43.116 88.176 43.2 88.2 ;
    END
  END pin_data[399]
  PIN pin_data[39]
    DIRECTION OUTPUT ;
    USE SIGNAL ;
    PORT
      LAYER M4 ;
        RECT  43.116 71.28 43.2 71.304 ;
    END
  END pin_data[39]
  PIN pin_data[3]
    DIRECTION OUTPUT ;
    USE SIGNAL ;
    PORT
      LAYER M4 ;
        RECT  43.116 58.608 43.2 58.632 ;
    END
  END pin_data[3]
  PIN pin_data[400]
    DIRECTION OUTPUT ;
    USE SIGNAL ;
    PORT
      LAYER M4 ;
        RECT  43.116 88.272 43.2 88.296 ;
    END
  END pin_data[400]
  PIN pin_data[401]
    DIRECTION OUTPUT ;
    USE SIGNAL ;
    PORT
      LAYER M4 ;
        RECT  43.116 88.368 43.2 88.392 ;
    END
  END pin_data[401]
  PIN pin_data[402]
    DIRECTION OUTPUT ;
    USE SIGNAL ;
    PORT
      LAYER M4 ;
        RECT  43.116 88.464 43.2 88.488 ;
    END
  END pin_data[402]
  PIN pin_data[403]
    DIRECTION OUTPUT ;
    USE SIGNAL ;
    PORT
      LAYER M4 ;
        RECT  43.116 88.56 43.2 88.584 ;
    END
  END pin_data[403]
  PIN pin_data[404]
    DIRECTION OUTPUT ;
    USE SIGNAL ;
    PORT
      LAYER M4 ;
        RECT  43.116 88.656 43.2 88.68 ;
    END
  END pin_data[404]
  PIN pin_data[405]
    DIRECTION OUTPUT ;
    USE SIGNAL ;
    PORT
      LAYER M4 ;
        RECT  43.116 88.752 43.2 88.776 ;
    END
  END pin_data[405]
  PIN pin_data[406]
    DIRECTION OUTPUT ;
    USE SIGNAL ;
    PORT
      LAYER M4 ;
        RECT  43.116 88.848 43.2 88.872 ;
    END
  END pin_data[406]
  PIN pin_data[407]
    DIRECTION OUTPUT ;
    USE SIGNAL ;
    PORT
      LAYER M4 ;
        RECT  43.116 88.944 43.2 88.968 ;
    END
  END pin_data[407]
  PIN pin_data[408]
    DIRECTION OUTPUT ;
    USE SIGNAL ;
    PORT
      LAYER M4 ;
        RECT  43.116 89.04 43.2 89.064 ;
    END
  END pin_data[408]
  PIN pin_data[409]
    DIRECTION OUTPUT ;
    USE SIGNAL ;
    PORT
      LAYER M4 ;
        RECT  43.116 89.136 43.2 89.16 ;
    END
  END pin_data[409]
  PIN pin_data[40]
    DIRECTION OUTPUT ;
    USE SIGNAL ;
    PORT
      LAYER M4 ;
        RECT  43.116 71.376 43.2 71.4 ;
    END
  END pin_data[40]
  PIN pin_data[410]
    DIRECTION OUTPUT ;
    USE SIGNAL ;
    PORT
      LAYER M4 ;
        RECT  43.116 89.232 43.2 89.256 ;
    END
  END pin_data[410]
  PIN pin_data[411]
    DIRECTION OUTPUT ;
    USE SIGNAL ;
    PORT
      LAYER M4 ;
        RECT  43.116 89.328 43.2 89.352 ;
    END
  END pin_data[411]
  PIN pin_data[412]
    DIRECTION OUTPUT ;
    USE SIGNAL ;
    PORT
      LAYER M4 ;
        RECT  43.116 89.424 43.2 89.448 ;
    END
  END pin_data[412]
  PIN pin_data[413]
    DIRECTION OUTPUT ;
    USE SIGNAL ;
    PORT
      LAYER M4 ;
        RECT  43.116 89.52 43.2 89.544 ;
    END
  END pin_data[413]
  PIN pin_data[414]
    DIRECTION OUTPUT ;
    USE SIGNAL ;
    PORT
      LAYER M4 ;
        RECT  43.116 89.616 43.2 89.64 ;
    END
  END pin_data[414]
  PIN pin_data[415]
    DIRECTION OUTPUT ;
    USE SIGNAL ;
    PORT
      LAYER M4 ;
        RECT  43.116 89.712 43.2 89.736 ;
    END
  END pin_data[415]
  PIN pin_data[416]
    DIRECTION OUTPUT ;
    USE SIGNAL ;
    PORT
      LAYER M4 ;
        RECT  43.116 80.592 43.2 80.616 ;
    END
  END pin_data[416]
  PIN pin_data[417]
    DIRECTION OUTPUT ;
    USE SIGNAL ;
    PORT
      LAYER M4 ;
        RECT  43.116 80.688 43.2 80.712 ;
    END
  END pin_data[417]
  PIN pin_data[418]
    DIRECTION OUTPUT ;
    USE SIGNAL ;
    PORT
      LAYER M4 ;
        RECT  43.116 80.784 43.2 80.808 ;
    END
  END pin_data[418]
  PIN pin_data[419]
    DIRECTION OUTPUT ;
    USE SIGNAL ;
    PORT
      LAYER M4 ;
        RECT  43.116 80.88 43.2 80.904 ;
    END
  END pin_data[419]
  PIN pin_data[41]
    DIRECTION OUTPUT ;
    USE SIGNAL ;
    PORT
      LAYER M4 ;
        RECT  43.116 71.472 43.2 71.496 ;
    END
  END pin_data[41]
  PIN pin_data[420]
    DIRECTION OUTPUT ;
    USE SIGNAL ;
    PORT
      LAYER M4 ;
        RECT  43.116 80.976 43.2 81 ;
    END
  END pin_data[420]
  PIN pin_data[421]
    DIRECTION OUTPUT ;
    USE SIGNAL ;
    PORT
      LAYER M4 ;
        RECT  43.116 81.072 43.2 81.096 ;
    END
  END pin_data[421]
  PIN pin_data[422]
    DIRECTION OUTPUT ;
    USE SIGNAL ;
    PORT
      LAYER M4 ;
        RECT  43.116 81.168 43.2 81.192 ;
    END
  END pin_data[422]
  PIN pin_data[423]
    DIRECTION OUTPUT ;
    USE SIGNAL ;
    PORT
      LAYER M4 ;
        RECT  43.116 81.264 43.2 81.288 ;
    END
  END pin_data[423]
  PIN pin_data[424]
    DIRECTION OUTPUT ;
    USE SIGNAL ;
    PORT
      LAYER M4 ;
        RECT  43.116 81.36 43.2 81.384 ;
    END
  END pin_data[424]
  PIN pin_data[425]
    DIRECTION OUTPUT ;
    USE SIGNAL ;
    PORT
      LAYER M4 ;
        RECT  43.116 81.456 43.2 81.48 ;
    END
  END pin_data[425]
  PIN pin_data[426]
    DIRECTION OUTPUT ;
    USE SIGNAL ;
    PORT
      LAYER M4 ;
        RECT  43.116 81.552 43.2 81.576 ;
    END
  END pin_data[426]
  PIN pin_data[427]
    DIRECTION OUTPUT ;
    USE SIGNAL ;
    PORT
      LAYER M4 ;
        RECT  43.116 81.648 43.2 81.672 ;
    END
  END pin_data[427]
  PIN pin_data[428]
    DIRECTION OUTPUT ;
    USE SIGNAL ;
    PORT
      LAYER M4 ;
        RECT  43.116 81.744 43.2 81.768 ;
    END
  END pin_data[428]
  PIN pin_data[429]
    DIRECTION OUTPUT ;
    USE SIGNAL ;
    PORT
      LAYER M4 ;
        RECT  43.116 81.84 43.2 81.864 ;
    END
  END pin_data[429]
  PIN pin_data[42]
    DIRECTION OUTPUT ;
    USE SIGNAL ;
    PORT
      LAYER M4 ;
        RECT  43.116 71.568 43.2 71.592 ;
    END
  END pin_data[42]
  PIN pin_data[430]
    DIRECTION OUTPUT ;
    USE SIGNAL ;
    PORT
      LAYER M4 ;
        RECT  43.116 81.936 43.2 81.96 ;
    END
  END pin_data[430]
  PIN pin_data[431]
    DIRECTION OUTPUT ;
    USE SIGNAL ;
    PORT
      LAYER M4 ;
        RECT  43.116 82.032 43.2 82.056 ;
    END
  END pin_data[431]
  PIN pin_data[432]
    DIRECTION OUTPUT ;
    USE SIGNAL ;
    PORT
      LAYER M4 ;
        RECT  43.116 82.128 43.2 82.152 ;
    END
  END pin_data[432]
  PIN pin_data[433]
    DIRECTION OUTPUT ;
    USE SIGNAL ;
    PORT
      LAYER M4 ;
        RECT  43.116 82.224 43.2 82.248 ;
    END
  END pin_data[433]
  PIN pin_data[434]
    DIRECTION OUTPUT ;
    USE SIGNAL ;
    PORT
      LAYER M4 ;
        RECT  43.116 82.32 43.2 82.344 ;
    END
  END pin_data[434]
  PIN pin_data[435]
    DIRECTION OUTPUT ;
    USE SIGNAL ;
    PORT
      LAYER M4 ;
        RECT  43.116 82.416 43.2 82.44 ;
    END
  END pin_data[435]
  PIN pin_data[436]
    DIRECTION OUTPUT ;
    USE SIGNAL ;
    PORT
      LAYER M4 ;
        RECT  43.116 82.512 43.2 82.536 ;
    END
  END pin_data[436]
  PIN pin_data[437]
    DIRECTION OUTPUT ;
    USE SIGNAL ;
    PORT
      LAYER M4 ;
        RECT  43.116 82.608 43.2 82.632 ;
    END
  END pin_data[437]
  PIN pin_data[438]
    DIRECTION OUTPUT ;
    USE SIGNAL ;
    PORT
      LAYER M4 ;
        RECT  43.116 82.704 43.2 82.728 ;
    END
  END pin_data[438]
  PIN pin_data[439]
    DIRECTION OUTPUT ;
    USE SIGNAL ;
    PORT
      LAYER M4 ;
        RECT  43.116 82.8 43.2 82.824 ;
    END
  END pin_data[439]
  PIN pin_data[43]
    DIRECTION OUTPUT ;
    USE SIGNAL ;
    PORT
      LAYER M4 ;
        RECT  43.116 71.664 43.2 71.688 ;
    END
  END pin_data[43]
  PIN pin_data[440]
    DIRECTION OUTPUT ;
    USE SIGNAL ;
    PORT
      LAYER M4 ;
        RECT  43.116 82.896 43.2 82.92 ;
    END
  END pin_data[440]
  PIN pin_data[441]
    DIRECTION OUTPUT ;
    USE SIGNAL ;
    PORT
      LAYER M4 ;
        RECT  43.116 82.992 43.2 83.016 ;
    END
  END pin_data[441]
  PIN pin_data[442]
    DIRECTION OUTPUT ;
    USE SIGNAL ;
    PORT
      LAYER M4 ;
        RECT  43.116 83.088 43.2 83.112 ;
    END
  END pin_data[442]
  PIN pin_data[443]
    DIRECTION OUTPUT ;
    USE SIGNAL ;
    PORT
      LAYER M4 ;
        RECT  43.116 83.184 43.2 83.208 ;
    END
  END pin_data[443]
  PIN pin_data[444]
    DIRECTION OUTPUT ;
    USE SIGNAL ;
    PORT
      LAYER M4 ;
        RECT  43.116 83.28 43.2 83.304 ;
    END
  END pin_data[444]
  PIN pin_data[445]
    DIRECTION OUTPUT ;
    USE SIGNAL ;
    PORT
      LAYER M4 ;
        RECT  43.116 83.376 43.2 83.4 ;
    END
  END pin_data[445]
  PIN pin_data[446]
    DIRECTION OUTPUT ;
    USE SIGNAL ;
    PORT
      LAYER M4 ;
        RECT  43.116 83.472 43.2 83.496 ;
    END
  END pin_data[446]
  PIN pin_data[447]
    DIRECTION OUTPUT ;
    USE SIGNAL ;
    PORT
      LAYER M4 ;
        RECT  43.116 83.568 43.2 83.592 ;
    END
  END pin_data[447]
  PIN pin_data[448]
    DIRECTION OUTPUT ;
    USE SIGNAL ;
    PORT
      LAYER M4 ;
        RECT  43.116 77.52 43.2 77.544 ;
    END
  END pin_data[448]
  PIN pin_data[449]
    DIRECTION OUTPUT ;
    USE SIGNAL ;
    PORT
      LAYER M4 ;
        RECT  43.116 77.616 43.2 77.64 ;
    END
  END pin_data[449]
  PIN pin_data[44]
    DIRECTION OUTPUT ;
    USE SIGNAL ;
    PORT
      LAYER M4 ;
        RECT  43.116 71.76 43.2 71.784 ;
    END
  END pin_data[44]
  PIN pin_data[450]
    DIRECTION OUTPUT ;
    USE SIGNAL ;
    PORT
      LAYER M4 ;
        RECT  43.116 77.712 43.2 77.736 ;
    END
  END pin_data[450]
  PIN pin_data[451]
    DIRECTION OUTPUT ;
    USE SIGNAL ;
    PORT
      LAYER M4 ;
        RECT  43.116 77.808 43.2 77.832 ;
    END
  END pin_data[451]
  PIN pin_data[452]
    DIRECTION OUTPUT ;
    USE SIGNAL ;
    PORT
      LAYER M4 ;
        RECT  43.116 77.904 43.2 77.928 ;
    END
  END pin_data[452]
  PIN pin_data[453]
    DIRECTION OUTPUT ;
    USE SIGNAL ;
    PORT
      LAYER M4 ;
        RECT  43.116 78 43.2 78.024 ;
    END
  END pin_data[453]
  PIN pin_data[454]
    DIRECTION OUTPUT ;
    USE SIGNAL ;
    PORT
      LAYER M4 ;
        RECT  43.116 78.096 43.2 78.12 ;
    END
  END pin_data[454]
  PIN pin_data[455]
    DIRECTION OUTPUT ;
    USE SIGNAL ;
    PORT
      LAYER M4 ;
        RECT  43.116 78.192 43.2 78.216 ;
    END
  END pin_data[455]
  PIN pin_data[456]
    DIRECTION OUTPUT ;
    USE SIGNAL ;
    PORT
      LAYER M4 ;
        RECT  43.116 78.288 43.2 78.312 ;
    END
  END pin_data[456]
  PIN pin_data[457]
    DIRECTION OUTPUT ;
    USE SIGNAL ;
    PORT
      LAYER M4 ;
        RECT  43.116 78.384 43.2 78.408 ;
    END
  END pin_data[457]
  PIN pin_data[458]
    DIRECTION OUTPUT ;
    USE SIGNAL ;
    PORT
      LAYER M4 ;
        RECT  43.116 78.48 43.2 78.504 ;
    END
  END pin_data[458]
  PIN pin_data[459]
    DIRECTION OUTPUT ;
    USE SIGNAL ;
    PORT
      LAYER M4 ;
        RECT  43.116 78.576 43.2 78.6 ;
    END
  END pin_data[459]
  PIN pin_data[45]
    DIRECTION OUTPUT ;
    USE SIGNAL ;
    PORT
      LAYER M4 ;
        RECT  43.116 71.856 43.2 71.88 ;
    END
  END pin_data[45]
  PIN pin_data[460]
    DIRECTION OUTPUT ;
    USE SIGNAL ;
    PORT
      LAYER M4 ;
        RECT  43.116 78.672 43.2 78.696 ;
    END
  END pin_data[460]
  PIN pin_data[461]
    DIRECTION OUTPUT ;
    USE SIGNAL ;
    PORT
      LAYER M4 ;
        RECT  43.116 78.768 43.2 78.792 ;
    END
  END pin_data[461]
  PIN pin_data[462]
    DIRECTION OUTPUT ;
    USE SIGNAL ;
    PORT
      LAYER M4 ;
        RECT  43.116 78.864 43.2 78.888 ;
    END
  END pin_data[462]
  PIN pin_data[463]
    DIRECTION OUTPUT ;
    USE SIGNAL ;
    PORT
      LAYER M4 ;
        RECT  43.116 78.96 43.2 78.984 ;
    END
  END pin_data[463]
  PIN pin_data[464]
    DIRECTION OUTPUT ;
    USE SIGNAL ;
    PORT
      LAYER M4 ;
        RECT  43.116 79.056 43.2 79.08 ;
    END
  END pin_data[464]
  PIN pin_data[465]
    DIRECTION OUTPUT ;
    USE SIGNAL ;
    PORT
      LAYER M4 ;
        RECT  43.116 79.152 43.2 79.176 ;
    END
  END pin_data[465]
  PIN pin_data[466]
    DIRECTION OUTPUT ;
    USE SIGNAL ;
    PORT
      LAYER M4 ;
        RECT  43.116 79.248 43.2 79.272 ;
    END
  END pin_data[466]
  PIN pin_data[467]
    DIRECTION OUTPUT ;
    USE SIGNAL ;
    PORT
      LAYER M4 ;
        RECT  43.116 79.344 43.2 79.368 ;
    END
  END pin_data[467]
  PIN pin_data[468]
    DIRECTION OUTPUT ;
    USE SIGNAL ;
    PORT
      LAYER M4 ;
        RECT  43.116 79.44 43.2 79.464 ;
    END
  END pin_data[468]
  PIN pin_data[469]
    DIRECTION OUTPUT ;
    USE SIGNAL ;
    PORT
      LAYER M4 ;
        RECT  43.116 79.536 43.2 79.56 ;
    END
  END pin_data[469]
  PIN pin_data[46]
    DIRECTION OUTPUT ;
    USE SIGNAL ;
    PORT
      LAYER M4 ;
        RECT  43.116 71.952 43.2 71.976 ;
    END
  END pin_data[46]
  PIN pin_data[470]
    DIRECTION OUTPUT ;
    USE SIGNAL ;
    PORT
      LAYER M4 ;
        RECT  43.116 79.632 43.2 79.656 ;
    END
  END pin_data[470]
  PIN pin_data[471]
    DIRECTION OUTPUT ;
    USE SIGNAL ;
    PORT
      LAYER M4 ;
        RECT  43.116 79.728 43.2 79.752 ;
    END
  END pin_data[471]
  PIN pin_data[472]
    DIRECTION OUTPUT ;
    USE SIGNAL ;
    PORT
      LAYER M4 ;
        RECT  43.116 79.824 43.2 79.848 ;
    END
  END pin_data[472]
  PIN pin_data[473]
    DIRECTION OUTPUT ;
    USE SIGNAL ;
    PORT
      LAYER M4 ;
        RECT  43.116 79.92 43.2 79.944 ;
    END
  END pin_data[473]
  PIN pin_data[474]
    DIRECTION OUTPUT ;
    USE SIGNAL ;
    PORT
      LAYER M4 ;
        RECT  43.116 80.016 43.2 80.04 ;
    END
  END pin_data[474]
  PIN pin_data[475]
    DIRECTION OUTPUT ;
    USE SIGNAL ;
    PORT
      LAYER M4 ;
        RECT  43.116 80.112 43.2 80.136 ;
    END
  END pin_data[475]
  PIN pin_data[476]
    DIRECTION OUTPUT ;
    USE SIGNAL ;
    PORT
      LAYER M4 ;
        RECT  43.116 80.208 43.2 80.232 ;
    END
  END pin_data[476]
  PIN pin_data[477]
    DIRECTION OUTPUT ;
    USE SIGNAL ;
    PORT
      LAYER M4 ;
        RECT  43.116 80.304 43.2 80.328 ;
    END
  END pin_data[477]
  PIN pin_data[478]
    DIRECTION OUTPUT ;
    USE SIGNAL ;
    PORT
      LAYER M4 ;
        RECT  43.116 80.4 43.2 80.424 ;
    END
  END pin_data[478]
  PIN pin_data[479]
    DIRECTION OUTPUT ;
    USE SIGNAL ;
    PORT
      LAYER M4 ;
        RECT  43.116 80.496 43.2 80.52 ;
    END
  END pin_data[479]
  PIN pin_data[47]
    DIRECTION OUTPUT ;
    USE SIGNAL ;
    PORT
      LAYER M4 ;
        RECT  43.116 72.048 43.2 72.072 ;
    END
  END pin_data[47]
  PIN pin_data[480]
    DIRECTION OUTPUT ;
    USE SIGNAL ;
    PORT
      LAYER M4 ;
        RECT  43.116 83.664 43.2 83.688 ;
    END
  END pin_data[480]
  PIN pin_data[481]
    DIRECTION OUTPUT ;
    USE SIGNAL ;
    PORT
      LAYER M4 ;
        RECT  43.116 83.76 43.2 83.784 ;
    END
  END pin_data[481]
  PIN pin_data[482]
    DIRECTION OUTPUT ;
    USE SIGNAL ;
    PORT
      LAYER M4 ;
        RECT  43.116 83.856 43.2 83.88 ;
    END
  END pin_data[482]
  PIN pin_data[483]
    DIRECTION OUTPUT ;
    USE SIGNAL ;
    PORT
      LAYER M4 ;
        RECT  43.116 83.952 43.2 83.976 ;
    END
  END pin_data[483]
  PIN pin_data[484]
    DIRECTION OUTPUT ;
    USE SIGNAL ;
    PORT
      LAYER M4 ;
        RECT  43.116 84.048 43.2 84.072 ;
    END
  END pin_data[484]
  PIN pin_data[485]
    DIRECTION OUTPUT ;
    USE SIGNAL ;
    PORT
      LAYER M4 ;
        RECT  43.116 84.144 43.2 84.168 ;
    END
  END pin_data[485]
  PIN pin_data[486]
    DIRECTION OUTPUT ;
    USE SIGNAL ;
    PORT
      LAYER M4 ;
        RECT  43.116 84.24 43.2 84.264 ;
    END
  END pin_data[486]
  PIN pin_data[487]
    DIRECTION OUTPUT ;
    USE SIGNAL ;
    PORT
      LAYER M4 ;
        RECT  43.116 84.336 43.2 84.36 ;
    END
  END pin_data[487]
  PIN pin_data[488]
    DIRECTION OUTPUT ;
    USE SIGNAL ;
    PORT
      LAYER M4 ;
        RECT  43.116 84.432 43.2 84.456 ;
    END
  END pin_data[488]
  PIN pin_data[489]
    DIRECTION OUTPUT ;
    USE SIGNAL ;
    PORT
      LAYER M4 ;
        RECT  43.116 84.528 43.2 84.552 ;
    END
  END pin_data[489]
  PIN pin_data[48]
    DIRECTION OUTPUT ;
    USE SIGNAL ;
    PORT
      LAYER M4 ;
        RECT  43.116 72.144 43.2 72.168 ;
    END
  END pin_data[48]
  PIN pin_data[490]
    DIRECTION OUTPUT ;
    USE SIGNAL ;
    PORT
      LAYER M4 ;
        RECT  43.116 84.624 43.2 84.648 ;
    END
  END pin_data[490]
  PIN pin_data[491]
    DIRECTION OUTPUT ;
    USE SIGNAL ;
    PORT
      LAYER M4 ;
        RECT  43.116 84.72 43.2 84.744 ;
    END
  END pin_data[491]
  PIN pin_data[492]
    DIRECTION OUTPUT ;
    USE SIGNAL ;
    PORT
      LAYER M4 ;
        RECT  43.116 84.816 43.2 84.84 ;
    END
  END pin_data[492]
  PIN pin_data[493]
    DIRECTION OUTPUT ;
    USE SIGNAL ;
    PORT
      LAYER M4 ;
        RECT  43.116 84.912 43.2 84.936 ;
    END
  END pin_data[493]
  PIN pin_data[494]
    DIRECTION OUTPUT ;
    USE SIGNAL ;
    PORT
      LAYER M4 ;
        RECT  43.116 85.008 43.2 85.032 ;
    END
  END pin_data[494]
  PIN pin_data[495]
    DIRECTION OUTPUT ;
    USE SIGNAL ;
    PORT
      LAYER M4 ;
        RECT  43.116 85.104 43.2 85.128 ;
    END
  END pin_data[495]
  PIN pin_data[496]
    DIRECTION OUTPUT ;
    USE SIGNAL ;
    PORT
      LAYER M4 ;
        RECT  43.116 85.2 43.2 85.224 ;
    END
  END pin_data[496]
  PIN pin_data[497]
    DIRECTION OUTPUT ;
    USE SIGNAL ;
    PORT
      LAYER M4 ;
        RECT  43.116 85.296 43.2 85.32 ;
    END
  END pin_data[497]
  PIN pin_data[498]
    DIRECTION OUTPUT ;
    USE SIGNAL ;
    PORT
      LAYER M4 ;
        RECT  43.116 85.392 43.2 85.416 ;
    END
  END pin_data[498]
  PIN pin_data[499]
    DIRECTION OUTPUT ;
    USE SIGNAL ;
    PORT
      LAYER M4 ;
        RECT  43.116 85.488 43.2 85.512 ;
    END
  END pin_data[499]
  PIN pin_data[49]
    DIRECTION OUTPUT ;
    USE SIGNAL ;
    PORT
      LAYER M4 ;
        RECT  43.116 72.24 43.2 72.264 ;
    END
  END pin_data[49]
  PIN pin_data[4]
    DIRECTION OUTPUT ;
    USE SIGNAL ;
    PORT
      LAYER M4 ;
        RECT  43.116 58.704 43.2 58.728 ;
    END
  END pin_data[4]
  PIN pin_data[500]
    DIRECTION OUTPUT ;
    USE SIGNAL ;
    PORT
      LAYER M4 ;
        RECT  43.116 85.584 43.2 85.608 ;
    END
  END pin_data[500]
  PIN pin_data[501]
    DIRECTION OUTPUT ;
    USE SIGNAL ;
    PORT
      LAYER M4 ;
        RECT  43.116 85.68 43.2 85.704 ;
    END
  END pin_data[501]
  PIN pin_data[502]
    DIRECTION OUTPUT ;
    USE SIGNAL ;
    PORT
      LAYER M4 ;
        RECT  43.116 85.776 43.2 85.8 ;
    END
  END pin_data[502]
  PIN pin_data[503]
    DIRECTION OUTPUT ;
    USE SIGNAL ;
    PORT
      LAYER M4 ;
        RECT  43.116 85.872 43.2 85.896 ;
    END
  END pin_data[503]
  PIN pin_data[504]
    DIRECTION OUTPUT ;
    USE SIGNAL ;
    PORT
      LAYER M4 ;
        RECT  43.116 85.968 43.2 85.992 ;
    END
  END pin_data[504]
  PIN pin_data[505]
    DIRECTION OUTPUT ;
    USE SIGNAL ;
    PORT
      LAYER M4 ;
        RECT  43.116 86.064 43.2 86.088 ;
    END
  END pin_data[505]
  PIN pin_data[506]
    DIRECTION OUTPUT ;
    USE SIGNAL ;
    PORT
      LAYER M4 ;
        RECT  43.116 86.16 43.2 86.184 ;
    END
  END pin_data[506]
  PIN pin_data[507]
    DIRECTION OUTPUT ;
    USE SIGNAL ;
    PORT
      LAYER M4 ;
        RECT  43.116 86.256 43.2 86.28 ;
    END
  END pin_data[507]
  PIN pin_data[508]
    DIRECTION OUTPUT ;
    USE SIGNAL ;
    PORT
      LAYER M4 ;
        RECT  43.116 86.352 43.2 86.376 ;
    END
  END pin_data[508]
  PIN pin_data[509]
    DIRECTION OUTPUT ;
    USE SIGNAL ;
    PORT
      LAYER M4 ;
        RECT  43.116 86.448 43.2 86.472 ;
    END
  END pin_data[509]
  PIN pin_data[50]
    DIRECTION OUTPUT ;
    USE SIGNAL ;
    PORT
      LAYER M4 ;
        RECT  43.116 72.336 43.2 72.36 ;
    END
  END pin_data[50]
  PIN pin_data[510]
    DIRECTION OUTPUT ;
    USE SIGNAL ;
    PORT
      LAYER M4 ;
        RECT  43.116 86.544 43.2 86.568 ;
    END
  END pin_data[510]
  PIN pin_data[511]
    DIRECTION OUTPUT ;
    USE SIGNAL ;
    PORT
      LAYER M4 ;
        RECT  43.116 86.64 43.2 86.664 ;
    END
  END pin_data[511]
  PIN pin_data[51]
    DIRECTION OUTPUT ;
    USE SIGNAL ;
    PORT
      LAYER M4 ;
        RECT  43.116 72.432 43.2 72.456 ;
    END
  END pin_data[51]
  PIN pin_data[52]
    DIRECTION OUTPUT ;
    USE SIGNAL ;
    PORT
      LAYER M4 ;
        RECT  43.116 72.528 43.2 72.552 ;
    END
  END pin_data[52]
  PIN pin_data[53]
    DIRECTION OUTPUT ;
    USE SIGNAL ;
    PORT
      LAYER M4 ;
        RECT  43.116 72.624 43.2 72.648 ;
    END
  END pin_data[53]
  PIN pin_data[54]
    DIRECTION OUTPUT ;
    USE SIGNAL ;
    PORT
      LAYER M4 ;
        RECT  43.116 72.72 43.2 72.744 ;
    END
  END pin_data[54]
  PIN pin_data[55]
    DIRECTION OUTPUT ;
    USE SIGNAL ;
    PORT
      LAYER M4 ;
        RECT  43.116 72.816 43.2 72.84 ;
    END
  END pin_data[55]
  PIN pin_data[56]
    DIRECTION OUTPUT ;
    USE SIGNAL ;
    PORT
      LAYER M4 ;
        RECT  43.116 72.912 43.2 72.936 ;
    END
  END pin_data[56]
  PIN pin_data[57]
    DIRECTION OUTPUT ;
    USE SIGNAL ;
    PORT
      LAYER M4 ;
        RECT  43.116 73.008 43.2 73.032 ;
    END
  END pin_data[57]
  PIN pin_data[58]
    DIRECTION OUTPUT ;
    USE SIGNAL ;
    PORT
      LAYER M4 ;
        RECT  43.116 73.104 43.2 73.128 ;
    END
  END pin_data[58]
  PIN pin_data[59]
    DIRECTION OUTPUT ;
    USE SIGNAL ;
    PORT
      LAYER M4 ;
        RECT  43.116 73.2 43.2 73.224 ;
    END
  END pin_data[59]
  PIN pin_data[5]
    DIRECTION OUTPUT ;
    USE SIGNAL ;
    PORT
      LAYER M4 ;
        RECT  43.116 58.8 43.2 58.824 ;
    END
  END pin_data[5]
  PIN pin_data[60]
    DIRECTION OUTPUT ;
    USE SIGNAL ;
    PORT
      LAYER M4 ;
        RECT  43.116 73.296 43.2 73.32 ;
    END
  END pin_data[60]
  PIN pin_data[61]
    DIRECTION OUTPUT ;
    USE SIGNAL ;
    PORT
      LAYER M4 ;
        RECT  43.116 73.392 43.2 73.416 ;
    END
  END pin_data[61]
  PIN pin_data[62]
    DIRECTION OUTPUT ;
    USE SIGNAL ;
    PORT
      LAYER M4 ;
        RECT  43.116 73.488 43.2 73.512 ;
    END
  END pin_data[62]
  PIN pin_data[63]
    DIRECTION OUTPUT ;
    USE SIGNAL ;
    PORT
      LAYER M4 ;
        RECT  43.116 73.584 43.2 73.608 ;
    END
  END pin_data[63]
  PIN pin_data[64]
    DIRECTION OUTPUT ;
    USE SIGNAL ;
    PORT
      LAYER M4 ;
        RECT  43.116 64.464 43.2 64.488 ;
    END
  END pin_data[64]
  PIN pin_data[65]
    DIRECTION OUTPUT ;
    USE SIGNAL ;
    PORT
      LAYER M4 ;
        RECT  43.116 64.56 43.2 64.584 ;
    END
  END pin_data[65]
  PIN pin_data[66]
    DIRECTION OUTPUT ;
    USE SIGNAL ;
    PORT
      LAYER M4 ;
        RECT  43.116 64.656 43.2 64.68 ;
    END
  END pin_data[66]
  PIN pin_data[67]
    DIRECTION OUTPUT ;
    USE SIGNAL ;
    PORT
      LAYER M4 ;
        RECT  43.116 64.752 43.2 64.776 ;
    END
  END pin_data[67]
  PIN pin_data[68]
    DIRECTION OUTPUT ;
    USE SIGNAL ;
    PORT
      LAYER M4 ;
        RECT  43.116 64.848 43.2 64.872 ;
    END
  END pin_data[68]
  PIN pin_data[69]
    DIRECTION OUTPUT ;
    USE SIGNAL ;
    PORT
      LAYER M4 ;
        RECT  43.116 64.944 43.2 64.968 ;
    END
  END pin_data[69]
  PIN pin_data[6]
    DIRECTION OUTPUT ;
    USE SIGNAL ;
    PORT
      LAYER M4 ;
        RECT  43.116 58.896 43.2 58.92 ;
    END
  END pin_data[6]
  PIN pin_data[70]
    DIRECTION OUTPUT ;
    USE SIGNAL ;
    PORT
      LAYER M4 ;
        RECT  43.116 65.04 43.2 65.064 ;
    END
  END pin_data[70]
  PIN pin_data[71]
    DIRECTION OUTPUT ;
    USE SIGNAL ;
    PORT
      LAYER M4 ;
        RECT  43.116 65.136 43.2 65.16 ;
    END
  END pin_data[71]
  PIN pin_data[72]
    DIRECTION OUTPUT ;
    USE SIGNAL ;
    PORT
      LAYER M4 ;
        RECT  43.116 65.232 43.2 65.256 ;
    END
  END pin_data[72]
  PIN pin_data[73]
    DIRECTION OUTPUT ;
    USE SIGNAL ;
    PORT
      LAYER M4 ;
        RECT  43.116 65.328 43.2 65.352 ;
    END
  END pin_data[73]
  PIN pin_data[74]
    DIRECTION OUTPUT ;
    USE SIGNAL ;
    PORT
      LAYER M4 ;
        RECT  43.116 65.424 43.2 65.448 ;
    END
  END pin_data[74]
  PIN pin_data[75]
    DIRECTION OUTPUT ;
    USE SIGNAL ;
    PORT
      LAYER M4 ;
        RECT  43.116 65.52 43.2 65.544 ;
    END
  END pin_data[75]
  PIN pin_data[76]
    DIRECTION OUTPUT ;
    USE SIGNAL ;
    PORT
      LAYER M4 ;
        RECT  43.116 65.616 43.2 65.64 ;
    END
  END pin_data[76]
  PIN pin_data[77]
    DIRECTION OUTPUT ;
    USE SIGNAL ;
    PORT
      LAYER M4 ;
        RECT  43.116 65.712 43.2 65.736 ;
    END
  END pin_data[77]
  PIN pin_data[78]
    DIRECTION OUTPUT ;
    USE SIGNAL ;
    PORT
      LAYER M4 ;
        RECT  43.116 65.808 43.2 65.832 ;
    END
  END pin_data[78]
  PIN pin_data[79]
    DIRECTION OUTPUT ;
    USE SIGNAL ;
    PORT
      LAYER M4 ;
        RECT  43.116 65.904 43.2 65.928 ;
    END
  END pin_data[79]
  PIN pin_data[7]
    DIRECTION OUTPUT ;
    USE SIGNAL ;
    PORT
      LAYER M4 ;
        RECT  43.116 58.992 43.2 59.016 ;
    END
  END pin_data[7]
  PIN pin_data[80]
    DIRECTION OUTPUT ;
    USE SIGNAL ;
    PORT
      LAYER M4 ;
        RECT  43.116 66 43.2 66.024 ;
    END
  END pin_data[80]
  PIN pin_data[81]
    DIRECTION OUTPUT ;
    USE SIGNAL ;
    PORT
      LAYER M4 ;
        RECT  43.116 66.096 43.2 66.12 ;
    END
  END pin_data[81]
  PIN pin_data[82]
    DIRECTION OUTPUT ;
    USE SIGNAL ;
    PORT
      LAYER M4 ;
        RECT  43.116 66.192 43.2 66.216 ;
    END
  END pin_data[82]
  PIN pin_data[83]
    DIRECTION OUTPUT ;
    USE SIGNAL ;
    PORT
      LAYER M4 ;
        RECT  43.116 66.288 43.2 66.312 ;
    END
  END pin_data[83]
  PIN pin_data[84]
    DIRECTION OUTPUT ;
    USE SIGNAL ;
    PORT
      LAYER M4 ;
        RECT  43.116 66.384 43.2 66.408 ;
    END
  END pin_data[84]
  PIN pin_data[85]
    DIRECTION OUTPUT ;
    USE SIGNAL ;
    PORT
      LAYER M4 ;
        RECT  43.116 66.48 43.2 66.504 ;
    END
  END pin_data[85]
  PIN pin_data[86]
    DIRECTION OUTPUT ;
    USE SIGNAL ;
    PORT
      LAYER M4 ;
        RECT  43.116 66.576 43.2 66.6 ;
    END
  END pin_data[86]
  PIN pin_data[87]
    DIRECTION OUTPUT ;
    USE SIGNAL ;
    PORT
      LAYER M4 ;
        RECT  43.116 66.672 43.2 66.696 ;
    END
  END pin_data[87]
  PIN pin_data[88]
    DIRECTION OUTPUT ;
    USE SIGNAL ;
    PORT
      LAYER M4 ;
        RECT  43.116 66.768 43.2 66.792 ;
    END
  END pin_data[88]
  PIN pin_data[89]
    DIRECTION OUTPUT ;
    USE SIGNAL ;
    PORT
      LAYER M4 ;
        RECT  43.116 66.864 43.2 66.888 ;
    END
  END pin_data[89]
  PIN pin_data[8]
    DIRECTION OUTPUT ;
    USE SIGNAL ;
    PORT
      LAYER M4 ;
        RECT  43.116 59.088 43.2 59.112 ;
    END
  END pin_data[8]
  PIN pin_data[90]
    DIRECTION OUTPUT ;
    USE SIGNAL ;
    PORT
      LAYER M4 ;
        RECT  43.116 66.96 43.2 66.984 ;
    END
  END pin_data[90]
  PIN pin_data[91]
    DIRECTION OUTPUT ;
    USE SIGNAL ;
    PORT
      LAYER M4 ;
        RECT  43.116 67.056 43.2 67.08 ;
    END
  END pin_data[91]
  PIN pin_data[92]
    DIRECTION OUTPUT ;
    USE SIGNAL ;
    PORT
      LAYER M4 ;
        RECT  43.116 67.152 43.2 67.176 ;
    END
  END pin_data[92]
  PIN pin_data[93]
    DIRECTION OUTPUT ;
    USE SIGNAL ;
    PORT
      LAYER M4 ;
        RECT  43.116 67.248 43.2 67.272 ;
    END
  END pin_data[93]
  PIN pin_data[94]
    DIRECTION OUTPUT ;
    USE SIGNAL ;
    PORT
      LAYER M4 ;
        RECT  43.116 67.344 43.2 67.368 ;
    END
  END pin_data[94]
  PIN pin_data[95]
    DIRECTION OUTPUT ;
    USE SIGNAL ;
    PORT
      LAYER M4 ;
        RECT  43.116 67.44 43.2 67.464 ;
    END
  END pin_data[95]
  PIN pin_data[96]
    DIRECTION OUTPUT ;
    USE SIGNAL ;
    PORT
      LAYER M4 ;
        RECT  43.116 73.68 43.2 73.704 ;
    END
  END pin_data[96]
  PIN pin_data[97]
    DIRECTION OUTPUT ;
    USE SIGNAL ;
    PORT
      LAYER M4 ;
        RECT  43.116 73.776 43.2 73.8 ;
    END
  END pin_data[97]
  PIN pin_data[98]
    DIRECTION OUTPUT ;
    USE SIGNAL ;
    PORT
      LAYER M4 ;
        RECT  43.116 73.872 43.2 73.896 ;
    END
  END pin_data[98]
  PIN pin_data[99]
    DIRECTION OUTPUT ;
    USE SIGNAL ;
    PORT
      LAYER M4 ;
        RECT  43.116 73.968 43.2 73.992 ;
    END
  END pin_data[99]
  PIN pin_data[9]
    DIRECTION OUTPUT ;
    USE SIGNAL ;
    PORT
      LAYER M4 ;
        RECT  43.116 59.184 43.2 59.208 ;
    END
  END pin_data[9]
  PIN VDD
    DIRECTION INOUT ;
    USE POWER ;
    PORT
      LAYER M5 ;
        RECT  40.392 2.151 40.512 127.449 ;
        RECT  34.992 2.151 35.112 127.449 ;
        RECT  29.592 2.151 29.712 127.449 ;
        RECT  24.192 2.151 24.312 127.449 ;
        RECT  18.792 2.151 18.912 127.449 ;
        RECT  13.392 2.151 13.512 127.449 ;
        RECT  7.992 2.151 8.112 127.449 ;
        RECT  2.592 2.151 2.712 127.449 ;
    END
  END VDD
  PIN VSS
    DIRECTION INOUT ;
    USE GROUND ;
    PORT
      LAYER M5 ;
        RECT  40.2 2.137 40.32 127.463 ;
        RECT  34.8 2.137 34.92 127.463 ;
        RECT  29.4 2.137 29.52 127.463 ;
        RECT  24 2.137 24.12 127.463 ;
        RECT  18.6 2.137 18.72 127.463 ;
        RECT  13.2 2.137 13.32 127.463 ;
        RECT  7.8 2.137 7.92 127.463 ;
        RECT  2.4 2.137 2.52 127.463 ;
    END
  END VSS
  # OT_OBS_CLOSED layer=M5 d_um=1.536 added=30
  OBS
    LAYER RVTN ;
     RECT  2.16 2.16 41.04 2.295 ;
     RECT  2.16 2.565 41.04 2.835 ;
     RECT  2.16 3.105 41.04 3.375 ;
     RECT  2.16 3.645 41.04 3.915 ;
     RECT  2.16 4.185 41.04 4.455 ;
     RECT  2.16 4.725 41.04 4.995 ;
     RECT  2.16 5.265 41.04 5.535 ;
     RECT  2.16 5.805 41.04 6.075 ;
     RECT  2.16 6.345 41.04 6.615 ;
     RECT  2.16 6.885 41.04 7.155 ;
     RECT  2.16 7.425 41.04 7.695 ;
     RECT  2.16 7.965 41.04 8.235 ;
     RECT  2.16 8.505 41.04 8.775 ;
     RECT  2.16 9.045 41.04 9.315 ;
     RECT  2.16 9.585 41.04 9.855 ;
     RECT  2.16 10.125 41.04 10.395 ;
     RECT  2.16 10.665 41.04 10.935 ;
     RECT  2.16 11.205 41.04 11.475 ;
     RECT  2.16 11.745 41.04 12.015 ;
     RECT  2.16 12.285 41.04 12.555 ;
     RECT  2.16 12.825 41.04 13.095 ;
     RECT  2.16 13.365 41.04 13.635 ;
     RECT  2.16 13.905 41.04 14.175 ;
     RECT  2.16 14.445 41.04 14.715 ;
     RECT  2.16 14.985 41.04 15.255 ;
     RECT  2.16 15.525 41.04 15.795 ;
     RECT  2.16 16.065 41.04 16.335 ;
     RECT  2.16 16.605 41.04 16.875 ;
     RECT  2.16 17.145 41.04 17.415 ;
     RECT  2.16 17.685 41.04 17.955 ;
     RECT  2.16 18.225 41.04 18.495 ;
     RECT  2.16 18.765 41.04 19.035 ;
     RECT  2.16 19.305 41.04 19.575 ;
     RECT  2.16 19.845 41.04 20.115 ;
     RECT  2.16 20.385 41.04 20.655 ;
     RECT  2.16 20.925 41.04 21.195 ;
     RECT  2.16 21.465 41.04 21.735 ;
     RECT  2.16 22.005 41.04 22.275 ;
     RECT  2.16 22.545 41.04 22.815 ;
     RECT  2.16 23.085 41.04 23.355 ;
     RECT  2.16 23.625 41.04 23.895 ;
     RECT  2.16 24.165 41.04 24.435 ;
     RECT  2.16 24.705 41.04 24.975 ;
     RECT  2.16 25.245 41.04 25.515 ;
     RECT  2.16 25.785 41.04 26.055 ;
     RECT  2.16 26.325 41.04 26.595 ;
     RECT  2.16 26.865 41.04 27.135 ;
     RECT  2.16 27.405 41.04 27.675 ;
     RECT  2.16 27.945 41.04 28.215 ;
     RECT  2.16 28.485 41.04 28.755 ;
     RECT  2.16 29.025 41.04 29.295 ;
     RECT  2.16 29.565 41.04 29.835 ;
     RECT  2.16 30.105 41.04 30.375 ;
     RECT  2.16 30.645 41.04 30.915 ;
     RECT  2.16 31.185 41.04 31.455 ;
     RECT  2.16 31.725 41.04 31.995 ;
     RECT  2.16 32.265 41.04 32.535 ;
     RECT  2.16 32.805 41.04 33.075 ;
     RECT  2.16 33.345 41.04 33.615 ;
     RECT  2.16 33.885 41.04 34.155 ;
     RECT  2.16 34.425 41.04 34.695 ;
     RECT  2.16 34.965 41.04 35.235 ;
     RECT  2.16 35.505 41.04 35.775 ;
     RECT  2.16 36.045 41.04 36.315 ;
     RECT  2.16 36.585 41.04 36.855 ;
     RECT  2.16 37.125 41.04 37.395 ;
     RECT  2.16 37.665 41.04 37.935 ;
     RECT  2.16 38.205 41.04 38.475 ;
     RECT  2.16 38.745 41.04 39.015 ;
     RECT  2.16 39.285 41.04 39.555 ;
     RECT  2.16 39.825 41.04 40.095 ;
     RECT  2.16 40.365 41.04 40.635 ;
     RECT  2.16 40.905 41.04 41.175 ;
     RECT  2.16 41.445 41.04 41.715 ;
     RECT  2.16 41.985 41.04 42.255 ;
     RECT  2.16 42.525 41.04 42.795 ;
     RECT  2.16 43.065 41.04 43.335 ;
     RECT  2.16 43.605 41.04 43.875 ;
     RECT  2.16 44.145 41.04 44.415 ;
     RECT  2.16 44.685 41.04 44.955 ;
     RECT  2.16 45.225 41.04 45.495 ;
     RECT  2.16 45.765 41.04 46.035 ;
     RECT  2.16 46.305 41.04 46.575 ;
     RECT  2.16 46.845 41.04 47.115 ;
     RECT  2.16 47.385 41.04 47.655 ;
     RECT  2.16 47.925 41.04 48.195 ;
     RECT  2.16 48.465 41.04 48.735 ;
     RECT  2.16 49.005 41.04 49.275 ;
     RECT  2.16 49.545 41.04 49.815 ;
     RECT  2.16 50.085 41.04 50.355 ;
     RECT  2.16 50.625 41.04 50.895 ;
     RECT  2.16 51.165 41.04 51.435 ;
     RECT  2.16 51.705 41.04 51.975 ;
     RECT  2.16 52.245 41.04 52.515 ;
     RECT  2.16 52.785 41.04 53.055 ;
     RECT  2.16 53.325 41.04 53.595 ;
     RECT  2.16 53.865 41.04 54.135 ;
     RECT  2.16 54.405 41.04 54.675 ;
     RECT  2.16 54.945 41.04 55.215 ;
     RECT  2.16 55.485 41.04 55.755 ;
     RECT  2.16 56.025 41.04 56.295 ;
     RECT  2.16 56.565 41.04 56.835 ;
     RECT  2.16 57.105 41.04 57.375 ;
     RECT  2.16 57.645 41.04 57.915 ;
     RECT  2.16 58.185 41.04 58.455 ;
     RECT  2.16 58.725 41.04 58.995 ;
     RECT  2.16 59.265 41.04 59.535 ;
     RECT  2.16 59.805 41.04 60.075 ;
     RECT  2.16 60.345 41.04 60.615 ;
     RECT  2.16 60.885 41.04 61.155 ;
     RECT  2.16 61.425 41.04 61.695 ;
     RECT  2.16 61.965 41.04 62.235 ;
     RECT  2.16 62.505 41.04 62.775 ;
     RECT  2.16 63.045 41.04 63.315 ;
     RECT  2.16 63.585 41.04 63.855 ;
     RECT  2.16 64.125 41.04 64.395 ;
     RECT  2.16 64.665 41.04 64.935 ;
     RECT  2.16 65.205 41.04 65.475 ;
     RECT  2.16 65.745 41.04 66.015 ;
     RECT  2.16 66.285 41.04 66.555 ;
     RECT  2.16 66.825 41.04 67.095 ;
     RECT  2.16 67.365 41.04 67.635 ;
     RECT  2.16 67.905 41.04 68.175 ;
     RECT  2.16 68.445 41.04 68.715 ;
     RECT  2.16 68.985 41.04 69.255 ;
     RECT  2.16 69.525 41.04 69.795 ;
     RECT  2.16 70.065 41.04 70.335 ;
     RECT  2.16 70.605 41.04 70.875 ;
     RECT  2.16 71.145 41.04 71.415 ;
     RECT  2.16 71.685 41.04 71.955 ;
     RECT  2.16 72.225 41.04 72.495 ;
     RECT  2.16 72.765 41.04 73.035 ;
     RECT  2.16 73.305 41.04 73.575 ;
     RECT  2.16 73.845 41.04 74.115 ;
     RECT  2.16 74.385 41.04 74.655 ;
     RECT  2.16 74.925 41.04 75.195 ;
     RECT  2.16 75.465 41.04 75.735 ;
     RECT  2.16 76.005 41.04 76.275 ;
     RECT  2.16 76.545 41.04 76.815 ;
     RECT  2.16 77.085 41.04 77.355 ;
     RECT  2.16 77.625 41.04 77.895 ;
     RECT  2.16 78.165 41.04 78.435 ;
     RECT  2.16 78.705 41.04 78.975 ;
     RECT  2.16 79.245 41.04 79.515 ;
     RECT  2.16 79.785 41.04 80.055 ;
     RECT  2.16 80.325 41.04 80.595 ;
     RECT  2.16 80.865 41.04 81.135 ;
     RECT  2.16 81.405 41.04 81.675 ;
     RECT  2.16 81.945 41.04 82.215 ;
     RECT  2.16 82.485 41.04 82.755 ;
     RECT  2.16 83.025 41.04 83.295 ;
     RECT  2.16 83.565 41.04 83.835 ;
     RECT  2.16 84.105 41.04 84.375 ;
     RECT  2.16 84.645 41.04 84.915 ;
     RECT  2.16 85.185 41.04 85.455 ;
     RECT  2.16 85.725 41.04 85.995 ;
     RECT  2.16 86.265 41.04 86.535 ;
     RECT  2.16 86.805 41.04 87.075 ;
     RECT  2.16 87.345 41.04 87.615 ;
     RECT  2.16 87.885 41.04 88.155 ;
     RECT  2.16 88.425 41.04 88.695 ;
     RECT  2.16 88.965 41.04 89.235 ;
     RECT  2.16 89.505 41.04 89.775 ;
     RECT  2.16 90.045 41.04 90.315 ;
     RECT  2.16 90.585 41.04 90.855 ;
     RECT  2.16 91.125 41.04 91.395 ;
     RECT  2.16 91.665 41.04 91.935 ;
     RECT  2.16 92.205 41.04 92.475 ;
     RECT  2.16 92.745 41.04 93.015 ;
     RECT  2.16 93.285 41.04 93.555 ;
     RECT  2.16 93.825 41.04 94.095 ;
     RECT  2.16 94.365 41.04 94.635 ;
     RECT  2.16 94.905 41.04 95.175 ;
     RECT  2.16 95.445 41.04 95.715 ;
     RECT  2.16 95.985 41.04 96.255 ;
     RECT  2.16 96.525 41.04 96.795 ;
     RECT  2.16 97.065 41.04 97.335 ;
     RECT  2.16 97.605 41.04 97.875 ;
     RECT  2.16 98.145 41.04 98.415 ;
     RECT  2.16 98.685 41.04 98.955 ;
     RECT  2.16 99.225 41.04 99.495 ;
     RECT  2.16 99.765 41.04 100.035 ;
     RECT  2.16 100.305 41.04 100.575 ;
     RECT  2.16 100.845 41.04 101.115 ;
     RECT  2.16 101.385 41.04 101.655 ;
     RECT  2.16 101.925 41.04 102.195 ;
     RECT  2.16 102.465 41.04 102.735 ;
     RECT  2.16 103.005 41.04 103.275 ;
     RECT  2.16 103.545 41.04 103.815 ;
     RECT  2.16 104.085 41.04 104.355 ;
     RECT  2.16 104.625 41.04 104.895 ;
     RECT  2.16 105.165 41.04 105.435 ;
     RECT  2.16 105.705 41.04 105.975 ;
     RECT  2.16 106.245 41.04 106.515 ;
     RECT  2.16 106.785 41.04 107.055 ;
     RECT  2.16 107.325 41.04 107.595 ;
     RECT  2.16 107.865 41.04 108.135 ;
     RECT  2.16 108.405 41.04 108.675 ;
     RECT  2.16 108.945 41.04 109.215 ;
     RECT  2.16 109.485 41.04 109.755 ;
     RECT  2.16 110.025 41.04 110.295 ;
     RECT  2.16 110.565 41.04 110.835 ;
     RECT  2.16 111.105 41.04 111.375 ;
     RECT  2.16 111.645 41.04 111.915 ;
     RECT  2.16 112.185 41.04 112.455 ;
     RECT  2.16 112.725 41.04 112.995 ;
     RECT  2.16 113.265 41.04 113.535 ;
     RECT  2.16 113.805 41.04 114.075 ;
     RECT  2.16 114.345 41.04 114.615 ;
     RECT  2.16 114.885 41.04 115.155 ;
     RECT  2.16 115.425 41.04 115.695 ;
     RECT  2.16 115.965 41.04 116.235 ;
     RECT  2.16 116.505 41.04 116.775 ;
     RECT  2.16 117.045 41.04 117.315 ;
     RECT  2.16 117.585 41.04 117.855 ;
     RECT  2.16 118.125 41.04 118.395 ;
     RECT  2.16 118.665 41.04 118.935 ;
     RECT  2.16 119.205 41.04 119.475 ;
     RECT  2.16 119.745 41.04 120.015 ;
     RECT  2.16 120.285 41.04 120.555 ;
     RECT  2.16 120.825 41.04 121.095 ;
     RECT  2.16 121.365 41.04 121.635 ;
     RECT  2.16 121.905 41.04 122.175 ;
     RECT  2.16 122.445 41.04 122.715 ;
     RECT  2.16 122.985 41.04 123.255 ;
     RECT  2.16 123.525 41.04 123.795 ;
     RECT  2.16 124.065 41.04 124.335 ;
     RECT  2.16 124.605 41.04 124.875 ;
     RECT  2.16 125.145 41.04 125.415 ;
     RECT  2.16 125.685 41.04 125.955 ;
     RECT  2.16 126.225 41.04 126.495 ;
     RECT  2.16 126.765 41.04 127.035 ;
     RECT  2.16 127.305 41.04 127.44 ;
    LAYER RVTP ;
     RECT  2.16 2.295 41.04 2.565 ;
     RECT  2.16 2.835 41.04 3.105 ;
     RECT  2.16 3.375 41.04 3.645 ;
     RECT  2.16 3.915 41.04 4.185 ;
     RECT  2.16 4.455 41.04 4.725 ;
     RECT  2.16 4.995 41.04 5.265 ;
     RECT  2.16 5.535 41.04 5.805 ;
     RECT  2.16 6.075 41.04 6.345 ;
     RECT  2.16 6.615 41.04 6.885 ;
     RECT  2.16 7.155 41.04 7.425 ;
     RECT  2.16 7.695 41.04 7.965 ;
     RECT  2.16 8.235 41.04 8.505 ;
     RECT  2.16 8.775 41.04 9.045 ;
     RECT  2.16 9.315 41.04 9.585 ;
     RECT  2.16 9.855 41.04 10.125 ;
     RECT  2.16 10.395 41.04 10.665 ;
     RECT  2.16 10.935 41.04 11.205 ;
     RECT  2.16 11.475 41.04 11.745 ;
     RECT  2.16 12.015 41.04 12.285 ;
     RECT  2.16 12.555 41.04 12.825 ;
     RECT  2.16 13.095 41.04 13.365 ;
     RECT  2.16 13.635 41.04 13.905 ;
     RECT  2.16 14.175 41.04 14.445 ;
     RECT  2.16 14.715 41.04 14.985 ;
     RECT  2.16 15.255 41.04 15.525 ;
     RECT  2.16 15.795 41.04 16.065 ;
     RECT  2.16 16.335 41.04 16.605 ;
     RECT  2.16 16.875 41.04 17.145 ;
     RECT  2.16 17.415 41.04 17.685 ;
     RECT  2.16 17.955 41.04 18.225 ;
     RECT  2.16 18.495 41.04 18.765 ;
     RECT  2.16 19.035 41.04 19.305 ;
     RECT  2.16 19.575 41.04 19.845 ;
     RECT  2.16 20.115 41.04 20.385 ;
     RECT  2.16 20.655 41.04 20.925 ;
     RECT  2.16 21.195 41.04 21.465 ;
     RECT  2.16 21.735 41.04 22.005 ;
     RECT  2.16 22.275 41.04 22.545 ;
     RECT  2.16 22.815 41.04 23.085 ;
     RECT  2.16 23.355 41.04 23.625 ;
     RECT  2.16 23.895 41.04 24.165 ;
     RECT  2.16 24.435 41.04 24.705 ;
     RECT  2.16 24.975 41.04 25.245 ;
     RECT  2.16 25.515 41.04 25.785 ;
     RECT  2.16 26.055 41.04 26.325 ;
     RECT  2.16 26.595 41.04 26.865 ;
     RECT  2.16 27.135 41.04 27.405 ;
     RECT  2.16 27.675 41.04 27.945 ;
     RECT  2.16 28.215 41.04 28.485 ;
     RECT  2.16 28.755 41.04 29.025 ;
     RECT  2.16 29.295 41.04 29.565 ;
     RECT  2.16 29.835 41.04 30.105 ;
     RECT  2.16 30.375 41.04 30.645 ;
     RECT  2.16 30.915 41.04 31.185 ;
     RECT  2.16 31.455 41.04 31.725 ;
     RECT  2.16 31.995 41.04 32.265 ;
     RECT  2.16 32.535 41.04 32.805 ;
     RECT  2.16 33.075 41.04 33.345 ;
     RECT  2.16 33.615 41.04 33.885 ;
     RECT  2.16 34.155 41.04 34.425 ;
     RECT  2.16 34.695 41.04 34.965 ;
     RECT  2.16 35.235 41.04 35.505 ;
     RECT  2.16 35.775 41.04 36.045 ;
     RECT  2.16 36.315 41.04 36.585 ;
     RECT  2.16 36.855 41.04 37.125 ;
     RECT  2.16 37.395 41.04 37.665 ;
     RECT  2.16 37.935 41.04 38.205 ;
     RECT  2.16 38.475 41.04 38.745 ;
     RECT  2.16 39.015 41.04 39.285 ;
     RECT  2.16 39.555 41.04 39.825 ;
     RECT  2.16 40.095 41.04 40.365 ;
     RECT  2.16 40.635 41.04 40.905 ;
     RECT  2.16 41.175 41.04 41.445 ;
     RECT  2.16 41.715 41.04 41.985 ;
     RECT  2.16 42.255 41.04 42.525 ;
     RECT  2.16 42.795 41.04 43.065 ;
     RECT  2.16 43.335 41.04 43.605 ;
     RECT  2.16 43.875 41.04 44.145 ;
     RECT  2.16 44.415 41.04 44.685 ;
     RECT  2.16 44.955 41.04 45.225 ;
     RECT  2.16 45.495 41.04 45.765 ;
     RECT  2.16 46.035 41.04 46.305 ;
     RECT  2.16 46.575 41.04 46.845 ;
     RECT  2.16 47.115 41.04 47.385 ;
     RECT  2.16 47.655 41.04 47.925 ;
     RECT  2.16 48.195 41.04 48.465 ;
     RECT  2.16 48.735 41.04 49.005 ;
     RECT  2.16 49.275 41.04 49.545 ;
     RECT  2.16 49.815 41.04 50.085 ;
     RECT  2.16 50.355 41.04 50.625 ;
     RECT  2.16 50.895 41.04 51.165 ;
     RECT  2.16 51.435 41.04 51.705 ;
     RECT  2.16 51.975 41.04 52.245 ;
     RECT  2.16 52.515 41.04 52.785 ;
     RECT  2.16 53.055 41.04 53.325 ;
     RECT  2.16 53.595 41.04 53.865 ;
     RECT  2.16 54.135 41.04 54.405 ;
     RECT  2.16 54.675 41.04 54.945 ;
     RECT  2.16 55.215 41.04 55.485 ;
     RECT  2.16 55.755 41.04 56.025 ;
     RECT  2.16 56.295 41.04 56.565 ;
     RECT  2.16 56.835 41.04 57.105 ;
     RECT  2.16 57.375 41.04 57.645 ;
     RECT  2.16 57.915 41.04 58.185 ;
     RECT  2.16 58.455 41.04 58.725 ;
     RECT  2.16 58.995 41.04 59.265 ;
     RECT  2.16 59.535 41.04 59.805 ;
     RECT  2.16 60.075 41.04 60.345 ;
     RECT  2.16 60.615 41.04 60.885 ;
     RECT  2.16 61.155 41.04 61.425 ;
     RECT  2.16 61.695 41.04 61.965 ;
     RECT  2.16 62.235 41.04 62.505 ;
     RECT  2.16 62.775 41.04 63.045 ;
     RECT  2.16 63.315 41.04 63.585 ;
     RECT  2.16 63.855 41.04 64.125 ;
     RECT  2.16 64.395 41.04 64.665 ;
     RECT  2.16 64.935 41.04 65.205 ;
     RECT  2.16 65.475 41.04 65.745 ;
     RECT  2.16 66.015 41.04 66.285 ;
     RECT  2.16 66.555 41.04 66.825 ;
     RECT  2.16 67.095 41.04 67.365 ;
     RECT  2.16 67.635 41.04 67.905 ;
     RECT  2.16 68.175 41.04 68.445 ;
     RECT  2.16 68.715 41.04 68.985 ;
     RECT  2.16 69.255 41.04 69.525 ;
     RECT  2.16 69.795 41.04 70.065 ;
     RECT  2.16 70.335 41.04 70.605 ;
     RECT  2.16 70.875 41.04 71.145 ;
     RECT  2.16 71.415 41.04 71.685 ;
     RECT  2.16 71.955 41.04 72.225 ;
     RECT  2.16 72.495 41.04 72.765 ;
     RECT  2.16 73.035 41.04 73.305 ;
     RECT  2.16 73.575 41.04 73.845 ;
     RECT  2.16 74.115 41.04 74.385 ;
     RECT  2.16 74.655 41.04 74.925 ;
     RECT  2.16 75.195 41.04 75.465 ;
     RECT  2.16 75.735 41.04 76.005 ;
     RECT  2.16 76.275 41.04 76.545 ;
     RECT  2.16 76.815 41.04 77.085 ;
     RECT  2.16 77.355 41.04 77.625 ;
     RECT  2.16 77.895 41.04 78.165 ;
     RECT  2.16 78.435 41.04 78.705 ;
     RECT  2.16 78.975 41.04 79.245 ;
     RECT  2.16 79.515 41.04 79.785 ;
     RECT  2.16 80.055 41.04 80.325 ;
     RECT  2.16 80.595 41.04 80.865 ;
     RECT  2.16 81.135 41.04 81.405 ;
     RECT  2.16 81.675 41.04 81.945 ;
     RECT  2.16 82.215 41.04 82.485 ;
     RECT  2.16 82.755 41.04 83.025 ;
     RECT  2.16 83.295 41.04 83.565 ;
     RECT  2.16 83.835 41.04 84.105 ;
     RECT  2.16 84.375 41.04 84.645 ;
     RECT  2.16 84.915 41.04 85.185 ;
     RECT  2.16 85.455 41.04 85.725 ;
     RECT  2.16 85.995 41.04 86.265 ;
     RECT  2.16 86.535 41.04 86.805 ;
     RECT  2.16 87.075 41.04 87.345 ;
     RECT  2.16 87.615 41.04 87.885 ;
     RECT  2.16 88.155 41.04 88.425 ;
     RECT  2.16 88.695 41.04 88.965 ;
     RECT  2.16 89.235 41.04 89.505 ;
     RECT  2.16 89.775 41.04 90.045 ;
     RECT  2.16 90.315 41.04 90.585 ;
     RECT  2.16 90.855 41.04 91.125 ;
     RECT  2.16 91.395 41.04 91.665 ;
     RECT  2.16 91.935 41.04 92.205 ;
     RECT  2.16 92.475 41.04 92.745 ;
     RECT  2.16 93.015 41.04 93.285 ;
     RECT  2.16 93.555 41.04 93.825 ;
     RECT  2.16 94.095 41.04 94.365 ;
     RECT  2.16 94.635 41.04 94.905 ;
     RECT  2.16 95.175 41.04 95.445 ;
     RECT  2.16 95.715 41.04 95.985 ;
     RECT  2.16 96.255 41.04 96.525 ;
     RECT  2.16 96.795 41.04 97.065 ;
     RECT  2.16 97.335 41.04 97.605 ;
     RECT  2.16 97.875 41.04 98.145 ;
     RECT  2.16 98.415 41.04 98.685 ;
     RECT  2.16 98.955 41.04 99.225 ;
     RECT  2.16 99.495 41.04 99.765 ;
     RECT  2.16 100.035 41.04 100.305 ;
     RECT  2.16 100.575 41.04 100.845 ;
     RECT  2.16 101.115 41.04 101.385 ;
     RECT  2.16 101.655 41.04 101.925 ;
     RECT  2.16 102.195 41.04 102.465 ;
     RECT  2.16 102.735 41.04 103.005 ;
     RECT  2.16 103.275 41.04 103.545 ;
     RECT  2.16 103.815 41.04 104.085 ;
     RECT  2.16 104.355 41.04 104.625 ;
     RECT  2.16 104.895 41.04 105.165 ;
     RECT  2.16 105.435 41.04 105.705 ;
     RECT  2.16 105.975 41.04 106.245 ;
     RECT  2.16 106.515 41.04 106.785 ;
     RECT  2.16 107.055 41.04 107.325 ;
     RECT  2.16 107.595 41.04 107.865 ;
     RECT  2.16 108.135 41.04 108.405 ;
     RECT  2.16 108.675 41.04 108.945 ;
     RECT  2.16 109.215 41.04 109.485 ;
     RECT  2.16 109.755 41.04 110.025 ;
     RECT  2.16 110.295 41.04 110.565 ;
     RECT  2.16 110.835 41.04 111.105 ;
     RECT  2.16 111.375 41.04 111.645 ;
     RECT  2.16 111.915 41.04 112.185 ;
     RECT  2.16 112.455 41.04 112.725 ;
     RECT  2.16 112.995 41.04 113.265 ;
     RECT  2.16 113.535 41.04 113.805 ;
     RECT  2.16 114.075 41.04 114.345 ;
     RECT  2.16 114.615 41.04 114.885 ;
     RECT  2.16 115.155 41.04 115.425 ;
     RECT  2.16 115.695 41.04 115.965 ;
     RECT  2.16 116.235 41.04 116.505 ;
     RECT  2.16 116.775 41.04 117.045 ;
     RECT  2.16 117.315 41.04 117.585 ;
     RECT  2.16 117.855 41.04 118.125 ;
     RECT  2.16 118.395 41.04 118.665 ;
     RECT  2.16 118.935 41.04 119.205 ;
     RECT  2.16 119.475 41.04 119.745 ;
     RECT  2.16 120.015 41.04 120.285 ;
     RECT  2.16 120.555 41.04 120.825 ;
     RECT  2.16 121.095 41.04 121.365 ;
     RECT  2.16 121.635 41.04 121.905 ;
     RECT  2.16 122.175 41.04 122.445 ;
     RECT  2.16 122.715 41.04 122.985 ;
     RECT  2.16 123.255 41.04 123.525 ;
     RECT  2.16 123.795 41.04 124.065 ;
     RECT  2.16 124.335 41.04 124.605 ;
     RECT  2.16 124.875 41.04 125.145 ;
     RECT  2.16 125.415 41.04 125.685 ;
     RECT  2.16 125.955 41.04 126.225 ;
     RECT  2.16 126.495 41.04 126.765 ;
     RECT  2.16 127.035 41.04 127.305 ;
    LAYER M1 ;
     RECT  2.16 2.151 41.04 127.449 ;
    LAYER M2 ;
     RECT  0.067 92.412 0.103 92.43 ;
     RECT  0.103 38.682 0.139 38.7 ;
     RECT  0.103 40.95 0.139 40.968 ;
     RECT  0.103 41.994 0.139 43.83 ;
     RECT  0.103 44.928 0.139 44.946 ;
     RECT  0.103 46.008 0.139 46.026 ;
     RECT  0.103 71.46 0.139 71.478 ;
     RECT  0.103 76.212 0.139 76.23 ;
     RECT  0.103 49.482 0.175 49.842 ;
     RECT  0.103 52.992 0.175 53.388 ;
     RECT  0.103 54.45 0.175 55.17 ;
     RECT  0.139 56.772 0.175 56.79 ;
     RECT  0.103 72.81 0.175 72.828 ;
     RECT  0.103 73.746 0.175 74.106 ;
     RECT  0.139 75.942 0.175 76.23 ;
     RECT  0.103 50.904 0.203 51.228 ;
     RECT  0.067 89.82 0.203 89.838 ;
     RECT  0.139 38.682 0.211 39.24 ;
     RECT  0.211 38.682 0.247 39.618 ;
     RECT  0.139 40.41 0.247 40.968 ;
     RECT  0.139 41.922 0.247 43.83 ;
     RECT  0.203 51.21 0.311 51.228 ;
     RECT  0.103 67.41 0.347 67.428 ;
     RECT  0.175 75.942 0.499 76.536 ;
     RECT  0.247 38.682 0.535 43.83 ;
     RECT  0.139 44.694 0.535 44.946 ;
     RECT  0.139 46.008 0.535 46.062 ;
     RECT  0.103 47.124 0.535 47.142 ;
     RECT  0.463 48.204 0.535 48.222 ;
     RECT  0.175 49.482 0.535 50.148 ;
     RECT  0.175 52.992 0.535 55.17 ;
     RECT  0.175 56.232 0.535 56.79 ;
     RECT  0.499 57.924 0.535 59.022 ;
     RECT  0.103 63.252 0.535 63.846 ;
     RECT  0.103 68.922 0.535 69.48 ;
     RECT  0.175 72.81 0.535 74.106 ;
     RECT  0.499 75.204 0.535 76.536 ;
     RECT  0.499 80.136 0.535 80.154 ;
     RECT  0.103 80.91 0.535 80.928 ;
     RECT  0.499 81.72 0.535 81.738 ;
     RECT  0.103 82.566 0.535 82.584 ;
     RECT  0.103 91.872 1.147 92.43 ;
     RECT  1.291 86.814 1.435 86.832 ;
     RECT  0.535 46.008 1.723 46.098 ;
     RECT  1.399 67.914 1.723 67.932 ;
     RECT  1.291 90.864 1.723 90.882 ;
     RECT  1.723 45.81 2.047 46.098 ;
     RECT  0.535 47.124 2.047 50.148 ;
     RECT  0.535 52.866 2.047 55.17 ;
     RECT  0.535 62.01 2.047 62.028 ;
     RECT  0.535 62.856 2.047 63.846 ;
     RECT  0.535 64.746 2.047 64.764 ;
     RECT  0.103 66.096 2.047 66.114 ;
     RECT  1.723 67.572 2.047 67.932 ;
     RECT  0.535 68.796 2.047 69.48 ;
     RECT  0.103 78.48 2.047 79.236 ;
     RECT  2.047 77.904 2.119 79.236 ;
     RECT  0.535 80.136 2.119 80.928 ;
     RECT  0.535 38.682 2.16 44.946 ;
     RECT  2.047 45.81 2.16 50.148 ;
     RECT  2.047 51.912 2.16 51.93 ;
     RECT  2.047 52.83 2.16 55.17 ;
     RECT  0.535 56.232 2.16 57.168 ;
     RECT  0.535 57.924 2.16 59.094 ;
     RECT  2.047 60.084 2.16 60.84 ;
     RECT  2.047 62.01 2.16 63.846 ;
     RECT  2.047 64.746 2.16 64.89 ;
     RECT  2.047 65.952 2.16 66.78 ;
     RECT  2.047 67.572 2.16 69.48 ;
     RECT  0.139 71.46 2.16 72.018 ;
     RECT  0.535 72.81 2.16 76.536 ;
     RECT  2.119 77.904 2.16 80.928 ;
     RECT  0.535 81.72 2.16 82.584 ;
     RECT  0.103 83.772 2.16 83.79 ;
     RECT  0.103 85.968 2.16 85.986 ;
     RECT  1.435 86.814 2.16 86.868 ;
     RECT  0.103 88.902 2.16 88.92 ;
     RECT  1.723 90.864 2.16 90.918 ;
     RECT  1.147 91.872 2.16 92.7 ;
     RECT  2.16 2.151 41.04 127.449 ;
     RECT  41.04 35.316 41.315 37.494 ;
     RECT  41.04 92.646 41.315 93.204 ;
     RECT  41.315 35.316 41.351 35.334 ;
     RECT  41.315 92.646 41.387 92.934 ;
     RECT  41.04 38.754 41.495 65.43 ;
     RECT  41.315 36.126 41.603 37.494 ;
     RECT  41.04 66.456 41.603 91.584 ;
     RECT  41.495 38.826 41.675 65.43 ;
     RECT  41.603 36.666 41.891 37.494 ;
     RECT  41.675 39.87 42.107 65.43 ;
     RECT  42.107 39.87 42.143 52.074 ;
     RECT  42.107 52.83 42.143 65.43 ;
     RECT  41.603 66.456 42.143 83.628 ;
     RECT  41.603 90.666 42.143 91.584 ;
     RECT  42.143 40.068 42.179 52.074 ;
     RECT  42.143 52.866 42.179 55.134 ;
     RECT  42.143 55.998 42.179 65.43 ;
     RECT  42.143 66.456 42.179 71.334 ;
     RECT  42.143 72.234 42.179 75.798 ;
     RECT  42.143 77.904 42.179 83.628 ;
     RECT  41.603 84.384 42.179 89.874 ;
     RECT  41.891 36.666 42.215 36.954 ;
     RECT  42.179 41.148 42.215 44.676 ;
     RECT  42.179 50.868 42.215 51.192 ;
     RECT  42.179 51.984 42.215 52.002 ;
     RECT  42.179 52.866 42.215 54.774 ;
     RECT  42.179 56.34 42.215 57.204 ;
     RECT  42.179 59.31 42.215 61.344 ;
     RECT  42.179 64.098 42.215 65.196 ;
     RECT  42.179 68.76 42.215 70.632 ;
     RECT  42.179 74.124 42.215 74.376 ;
     RECT  42.179 77.976 42.215 79.164 ;
     RECT  42.179 80.136 42.215 82.134 ;
     RECT  42.179 86.238 42.215 89.874 ;
     RECT  42.215 36.666 42.251 36.684 ;
     RECT  42.179 66.6 42.251 66.618 ;
     RECT  42.215 70.416 42.251 70.632 ;
     RECT  42.215 74.286 42.251 74.376 ;
     RECT  42.215 78.246 42.251 79.164 ;
     RECT  42.215 80.181 42.251 81.774 ;
     RECT  42.215 86.238 42.251 87.066 ;
     RECT  41.675 38.826 42.287 38.844 ;
     RECT  42.215 59.472 42.287 61.344 ;
     RECT  42.179 62.406 42.287 63.342 ;
     RECT  42.179 83.196 42.943 83.628 ;
     RECT  42.251 70.614 43.015 70.632 ;
     RECT  42.215 69.498 43.043 69.516 ;
     RECT  42.251 87.048 43.043 87.066 ;
     RECT  42.215 87.93 43.043 89.874 ;
     RECT  42.179 40.068 43.079 40.194 ;
     RECT  42.215 41.148 43.079 44.136 ;
     RECT  42.179 45.576 43.079 45.684 ;
     RECT  42.179 47.628 43.079 50.004 ;
     RECT  42.215 50.868 43.079 50.886 ;
     RECT  42.215 54.576 43.079 54.774 ;
     RECT  42.287 60.894 43.079 61.344 ;
     RECT  42.215 64.746 43.079 64.998 ;
     RECT  42.179 75.366 43.079 75.798 ;
     RECT  42.251 78.372 43.079 79.164 ;
     RECT  42.943 82.998 43.079 83.628 ;
     RECT  43.043 88.398 43.079 89.874 ;
     RECT  42.143 91.296 43.079 91.584 ;
     RECT  43.079 40.068 43.115 40.086 ;
     RECT  43.079 41.148 43.115 43.326 ;
     RECT  43.079 44.118 43.115 44.136 ;
     RECT  43.079 45.666 43.115 45.684 ;
     RECT  43.079 48.474 43.115 49.104 ;
     RECT  43.079 49.986 43.115 50.004 ;
     RECT  43.015 51.678 43.115 51.696 ;
     RECT  43.079 54.576 43.115 54.594 ;
     RECT  42.215 57.006 43.115 57.024 ;
     RECT  42.179 58.122 43.115 58.14 ;
     RECT  42.287 59.472 43.115 59.904 ;
     RECT  43.079 60.894 43.115 60.912 ;
     RECT  42.287 63.054 43.115 63.342 ;
     RECT  43.079 64.98 43.115 64.998 ;
     RECT  42.179 67.374 43.115 67.734 ;
     RECT  43.015 70.614 43.115 71.136 ;
     RECT  42.179 72.234 43.115 73.296 ;
     RECT  42.251 74.286 43.115 74.304 ;
     RECT  43.079 75.366 43.115 75.384 ;
     RECT  42.143 76.986 43.115 77.004 ;
     RECT  43.079 78.642 43.115 79.164 ;
     RECT  42.251 80.181 43.115 80.199 ;
     RECT  42.251 81.036 43.115 81.054 ;
     RECT  43.079 83.61 43.115 83.628 ;
     RECT  42.179 84.384 43.115 84.402 ;
     RECT  42.251 86.238 43.115 86.256 ;
     RECT  43.079 88.668 43.115 89.424 ;
     RECT  43.079 91.296 43.115 91.314 ;
     RECT  41.387 92.646 43.187 92.664 ;
    LAYER M3 ;
     RECT  2.415 2.143 2.505 2.413 ;
     RECT  7.815 2.143 7.905 2.413 ;
     RECT  13.215 2.143 13.305 2.413 ;
     RECT  18.615 2.143 18.705 2.413 ;
     RECT  24.015 2.143 24.105 2.413 ;
     RECT  29.415 2.143 29.505 2.413 ;
     RECT  34.815 2.143 34.905 2.413 ;
     RECT  40.215 2.143 40.305 2.413 ;
     RECT  40.215 2.413 40.497 35.581 ;
     RECT  39.816 35.581 40.497 35.815 ;
     RECT  39.816 35.815 40.59 35.851 ;
     RECT  41.328 35.311 41.346 35.851 ;
     RECT  39.564 35.851 41.346 36.121 ;
     RECT  39.456 36.121 41.598 36.211 ;
     RECT  14.688 35.977 14.706 36.391 ;
     RECT  14.688 36.391 14.778 36.419 ;
     RECT  21.348 35.671 21.366 36.481 ;
     RECT  39.348 36.211 41.598 36.481 ;
     RECT  38.772 36.481 41.598 36.661 ;
     RECT  29.415 2.413 29.697 36.751 ;
     RECT  21.348 36.481 21.942 37.363 ;
     RECT  38.772 36.661 42.246 37.399 ;
     RECT  38.448 37.399 42.246 37.741 ;
     RECT  28.764 36.751 29.697 37.867 ;
     RECT  38.124 37.741 42.246 37.975 ;
     RECT  26.496 36.823 26.514 38.137 ;
     RECT  37.62 37.975 42.246 38.137 ;
     RECT  5.184 37.975 5.202 38.173 ;
     RECT  31.032 37.561 31.05 38.173 ;
     RECT  37.476 38.137 42.246 38.273 ;
     RECT  7.815 2.413 8.097 38.371 ;
     RECT  16.092 37.021 16.11 38.443 ;
     RECT  2.415 2.413 2.697 38.479 ;
     RECT  20.772 37.363 21.942 38.479 ;
     RECT  2.415 38.479 3.186 38.515 ;
     RECT  5.004 38.173 5.202 38.551 ;
     RECT  24.015 2.413 24.297 38.641 ;
     RECT  2.34 38.515 3.186 38.713 ;
     RECT  37.548 38.273 42.246 38.821 ;
     RECT  4.716 38.551 5.202 38.911 ;
     RECT  4.716 38.911 5.886 38.983 ;
     RECT  2.34 38.713 3.438 39.019 ;
     RECT  23.616 38.641 24.297 39.019 ;
     RECT  0.108 38.677 0.126 39.055 ;
     RECT  4.644 38.983 5.886 39.055 ;
     RECT  2.34 39.019 3.726 39.091 ;
     RECT  4.572 39.055 5.886 39.091 ;
     RECT  2.34 39.091 5.886 39.181 ;
     RECT  7.092 38.371 8.097 39.451 ;
     RECT  0.108 39.055 0.198 39.523 ;
     RECT  20.196 38.479 21.942 39.595 ;
     RECT  37.548 38.821 42.282 39.623 ;
     RECT  23.616 39.019 24.786 39.721 ;
     RECT  25.92 38.137 26.514 39.721 ;
     RECT  7.092 39.451 8.37 39.749 ;
     RECT  0.108 39.523 0.306 39.821 ;
     RECT  2.34 39.181 6.282 39.829 ;
     RECT  2.268 39.829 6.282 39.901 ;
     RECT  11.7 39.829 11.718 39.991 ;
     RECT  2.232 39.901 6.282 40.013 ;
     RECT  13.215 2.413 13.497 40.063 ;
     RECT  38.052 39.623 42.282 40.109 ;
     RECT  2.268 40.013 6.282 40.171 ;
     RECT  7.092 39.749 8.19 40.171 ;
     RECT  43.092 40.063 43.11 40.171 ;
     RECT  2.268 40.171 8.19 40.567 ;
     RECT  9.252 36.013 9.27 40.567 ;
     RECT  0.144 39.821 0.306 40.675 ;
     RECT  2.268 40.567 9.27 40.711 ;
     RECT  38.16 40.109 42.282 40.781 ;
     RECT  2.268 40.711 9.342 40.829 ;
     RECT  7.815 40.829 9.342 40.909 ;
     RECT  0.144 40.675 0.558 40.945 ;
     RECT  13.176 40.063 13.497 40.945 ;
     RECT  0.108 40.945 0.558 41.069 ;
     RECT  11.7 39.991 12.402 41.071 ;
     RECT  38.16 40.781 42.246 41.071 ;
     RECT  7.815 40.909 9.558 41.179 ;
     RECT  38.124 41.071 42.246 41.261 ;
     RECT  43.056 40.171 43.11 41.341 ;
     RECT  28.224 37.867 29.697 41.413 ;
     RECT  0.144 41.069 0.558 41.549 ;
     RECT  41.616 41.261 42.246 41.555 ;
     RECT  0.144 41.549 0.522 41.645 ;
     RECT  37.044 41.521 37.062 41.647 ;
     RECT  13.176 40.945 13.77 41.683 ;
     RECT  14.76 36.419 14.778 41.683 ;
     RECT  42.156 41.555 42.246 41.719 ;
     RECT  42.984 41.341 43.11 41.719 ;
     RECT  38.124 41.261 40.806 41.741 ;
     RECT  2.268 40.829 6.858 41.791 ;
     RECT  7.815 41.179 10.17 41.791 ;
     RECT  38.124 41.741 40.59 41.881 ;
     RECT  0.144 41.645 0.306 41.989 ;
     RECT  37.044 41.647 37.098 42.025 ;
     RECT  37.836 41.881 40.59 42.025 ;
     RECT  11.628 41.071 12.402 42.061 ;
     RECT  37.044 42.025 40.59 42.061 ;
     RECT  36.792 42.061 40.59 42.089 ;
     RECT  42.156 41.719 43.11 42.317 ;
     RECT  2.268 41.791 10.17 42.359 ;
     RECT  42.156 42.317 42.21 42.379 ;
     RECT  23.616 39.721 26.514 42.457 ;
     RECT  27.612 41.413 29.697 42.457 ;
     RECT  2.268 42.359 6.966 42.565 ;
     RECT  2.16 42.565 6.966 42.601 ;
     RECT  42.984 42.317 43.11 42.701 ;
     RECT  41.796 42.379 42.21 42.871 ;
     RECT  0.108 41.989 0.306 42.955 ;
     RECT  11.124 42.061 12.402 43.033 ;
     RECT  13.176 41.683 14.778 43.033 ;
     RECT  31.032 38.173 31.626 43.033 ;
     RECT  0.108 42.955 0.342 43.085 ;
     RECT  41.616 42.871 42.21 43.085 ;
     RECT  36.792 42.089 40.554 43.099 ;
     RECT  34.815 2.413 35.097 43.105 ;
     RECT  36.792 43.099 41.094 43.169 ;
     RECT  15.66 38.443 16.11 43.231 ;
     RECT  37.044 43.169 41.094 43.295 ;
     RECT  38.016 43.295 41.094 43.325 ;
     RECT  43.02 42.701 43.11 43.331 ;
     RECT  2.088 42.601 6.966 43.435 ;
     RECT  7.776 42.359 10.17 43.435 ;
     RECT  42.156 43.085 42.21 43.469 ;
     RECT  34.776 43.105 35.097 43.637 ;
     RECT  43.02 43.331 43.074 43.661 ;
     RECT  37.044 43.295 37.134 43.673 ;
     RECT  37.116 43.673 37.134 43.871 ;
     RECT  38.304 43.325 41.094 43.879 ;
     RECT  42.156 43.469 42.174 43.879 ;
     RECT  20.196 39.595 22.518 44.041 ;
     RECT  43.056 43.661 43.074 44.113 ;
     RECT  43.056 44.113 43.11 44.141 ;
     RECT  11.124 43.033 14.778 44.149 ;
     RECT  38.304 43.879 42.174 44.185 ;
     RECT  0.108 43.085 0.162 44.299 ;
     RECT  37.98 44.185 42.174 44.347 ;
     RECT  37.152 44.347 42.174 44.395 ;
     RECT  11.124 44.149 14.85 44.455 ;
     RECT  0.108 44.299 0.342 44.491 ;
     RECT  34.815 43.637 35.097 44.491 ;
     RECT  37.152 44.395 42.21 44.761 ;
     RECT  36.54 44.761 42.21 44.909 ;
     RECT  36.54 44.909 42.174 44.951 ;
     RECT  34.776 44.491 35.097 44.959 ;
     RECT  2.088 43.435 10.17 44.971 ;
     RECT  36.54 44.951 41.274 44.987 ;
     RECT  43.092 44.141 43.11 45.067 ;
     RECT  11.088 44.455 14.85 45.121 ;
     RECT  0.108 44.491 0.558 45.197 ;
     RECT  42.912 45.067 43.11 45.197 ;
     RECT  33.084 45.193 33.102 45.229 ;
     RECT  42.156 44.951 42.174 45.293 ;
     RECT  33.084 45.229 33.174 45.301 ;
     RECT  33.084 45.301 33.246 45.455 ;
     RECT  1.728 44.971 10.17 45.499 ;
     RECT  10.908 45.121 14.85 45.499 ;
     RECT  1.728 45.499 14.85 45.599 ;
     RECT  43.056 45.197 43.11 45.689 ;
     RECT  18.615 2.413 18.897 45.697 ;
     RECT  35.928 45.463 35.946 45.697 ;
     RECT  34.452 44.959 35.097 45.805 ;
     RECT  35.856 45.697 35.946 45.805 ;
     RECT  1.728 45.599 10.17 45.833 ;
     RECT  34.452 45.805 35.946 45.841 ;
     RECT  36.684 44.987 41.274 45.841 ;
     RECT  33.084 45.455 33.21 45.931 ;
     RECT  34.452 45.841 41.274 45.959 ;
     RECT  0.144 45.197 0.558 46.003 ;
     RECT  36.684 45.959 41.274 46.067 ;
     RECT  10.908 45.599 14.85 46.103 ;
     RECT  43.02 45.979 43.038 46.157 ;
     RECT  36.9 46.067 41.274 46.201 ;
     RECT  42.156 46.027 42.174 46.201 ;
     RECT  0.108 46.003 0.558 46.253 ;
     RECT  32.796 45.931 33.21 46.381 ;
     RECT  34.452 45.959 35.802 46.381 ;
     RECT  30.456 43.033 31.626 46.543 ;
     RECT  32.796 46.381 35.802 46.543 ;
     RECT  0.108 46.253 0.162 46.637 ;
     RECT  36.9 46.201 42.174 46.733 ;
     RECT  36.9 46.733 40.914 46.805 ;
     RECT  41.76 46.733 42.174 46.877 ;
     RECT  30.456 46.543 35.802 46.921 ;
     RECT  36.9 46.805 40.626 46.921 ;
     RECT  17.964 45.697 18.897 47.011 ;
     RECT  19.764 44.041 22.518 47.011 ;
     RECT  10.98 46.103 14.85 47.119 ;
     RECT  17.964 47.011 18.99 47.155 ;
     RECT  19.764 47.011 22.662 47.155 ;
     RECT  17.964 47.155 22.662 47.309 ;
     RECT  2.052 45.833 10.17 47.501 ;
     RECT  0.108 46.637 0.126 47.597 ;
     RECT  15.66 43.231 16.83 47.623 ;
     RECT  17.964 47.309 18.897 47.623 ;
     RECT  43.092 47.563 43.11 47.623 ;
     RECT  41.832 46.877 42.174 47.659 ;
     RECT  2.088 47.501 10.17 47.731 ;
     RECT  10.908 47.119 14.85 47.731 ;
     RECT  30.456 46.921 40.626 47.731 ;
     RECT  41.58 47.659 42.174 47.789 ;
     RECT  30.456 47.731 40.698 47.821 ;
     RECT  30.456 47.821 40.734 48.199 ;
     RECT  0.468 47.623 0.558 48.331 ;
     RECT  30.456 48.199 41.058 48.365 ;
     RECT  19.764 47.309 22.59 48.433 ;
     RECT  0.324 48.331 0.558 48.461 ;
     RECT  0.468 48.461 0.558 48.653 ;
     RECT  30.456 48.365 40.734 48.695 ;
     RECT  42.12 47.789 42.174 48.775 ;
     RECT  2.088 47.731 14.85 48.839 ;
     RECT  0.54 48.653 0.558 49.037 ;
     RECT  42.084 48.775 42.174 49.045 ;
     RECT  43.056 47.623 43.11 49.109 ;
     RECT  41.616 49.045 42.174 49.585 ;
     RECT  30.456 48.695 40.698 49.739 ;
     RECT  41.616 49.585 42.21 49.783 ;
     RECT  41.58 49.783 42.21 49.805 ;
     RECT  43.056 49.109 43.074 49.867 ;
     RECT  43.056 49.867 43.11 50.009 ;
     RECT  0.108 49.477 0.126 50.125 ;
     RECT  11.124 48.839 14.85 50.251 ;
     RECT  15.66 47.623 18.897 50.251 ;
     RECT  19.656 48.433 22.59 50.323 ;
     RECT  23.616 42.457 29.697 50.323 ;
     RECT  30.456 49.739 40.626 50.701 ;
     RECT  0.108 50.125 0.198 50.731 ;
     RECT  30.456 50.701 40.806 50.861 ;
     RECT  43.056 50.009 43.074 50.891 ;
     RECT  41.58 49.805 42.174 51.019 ;
     RECT  41.544 51.019 42.174 51.169 ;
     RECT  0.108 50.731 0.45 51.197 ;
     RECT  2.088 48.839 10.242 51.205 ;
     RECT  11.124 50.251 18.897 51.205 ;
     RECT  0.108 51.197 0.306 51.233 ;
     RECT  0.108 51.233 0.162 51.245 ;
     RECT  43.02 51.643 43.038 51.673 ;
     RECT  0.144 51.245 0.162 51.677 ;
     RECT  43.02 51.673 43.11 51.725 ;
     RECT  30.456 50.861 40.77 51.781 ;
     RECT  41.544 51.169 42.21 51.781 ;
     RECT  2.088 51.205 18.897 51.883 ;
     RECT  2.052 51.883 18.897 51.935 ;
     RECT  30.456 51.781 42.21 52.007 ;
     RECT  30.456 52.007 42.174 52.109 ;
     RECT  30.456 52.109 42.138 52.277 ;
     RECT  41.796 52.277 42.138 52.301 ;
     RECT  43.02 51.725 43.038 52.459 ;
     RECT  42.912 52.459 43.038 52.589 ;
     RECT  42.048 52.301 42.138 52.781 ;
     RECT  42.084 52.781 42.138 52.817 ;
     RECT  2.088 51.935 18.897 52.825 ;
     RECT  42.12 52.817 42.138 52.861 ;
     RECT  42.12 52.861 42.21 52.877 ;
     RECT  2.052 52.825 18.897 52.973 ;
     RECT  0.54 52.861 0.558 52.987 ;
     RECT  43.02 52.589 43.038 53.261 ;
     RECT  30.456 52.277 40.914 53.323 ;
     RECT  30.456 53.323 41.022 53.549 ;
     RECT  0.108 52.987 0.558 53.645 ;
     RECT  0.18 53.645 0.558 54.445 ;
     RECT  30.456 53.549 40.914 54.715 ;
     RECT  43.092 54.571 43.11 54.751 ;
     RECT  43.056 54.751 43.11 54.797 ;
     RECT  30.456 54.715 41.022 54.841 ;
     RECT  19.656 50.323 29.697 54.913 ;
     RECT  30.456 54.841 41.058 54.913 ;
     RECT  19.656 54.913 41.058 54.955 ;
     RECT  42.156 52.877 42.21 54.955 ;
     RECT  0.108 54.445 0.558 55.184 ;
     RECT  19.656 54.955 42.21 55.277 ;
     RECT  0.216 55.184 0.558 55.373 ;
     RECT  43.092 54.797 43.11 55.373 ;
     RECT  0.252 55.373 0.558 55.469 ;
     RECT  41.58 55.277 42.21 55.915 ;
     RECT  43.02 55.867 43.038 55.915 ;
     RECT  19.656 55.277 40.842 56.029 ;
     RECT  41.58 55.915 43.038 56.029 ;
     RECT  19.656 56.029 43.038 56.045 ;
     RECT  2.088 52.973 18.897 56.107 ;
     RECT  19.656 56.045 42.21 56.129 ;
     RECT  0.252 55.469 0.27 56.155 ;
     RECT  0.144 56.155 0.27 56.203 ;
     RECT  0.144 56.203 0.342 56.333 ;
     RECT  2.052 56.107 18.897 56.363 ;
     RECT  43.092 56.587 43.11 56.827 ;
     RECT  41.58 56.129 42.21 56.939 ;
     RECT  43.02 56.827 43.11 57.029 ;
     RECT  0.144 56.333 0.198 57.145 ;
     RECT  42.084 56.939 42.21 57.209 ;
     RECT  19.656 56.129 40.806 57.271 ;
     RECT  43.02 57.029 43.038 57.341 ;
     RECT  42.084 57.209 42.174 57.479 ;
     RECT  0.144 57.145 0.558 57.485 ;
     RECT  42.156 57.479 42.174 57.569 ;
     RECT  19.656 57.271 40.842 57.721 ;
     RECT  0.18 57.485 0.558 57.773 ;
     RECT  19.656 57.721 40.914 58.109 ;
     RECT  43.092 58.117 43.11 58.349 ;
     RECT  41.616 58.261 41.634 58.507 ;
     RECT  41.616 58.507 42.174 58.637 ;
     RECT  19.656 58.109 40.878 59.063 ;
     RECT  42.156 58.637 42.174 59.305 ;
     RECT  0.504 57.773 0.558 59.371 ;
     RECT  42.156 59.305 42.21 59.371 ;
     RECT  0.324 59.371 0.558 59.467 ;
     RECT  0.144 59.467 0.558 59.693 ;
     RECT  30.456 59.063 40.878 59.773 ;
     RECT  41.616 59.371 42.21 59.773 ;
     RECT  43.092 59.467 43.11 59.909 ;
     RECT  2.088 56.363 18.897 59.947 ;
     RECT  0.144 59.693 0.162 60.317 ;
     RECT  30.456 59.773 42.21 60.349 ;
     RECT  30.456 60.349 42.282 60.653 ;
     RECT  19.656 59.063 29.697 60.817 ;
     RECT  30.456 60.653 42.174 60.817 ;
     RECT  43.056 60.043 43.074 60.889 ;
     RECT  2.052 59.947 18.897 60.941 ;
     RECT  43.056 60.889 43.11 61.051 ;
     RECT  0.324 61.291 0.342 61.421 ;
     RECT  42.984 61.051 43.11 61.517 ;
     RECT  19.656 60.817 42.174 61.661 ;
     RECT  42.912 61.867 42.93 61.997 ;
     RECT  2.088 60.941 18.897 62.059 ;
     RECT  2.052 62.059 18.897 62.195 ;
     RECT  30.456 61.661 42.174 62.347 ;
     RECT  30.456 62.347 42.282 62.537 ;
     RECT  41.652 62.537 42.282 62.861 ;
     RECT  2.088 62.195 18.897 63.121 ;
     RECT  0.54 62.005 0.558 63.247 ;
     RECT  0.108 63.247 0.558 63.307 ;
     RECT  43.092 63.019 43.11 63.347 ;
     RECT  0.108 63.307 0.666 63.437 ;
     RECT  41.652 62.861 42.174 63.778 ;
     RECT  2.052 63.121 18.897 63.815 ;
     RECT  30.456 62.537 40.878 63.883 ;
     RECT  41.652 63.778 42.21 63.883 ;
     RECT  0.108 63.437 0.126 64.109 ;
     RECT  30.456 63.883 42.21 64.499 ;
     RECT  0.144 64.267 0.342 64.741 ;
     RECT  43.056 64.741 43.074 64.747 ;
     RECT  2.088 63.815 18.897 64.843 ;
     RECT  30.456 64.499 40.734 64.859 ;
     RECT  43.056 64.747 43.11 64.877 ;
     RECT  2.052 64.843 18.897 64.939 ;
     RECT  43.092 64.877 43.11 65.003 ;
     RECT  41.58 64.499 42.21 65.129 ;
     RECT  0.144 64.741 0.558 65.165 ;
     RECT  41.616 65.129 42.21 65.201 ;
     RECT  41.616 65.201 42.174 65.357 ;
     RECT  41.976 65.357 42.174 65.453 ;
     RECT  0.144 65.165 0.162 65.501 ;
     RECT  30.456 64.859 40.698 65.669 ;
     RECT  1.728 64.939 18.897 65.995 ;
     RECT  43.02 65.899 43.038 66.187 ;
     RECT  0.108 66.091 0.126 66.221 ;
     RECT  42.912 66.187 43.038 66.317 ;
     RECT  41.976 65.453 42.138 66.379 ;
     RECT  30.456 65.669 40.662 66.451 ;
     RECT  43.02 66.317 43.038 66.461 ;
     RECT  41.976 66.379 42.246 66.623 ;
     RECT  41.976 66.623 42.174 66.667 ;
     RECT  30.456 66.451 40.698 66.757 ;
     RECT  30.456 66.757 40.734 67.019 ;
     RECT  0.324 66.955 0.342 67.051 ;
     RECT  41.58 66.667 42.174 67.051 ;
     RECT  41.544 67.051 42.174 67.127 ;
     RECT  0.216 67.051 0.342 67.339 ;
     RECT  0.108 67.339 0.342 67.433 ;
     RECT  0.18 67.433 0.342 67.469 ;
     RECT  0.18 67.469 0.198 67.613 ;
     RECT  41.58 67.127 42.174 67.631 ;
     RECT  41.616 67.631 42.174 67.661 ;
     RECT  41.796 67.661 42.174 67.675 ;
     RECT  43.092 66.955 43.11 67.757 ;
     RECT  30.456 67.019 40.626 67.801 ;
     RECT  41.796 67.675 42.21 67.853 ;
     RECT  1.404 65.995 18.897 67.937 ;
     RECT  2.052 67.937 18.897 68.405 ;
     RECT  41.796 67.853 42.174 68.429 ;
     RECT  42.12 68.429 42.174 68.587 ;
     RECT  30.456 67.801 40.77 68.639 ;
     RECT  0.54 68.791 0.558 68.917 ;
     RECT  42.12 68.587 42.21 68.981 ;
     RECT  2.088 68.405 18.897 69.163 ;
     RECT  2.052 69.163 18.897 69.215 ;
     RECT  42.12 68.981 42.174 69.223 ;
     RECT  0.108 68.917 0.558 69.389 ;
     RECT  30.456 68.639 40.698 69.451 ;
     RECT  30.456 69.451 40.77 69.499 ;
     RECT  43.02 69.451 43.038 69.521 ;
     RECT  0.108 69.389 0.342 69.581 ;
     RECT  30.456 69.499 41.058 69.961 ;
     RECT  41.832 69.223 42.174 69.961 ;
     RECT  30.456 69.961 42.174 70.141 ;
     RECT  30.456 70.141 42.21 70.253 ;
     RECT  2.088 69.215 18.897 70.267 ;
     RECT  2.088 70.267 18.918 70.397 ;
     RECT  42.12 70.253 42.21 70.411 ;
     RECT  42.12 70.411 42.246 70.541 ;
     RECT  0.216 69.581 0.342 70.829 ;
     RECT  0.216 70.829 0.234 70.973 ;
     RECT  43.092 70.6 43.11 71.113 ;
     RECT  43.02 71.113 43.11 71.141 ;
     RECT  43.02 71.141 43.038 71.165 ;
     RECT  30.456 70.253 41.058 71.179 ;
     RECT  42.12 70.541 42.174 71.179 ;
     RECT  30.456 71.179 42.174 71.309 ;
     RECT  30.456 71.309 40.842 71.405 ;
     RECT  41.58 71.309 42.174 71.411 ;
     RECT  30.456 71.405 40.698 71.609 ;
     RECT  41.76 71.411 42.174 71.851 ;
     RECT  41.76 71.851 42.894 71.947 ;
     RECT  41.76 71.947 43.002 71.981 ;
     RECT  0.108 71.455 0.126 71.995 ;
     RECT  0.108 71.995 0.162 72.077 ;
     RECT  42.984 71.981 43.002 72.221 ;
     RECT  41.76 71.981 42.174 72.427 ;
     RECT  30.456 71.609 40.662 72.499 ;
     RECT  43.02 72.229 43.11 72.527 ;
     RECT  30.456 72.499 40.698 72.535 ;
     RECT  41.616 72.427 42.174 72.653 ;
     RECT  0.144 72.077 0.162 72.805 ;
     RECT  41.616 72.653 41.958 72.907 ;
     RECT  30.456 72.535 40.734 73.003 ;
     RECT  41.58 72.907 41.958 73.003 ;
     RECT  0.108 72.805 0.162 73.075 ;
     RECT  2.088 70.397 18.897 73.381 ;
     RECT  30.456 73.003 41.958 73.483 ;
     RECT  30.456 73.483 42.246 73.805 ;
     RECT  43.092 72.527 43.11 73.819 ;
     RECT  43.02 73.819 43.11 73.997 ;
     RECT  0.108 73.075 0.558 74.189 ;
     RECT  42.12 73.805 42.246 74.381 ;
     RECT  2.052 73.381 18.897 74.573 ;
     RECT  30.456 73.805 40.914 74.861 ;
     RECT  0.216 74.189 0.558 75.019 ;
     RECT  42.12 74.381 42.174 75.115 ;
     RECT  0.144 75.019 0.558 75.197 ;
     RECT  42.12 75.115 42.21 75.199 ;
     RECT  0.324 75.197 0.558 75.245 ;
     RECT  43.092 73.997 43.11 75.355 ;
     RECT  43.02 75.355 43.11 75.389 ;
     RECT  19.656 61.661 29.697 75.397 ;
     RECT  30.456 74.861 40.734 75.397 ;
     RECT  42.084 75.199 42.21 75.403 ;
     RECT  43.02 75.389 43.074 75.403 ;
     RECT  42.084 75.403 43.074 75.461 ;
     RECT  42.912 75.461 43.074 75.533 ;
     RECT  42.084 75.461 42.174 75.569 ;
     RECT  42.084 75.569 42.138 75.595 ;
     RECT  19.656 75.397 40.734 75.811 ;
     RECT  43.056 75.533 43.074 75.821 ;
     RECT  0.324 75.245 0.522 75.937 ;
     RECT  19.656 75.811 41.058 75.979 ;
     RECT  42.048 75.595 42.138 75.979 ;
     RECT  2.088 74.573 18.897 76.045 ;
     RECT  19.656 75.979 42.138 76.109 ;
     RECT  2.052 76.045 18.897 76.205 ;
     RECT  0.144 75.937 0.522 76.207 ;
     RECT  0.108 76.207 0.522 76.351 ;
     RECT  0.108 76.351 0.558 76.397 ;
     RECT  0.108 76.397 0.198 76.493 ;
     RECT  32.76 76.109 41.274 76.505 ;
     RECT  19.656 76.109 31.626 76.541 ;
     RECT  34.776 76.505 41.274 76.577 ;
     RECT  32.76 76.505 33.894 76.649 ;
     RECT  0.144 76.493 0.198 76.973 ;
     RECT  43.092 76.651 43.11 77.009 ;
     RECT  33.876 76.649 33.894 77.081 ;
     RECT  0.18 76.973 0.198 77.227 ;
     RECT  32.76 76.649 32.778 77.315 ;
     RECT  34.776 76.577 41.022 77.387 ;
     RECT  36 77.387 41.022 77.549 ;
     RECT  34.776 77.387 35.097 77.593 ;
     RECT  2.088 76.205 18.897 77.707 ;
     RECT  42.048 76.109 42.138 77.803 ;
     RECT  34.704 77.593 35.097 77.837 ;
     RECT  41.58 77.803 42.138 77.899 ;
     RECT  41.58 77.899 42.174 77.971 ;
     RECT  36 77.549 40.734 78.125 ;
     RECT  41.58 77.971 42.21 78.241 ;
     RECT  2.052 77.707 18.897 78.317 ;
     RECT  33.624 77.557 33.642 78.359 ;
     RECT  41.58 78.241 42.246 78.439 ;
     RECT  0.18 77.227 0.342 78.475 ;
     RECT  0.108 78.475 0.342 78.511 ;
     RECT  41.544 78.439 42.246 78.605 ;
     RECT  43.056 78.367 43.074 78.637 ;
     RECT  43.056 78.637 43.11 78.797 ;
     RECT  36 78.125 40.626 78.871 ;
     RECT  35.964 78.871 40.626 79.015 ;
     RECT  41.544 78.605 42.174 79.015 ;
     RECT  2.088 78.317 18.897 79.085 ;
     RECT  35.964 79.015 42.174 79.085 ;
     RECT  34.776 77.837 35.097 79.141 ;
     RECT  34.776 79.141 35.154 79.181 ;
     RECT  0.108 78.511 0.558 79.277 ;
     RECT  32.508 79.177 32.526 79.313 ;
     RECT  34.815 79.181 35.154 79.511 ;
     RECT  2.124 79.085 18.897 79.889 ;
     RECT  0.324 79.277 0.558 80.011 ;
     RECT  41.58 79.085 42.174 80.011 ;
     RECT  35.964 79.085 40.698 80.159 ;
     RECT  41.58 80.011 42.246 80.357 ;
     RECT  34.815 79.511 35.097 80.563 ;
     RECT  2.16 79.889 18.897 80.627 ;
     RECT  34.812 80.563 35.097 80.635 ;
     RECT  36 80.159 40.698 80.671 ;
     RECT  41.58 80.357 42.21 80.671 ;
     RECT  36 80.671 42.21 80.717 ;
     RECT  34.776 80.635 35.097 80.897 ;
     RECT  0.216 80.011 0.558 80.905 ;
     RECT  34.812 80.897 35.097 80.933 ;
     RECT  36 80.717 40.734 81.059 ;
     RECT  43.092 78.797 43.11 81.059 ;
     RECT  36.612 81.059 40.734 81.131 ;
     RECT  19.656 76.541 29.697 81.239 ;
     RECT  41.616 80.717 42.21 81.355 ;
     RECT  23.616 81.239 29.697 81.401 ;
     RECT  0.108 80.905 0.558 81.485 ;
     RECT  36.72 81.131 40.734 81.715 ;
     RECT  41.616 81.355 42.246 81.779 ;
     RECT  34.815 80.933 35.097 81.877 ;
     RECT  2.196 80.627 18.897 82.027 ;
     RECT  34.776 81.877 35.097 82.111 ;
     RECT  41.616 81.779 42.21 82.123 ;
     RECT  34.704 82.111 35.097 82.157 ;
     RECT  2.16 82.027 18.897 82.175 ;
     RECT  36.72 81.715 40.842 82.417 ;
     RECT  41.58 82.123 42.21 82.417 ;
     RECT  0.504 81.485 0.558 82.507 ;
     RECT  36.72 82.417 42.21 82.517 ;
     RECT  36.72 82.517 40.914 82.553 ;
     RECT  0.504 82.507 0.63 82.561 ;
     RECT  0.108 82.561 0.63 82.637 ;
     RECT  41.652 82.517 42.21 82.699 ;
     RECT  36.72 82.553 40.842 82.751 ;
     RECT  36.72 82.751 40.698 82.949 ;
     RECT  41.652 82.699 42.894 82.984 ;
     RECT  34.815 82.157 35.097 82.993 ;
     RECT  0.108 82.637 0.162 83.021 ;
     RECT  2.196 82.175 18.897 83.035 ;
     RECT  41.652 82.984 43.074 83.179 ;
     RECT  2.16 83.035 18.897 83.213 ;
     RECT  41.652 83.179 43.11 83.371 ;
     RECT  0.144 83.021 0.162 83.501 ;
     RECT  41.58 83.371 43.11 83.597 ;
     RECT  34.776 82.993 35.097 83.759 ;
     RECT  35.928 83.731 35.946 83.911 ;
     RECT  36.9 82.949 40.698 83.911 ;
     RECT  41.58 83.597 42.174 83.911 ;
     RECT  42.984 83.597 43.11 83.981 ;
     RECT  35.928 83.911 42.174 84.029 ;
     RECT  0.108 83.767 0.126 84.077 ;
     RECT  36.324 84.029 42.174 84.173 ;
     RECT  23.616 81.401 28.278 84.209 ;
     RECT  2.196 83.213 18.897 84.335 ;
     RECT  43.092 83.981 43.11 84.407 ;
     RECT  36.324 84.173 40.77 84.569 ;
     RECT  34.815 83.759 35.097 84.847 ;
     RECT  1.296 84.715 1.314 84.907 ;
     RECT  2.304 84.335 18.897 84.947 ;
     RECT  36.9 84.569 40.77 84.955 ;
     RECT  41.58 84.173 42.174 84.955 ;
     RECT  30.456 76.541 31.626 85.019 ;
     RECT  34.815 84.847 35.37 85.189 ;
     RECT  2.304 84.947 14.238 85.243 ;
     RECT  34.776 85.189 35.37 85.289 ;
     RECT  0.144 85.243 0.162 85.291 ;
     RECT  34.815 85.289 35.37 85.379 ;
     RECT  0.144 85.291 0.342 85.421 ;
     RECT  36.9 84.955 42.174 85.421 ;
     RECT  36.9 85.421 40.698 85.495 ;
     RECT  43.02 85.291 43.038 85.579 ;
     RECT  23.616 84.209 28.206 85.793 ;
     RECT  41.616 85.421 42.174 85.867 ;
     RECT  36.54 85.495 40.698 85.919 ;
     RECT  41.616 85.867 42.21 85.997 ;
     RECT  2.232 85.243 14.238 86.027 ;
     RECT  0.108 85.963 0.126 86.093 ;
     RECT  37.044 85.919 40.698 86.233 ;
     RECT  42.012 85.997 42.21 86.251 ;
     RECT  43.02 85.579 43.11 86.261 ;
     RECT  2.268 86.027 14.238 86.297 ;
     RECT  30.456 85.019 30.474 86.333 ;
     RECT  37.044 86.233 40.77 86.341 ;
     RECT  2.268 86.297 12.042 86.381 ;
     RECT  2.304 86.381 12.042 86.459 ;
     RECT  12.78 86.297 14.238 86.459 ;
     RECT  42.012 86.251 42.246 86.567 ;
     RECT  10.152 86.459 12.042 86.729 ;
     RECT  37.044 86.341 40.842 86.779 ;
     RECT  37.044 86.779 40.95 86.827 ;
     RECT  42.012 86.567 42.21 86.827 ;
     RECT  1.296 84.907 1.458 86.837 ;
     RECT  31.608 85.019 31.626 86.837 ;
     RECT  1.44 86.837 1.458 86.873 ;
     RECT  13.215 86.459 14.238 86.999 ;
     RECT  19.656 81.239 22.59 86.999 ;
     RECT  0.324 86.443 0.342 87.053 ;
     RECT  43.02 86.261 43.038 87.211 ;
     RECT  2.304 86.459 9.378 87.385 ;
     RECT  23.652 85.793 28.206 87.413 ;
     RECT  10.728 86.729 12.042 87.449 ;
     RECT  37.044 86.827 42.21 87.539 ;
     RECT  37.62 87.539 42.21 87.611 ;
     RECT  15.084 84.947 18.897 87.809 ;
     RECT  27.648 87.413 28.206 87.953 ;
     RECT  2.268 87.385 9.378 88.115 ;
     RECT  2.268 88.115 8.514 88.171 ;
     RECT  13.215 86.999 14.13 88.259 ;
     RECT  37.62 87.611 42.174 88.349 ;
     RECT  13.215 88.259 13.914 88.529 ;
     RECT  1.728 88.171 8.514 88.555 ;
     RECT  43.02 87.211 43.11 88.555 ;
     RECT  10.728 87.449 11.754 88.619 ;
     RECT  42.912 88.555 43.11 88.685 ;
     RECT  11.268 88.619 11.754 89.069 ;
     RECT  23.652 87.413 26.55 89.069 ;
     RECT  37.656 88.349 42.174 89.159 ;
     RECT  23.652 89.069 25.398 89.573 ;
     RECT  38.016 89.159 42.174 89.609 ;
     RECT  0.108 88.897 0.126 89.611 ;
     RECT  43.02 88.685 43.11 89.611 ;
     RECT  11.448 89.069 11.754 89.699 ;
     RECT  42.984 89.611 43.11 89.803 ;
     RECT  0.108 89.611 0.342 89.815 ;
     RECT  19.656 86.999 22.554 89.969 ;
     RECT  1.296 88.555 8.514 90.029 ;
     RECT  42.984 89.803 43.182 90.077 ;
     RECT  1.296 90.029 7.038 90.091 ;
     RECT  23.652 89.573 24.297 90.113 ;
     RECT  0.072 89.815 0.342 90.317 ;
     RECT  11.736 89.699 11.754 90.383 ;
     RECT  34.815 85.379 35.097 90.391 ;
     RECT  20.808 89.969 22.554 90.419 ;
     RECT  1.152 90.091 7.038 90.509 ;
     RECT  20.808 90.419 21.978 90.509 ;
     RECT  0.072 90.317 0.198 90.557 ;
     RECT  7.815 90.029 8.514 90.617 ;
     RECT  34.776 90.391 35.097 90.617 ;
     RECT  38.016 89.609 42.138 90.689 ;
     RECT  9.36 88.115 9.378 90.779 ;
     RECT  38.016 90.689 42.102 90.779 ;
     RECT  7.815 90.617 8.298 90.815 ;
     RECT  1.152 90.509 6.894 90.923 ;
     RECT  19.656 89.969 19.674 90.923 ;
     RECT  38.196 90.779 41.598 91.121 ;
     RECT  16.236 87.809 18.897 91.229 ;
     RECT  2.34 90.923 6.894 91.319 ;
     RECT  2.34 91.319 6.318 91.355 ;
     RECT  34.815 90.617 35.097 91.363 ;
     RECT  16.776 91.229 18.897 91.463 ;
     RECT  34.776 91.363 35.097 91.463 ;
     RECT  21.384 90.509 21.978 91.499 ;
     RECT  2.415 91.355 6.318 91.589 ;
     RECT  43.056 90.077 43.182 91.589 ;
     RECT  25.38 89.573 25.398 91.661 ;
     RECT  5.472 91.589 6.318 91.769 ;
     RECT  2.415 91.589 4.734 91.859 ;
     RECT  0.072 90.557 0.126 91.895 ;
     RECT  28.188 87.953 28.206 91.895 ;
     RECT  5.472 91.769 5.706 91.931 ;
     RECT  17.928 91.463 18.897 91.931 ;
     RECT  3.996 91.859 4.734 92.039 ;
     RECT  3.996 92.039 4.518 92.129 ;
     RECT  5.472 91.931 5.49 92.129 ;
     RECT  4.068 92.129 4.518 92.165 ;
     RECT  2.415 91.859 3.258 92.399 ;
     RECT  38.196 91.121 41.382 92.399 ;
     RECT  34.815 91.463 35.097 92.407 ;
     RECT  0.072 91.895 0.09 92.435 ;
     RECT  16.776 91.463 16.794 92.435 ;
     RECT  34.776 92.407 35.097 92.507 ;
     RECT  26.532 89.069 26.55 92.579 ;
     RECT  2.415 92.399 3.114 92.669 ;
     RECT  4.068 92.165 4.086 92.669 ;
     RECT  43.164 91.589 43.182 92.669 ;
     RECT  1.152 90.923 1.17 92.705 ;
     RECT  38.844 92.399 41.382 92.849 ;
     RECT  38.88 92.849 41.382 92.939 ;
     RECT  15.084 87.809 15.102 92.975 ;
     RECT  38.88 92.939 41.31 93.209 ;
     RECT  39.096 93.209 40.95 93.389 ;
     RECT  39.096 93.389 40.497 93.479 ;
     RECT  21.96 91.499 21.978 93.659 ;
     RECT  39.456 93.479 40.497 93.749 ;
     RECT  2.415 92.669 2.697 127.187 ;
     RECT  7.815 90.815 8.097 127.187 ;
     RECT  13.215 88.529 13.497 127.187 ;
     RECT  18.615 91.931 18.897 127.187 ;
     RECT  24.015 90.113 24.297 127.187 ;
     RECT  29.415 81.401 29.697 127.187 ;
     RECT  34.815 92.507 35.097 127.187 ;
     RECT  40.215 93.749 40.497 127.187 ;
     RECT  2.415 127.187 2.505 127.457 ;
     RECT  7.815 127.187 7.905 127.457 ;
     RECT  13.215 127.187 13.305 127.457 ;
     RECT  18.615 127.187 18.705 127.457 ;
     RECT  24.015 127.187 24.105 127.457 ;
     RECT  29.415 127.187 29.505 127.457 ;
     RECT  34.815 127.187 34.905 127.457 ;
     RECT  40.215 127.187 40.305 127.457 ;
    LAYER M4 ;
     RECT  0.06 39.792 0.133 90.408 ;
     RECT  0.133 39.792 0.137 90.456 ;
     RECT  0.137 39.888 0.169 90.456 ;
     RECT  0.169 39.888 0.173 90.552 ;
     RECT  0.173 39.984 2.408 90.552 ;
     RECT  2.408 2.148 2.512 127.452 ;
     RECT  2.512 2.418 2.704 127.182 ;
     RECT  2.704 60.288 2.729 65.784 ;
     RECT  2.729 60.288 2.765 65.064 ;
     RECT  2.704 40.08 2.801 54.696 ;
     RECT  2.704 85.392 2.819 91.8 ;
     RECT  2.819 85.392 2.837 88.776 ;
     RECT  2.801 45.36 2.873 54.696 ;
     RECT  2.704 67.344 2.873 84.36 ;
     RECT  2.837 86.544 2.873 88.776 ;
     RECT  2.765 60.288 3.017 63.336 ;
     RECT  2.873 87.024 3.017 88.776 ;
     RECT  3.017 60.288 3.125 60.984 ;
     RECT  3.017 61.968 3.125 63.336 ;
     RECT  3.017 87.888 3.125 88.776 ;
     RECT  2.801 40.08 3.161 43.944 ;
     RECT  3.161 40.08 3.449 40.104 ;
     RECT  2.819 89.856 3.485 91.8 ;
     RECT  3.125 88.224 3.557 88.776 ;
     RECT  2.873 75.84 3.685 84.36 ;
     RECT  2.837 85.392 3.685 85.416 ;
     RECT  2.704 55.68 3.697 58.296 ;
     RECT  3.125 62.16 3.733 63.336 ;
     RECT  2.765 64.368 3.733 65.064 ;
     RECT  2.873 67.344 3.769 74.712 ;
     RECT  2.873 45.36 3.817 52.344 ;
     RECT  3.817 46.608 3.841 52.344 ;
     RECT  2.873 53.328 3.841 54.648 ;
     RECT  3.697 55.68 3.841 59.208 ;
     RECT  3.769 67.2 3.841 74.712 ;
     RECT  3.733 62.16 3.913 65.064 ;
     RECT  3.841 66.24 3.913 74.712 ;
     RECT  3.913 62.16 3.925 74.712 ;
     RECT  3.685 75.84 3.925 85.416 ;
     RECT  3.817 45.36 3.971 45.576 ;
     RECT  3.925 62.16 3.985 85.416 ;
     RECT  3.125 60.96 4.165 60.984 ;
     RECT  3.161 41.136 4.345 43.944 ;
     RECT  4.117 87.12 4.345 87.144 ;
     RECT  3.557 88.224 4.345 88.44 ;
     RECT  4.345 41.136 4.373 45.336 ;
     RECT  3.841 46.608 4.381 59.208 ;
     RECT  4.165 60.24 4.381 60.984 ;
     RECT  4.373 40.416 4.457 45.336 ;
     RECT  4.381 46.608 4.489 60.984 ;
     RECT  3.985 62.16 4.489 85.512 ;
     RECT  3.485 90.48 4.705 91.8 ;
     RECT  4.489 46.608 4.717 85.512 ;
     RECT  4.345 87.12 4.813 88.44 ;
     RECT  4.705 90.24 4.885 91.8 ;
     RECT  4.813 87.12 4.897 88.968 ;
     RECT  4.897 87.12 4.993 88.44 ;
     RECT  4.457 41.376 5.077 45.336 ;
     RECT  4.717 46.608 5.077 59.736 ;
     RECT  4.993 86.688 5.123 88.44 ;
     RECT  5.123 87.792 5.213 88.44 ;
     RECT  4.885 90.048 5.221 91.8 ;
     RECT  4.717 60.816 5.317 85.512 ;
     RECT  5.123 86.688 5.317 86.76 ;
     RECT  5.221 89.52 5.357 91.8 ;
     RECT  5.317 60.816 5.465 86.76 ;
     RECT  5.029 40.176 5.497 40.2 ;
     RECT  5.357 89.52 5.501 89.976 ;
     RECT  5.357 91.2 5.501 91.8 ;
     RECT  5.213 87.792 5.537 88.392 ;
     RECT  5.497 39.312 5.581 40.2 ;
     RECT  5.581 40.176 5.677 40.2 ;
     RECT  5.501 91.2 5.699 91.224 ;
     RECT  5.077 41.376 5.713 59.736 ;
     RECT  5.465 60.816 5.713 85.224 ;
     RECT  5.677 40.176 5.749 40.392 ;
     RECT  5.713 41.376 5.749 85.224 ;
     RECT  5.749 40.176 6.041 85.224 ;
     RECT  5.537 87.792 6.541 88.344 ;
     RECT  5.465 86.352 6.577 86.76 ;
     RECT  6.541 87.792 6.577 88.968 ;
     RECT  6.041 47.04 6.613 85.224 ;
     RECT  6.577 86.352 6.613 88.968 ;
     RECT  6.041 40.176 7.196 46.008 ;
     RECT  6.613 47.04 7.196 88.968 ;
     RECT  5.501 89.952 7.436 89.976 ;
     RECT  7.436 89.952 7.477 90.024 ;
     RECT  7.196 40.176 7.808 88.968 ;
     RECT  7.477 89.952 7.808 90.648 ;
     RECT  7.808 2.148 7.912 127.452 ;
     RECT  7.912 2.418 8.104 127.182 ;
     RECT  8.104 60.816 8.129 63.096 ;
     RECT  8.104 42.528 8.243 47.16 ;
     RECT  8.104 64.416 8.291 67.272 ;
     RECT  8.243 45.312 8.309 47.16 ;
     RECT  8.291 64.416 8.309 67.176 ;
     RECT  8.104 90.624 8.309 90.648 ;
     RECT  8.104 68.352 8.339 81.48 ;
     RECT  8.104 86.736 8.345 87.144 ;
     RECT  8.104 88.368 8.345 88.392 ;
     RECT  8.309 64.416 8.381 67.128 ;
     RECT  8.345 86.736 8.381 86.76 ;
     RECT  8.104 82.464 8.417 83.256 ;
     RECT  8.243 42.528 8.489 44.136 ;
     RECT  8.129 61.008 8.489 63.096 ;
     RECT  8.417 82.464 8.525 82.92 ;
     RECT  8.339 77.28 8.531 81.48 ;
     RECT  8.489 42.72 8.561 42.744 ;
     RECT  8.104 48.192 8.597 59.352 ;
     RECT  8.489 61.008 8.597 61.032 ;
     RECT  8.525 82.512 8.597 82.92 ;
     RECT  8.104 85.488 8.785 85.512 ;
     RECT  8.489 62.112 8.885 63.096 ;
     RECT  8.339 68.352 9.059 76.296 ;
     RECT  8.885 62.208 9.101 63.096 ;
     RECT  9.059 70.512 9.137 76.296 ;
     RECT  8.381 64.992 9.196 67.128 ;
     RECT  8.104 84.432 9.209 84.456 ;
     RECT  8.597 50.832 9.245 59.352 ;
     RECT  9.245 58.704 9.251 59.352 ;
     RECT  8.309 45.312 9.281 47.064 ;
     RECT  9.245 50.832 9.281 56.232 ;
     RECT  9.137 70.512 9.353 76.2 ;
     RECT  8.597 82.512 9.353 82.536 ;
     RECT  9.101 62.208 9.389 62.712 ;
     RECT  8.597 48.192 9.421 49.752 ;
     RECT  9.353 74.208 9.425 76.2 ;
     RECT  9.251 58.704 9.443 59.304 ;
     RECT  9.196 64.992 9.461 66.888 ;
     RECT  9.389 62.208 9.605 62.664 ;
     RECT  9.461 65.424 9.605 66.888 ;
     RECT  9.059 68.352 9.637 69.288 ;
     RECT  9.493 63.792 9.677 63.864 ;
     RECT  9.421 48.096 9.713 49.752 ;
     RECT  9.281 50.976 9.713 56.232 ;
     RECT  8.531 81.168 9.713 81.48 ;
     RECT  9.349 60.528 9.781 60.552 ;
     RECT  9.605 62.208 9.821 62.568 ;
     RECT  9.781 60.288 9.889 60.552 ;
     RECT  9.443 58.704 9.965 59.016 ;
     RECT  9.425 74.544 9.965 76.2 ;
     RECT  9.821 62.304 10.001 62.568 ;
     RECT  9.965 74.64 10.001 76.2 ;
     RECT  9.965 58.752 10.073 59.016 ;
     RECT  10.001 62.544 10.073 62.568 ;
     RECT  9.605 65.424 10.073 66.84 ;
     RECT  9.713 51.648 10.109 56.232 ;
     RECT  9.353 70.512 10.109 71.976 ;
     RECT  9.713 48.192 10.177 49.752 ;
     RECT  10.109 70.8 10.217 71.976 ;
     RECT  9.713 81.168 10.325 81.192 ;
     RECT  10.073 65.424 10.433 66.792 ;
     RECT  10.357 80.928 10.441 80.952 ;
     RECT  10.073 58.944 10.469 59.016 ;
     RECT  9.637 68.016 10.469 69.288 ;
     RECT  9.245 57.312 10.685 57.72 ;
     RECT  10.001 74.928 10.685 76.2 ;
     RECT  10.177 48.192 10.789 49.8 ;
     RECT  10.109 51.696 10.825 56.232 ;
     RECT  10.217 71.088 10.861 71.976 ;
     RECT  10.825 51.696 10.865 56.328 ;
     RECT  10.865 56.304 10.933 56.328 ;
     RECT  10.685 57.312 10.933 57.576 ;
     RECT  10.861 71.088 11.005 72.024 ;
     RECT  9.281 45.408 11.081 47.064 ;
     RECT  10.685 75.648 11.189 76.2 ;
     RECT  10.469 58.944 11.225 58.968 ;
     RECT  11.189 75.648 11.441 75.672 ;
     RECT  10.865 51.696 12.053 55.272 ;
     RECT  10.357 42.72 12.853 42.744 ;
     RECT  8.104 40.56 13.208 40.584 ;
     RECT  12.853 41.904 13.208 42.744 ;
     RECT  8.489 44.112 13.208 44.136 ;
     RECT  11.081 45.408 13.208 46.248 ;
     RECT  10.789 48.096 13.208 49.8 ;
     RECT  12.053 51.696 13.208 55.176 ;
     RECT  10.933 56.304 13.208 57.576 ;
     RECT  9.889 60.288 13.208 61.08 ;
     RECT  9.677 63.792 13.208 63.816 ;
     RECT  10.433 65.424 13.208 66.504 ;
     RECT  10.469 68.112 13.208 69.288 ;
     RECT  11.005 71.088 13.208 72.792 ;
     RECT  8.531 77.28 13.208 79.512 ;
     RECT  12.841 86.064 13.208 86.088 ;
     RECT  13.208 2.148 13.312 127.452 ;
     RECT  13.312 2.418 13.504 127.182 ;
     RECT  13.504 71.088 13.601 72.792 ;
     RECT  13.504 51.696 13.853 55.176 ;
     RECT  13.504 56.304 13.925 57.576 ;
     RECT  13.504 60.288 14.857 61.08 ;
     RECT  13.601 71.088 14.929 72.696 ;
     RECT  13.853 51.696 15.113 54.888 ;
     RECT  13.925 56.88 15.181 57.576 ;
     RECT  15.113 54.336 15.257 54.888 ;
     RECT  15.113 51.696 15.761 53.304 ;
     RECT  13.504 77.28 16.981 79.512 ;
     RECT  16.981 76.464 17.557 79.512 ;
     RECT  14.929 70.368 17.665 72.696 ;
     RECT  13.504 40.56 18.608 40.584 ;
     RECT  13.504 41.904 18.608 42.744 ;
     RECT  13.504 44.112 18.608 44.136 ;
     RECT  13.504 45.408 18.608 46.248 ;
     RECT  13.504 48.096 18.608 49.8 ;
     RECT  15.761 52.176 18.608 53.304 ;
     RECT  15.257 54.336 18.608 54.744 ;
     RECT  15.181 56.88 18.608 58.008 ;
     RECT  14.857 60.288 18.608 61.896 ;
     RECT  13.504 63.792 18.608 63.816 ;
     RECT  13.504 65.424 18.608 66.504 ;
     RECT  13.504 68.112 18.608 69.288 ;
     RECT  17.665 70.272 18.608 72.696 ;
     RECT  17.557 75.936 18.608 79.512 ;
     RECT  18.608 2.148 18.712 127.452 ;
     RECT  18.712 2.418 18.904 127.182 ;
     RECT  20.869 82.944 21.445 82.968 ;
     RECT  18.904 65.424 23.281 66.504 ;
     RECT  18.904 40.56 24.008 40.584 ;
     RECT  18.904 41.904 24.008 42.744 ;
     RECT  18.904 44.112 24.008 44.136 ;
     RECT  18.904 45.408 24.008 46.248 ;
     RECT  18.904 48.096 24.008 49.8 ;
     RECT  18.904 52.176 24.008 53.304 ;
     RECT  18.904 54.336 24.008 54.744 ;
     RECT  18.904 56.88 24.008 58.008 ;
     RECT  18.904 60.288 24.008 61.896 ;
     RECT  18.904 63.792 24.008 63.816 ;
     RECT  23.281 65.136 24.008 66.504 ;
     RECT  18.904 68.112 24.008 72.696 ;
     RECT  18.904 75.936 24.008 79.512 ;
     RECT  21.445 82.128 24.008 82.968 ;
     RECT  24.008 2.148 24.112 127.452 ;
     RECT  24.112 2.418 24.304 127.182 ;
     RECT  24.304 52.176 25.445 53.304 ;
     RECT  24.304 40.56 29.408 40.584 ;
     RECT  24.304 41.904 29.408 42.744 ;
     RECT  24.304 44.112 29.408 44.136 ;
     RECT  24.304 45.408 29.408 46.248 ;
     RECT  24.304 48.096 29.408 49.8 ;
     RECT  25.445 52.704 29.408 53.304 ;
     RECT  24.304 54.336 29.408 54.744 ;
     RECT  24.304 56.88 29.408 58.008 ;
     RECT  24.304 60.288 29.408 61.896 ;
     RECT  24.304 63.792 29.408 63.816 ;
     RECT  24.304 65.136 29.408 66.504 ;
     RECT  24.304 68.112 29.408 72.696 ;
     RECT  24.304 75.936 29.408 79.512 ;
     RECT  24.304 82.128 29.408 82.968 ;
     RECT  29.408 2.148 29.512 127.452 ;
     RECT  29.512 2.418 29.704 127.182 ;
     RECT  29.704 68.112 32.249 72.696 ;
     RECT  29.704 48.096 33.325 49.8 ;
     RECT  33.325 47.664 33.397 49.8 ;
     RECT  29.704 75.936 34.693 79.512 ;
     RECT  29.704 60.288 34.765 61.896 ;
     RECT  29.704 52.704 34.801 53.304 ;
     RECT  29.704 56.88 34.801 58.008 ;
     RECT  29.704 65.136 34.801 66.504 ;
     RECT  29.704 40.56 34.808 40.584 ;
     RECT  29.704 41.904 34.808 42.744 ;
     RECT  29.704 44.112 34.808 44.136 ;
     RECT  29.704 45.408 34.808 46.248 ;
     RECT  33.397 47.664 34.808 50.424 ;
     RECT  34.801 52.704 34.808 53.352 ;
     RECT  29.704 54.336 34.808 54.744 ;
     RECT  34.801 56.592 34.808 58.008 ;
     RECT  34.765 60.288 34.808 61.992 ;
     RECT  29.704 63.792 34.808 63.816 ;
     RECT  34.801 65.136 34.808 66.6 ;
     RECT  32.249 68.112 34.808 72.024 ;
     RECT  34.693 75.408 34.808 79.512 ;
     RECT  29.704 82.128 34.808 82.968 ;
     RECT  34.808 2.148 34.912 127.452 ;
     RECT  34.912 2.418 35.104 127.182 ;
     RECT  35.104 56.592 35.129 58.008 ;
     RECT  35.104 75.264 36.065 79.512 ;
     RECT  35.104 52.704 36.097 53.352 ;
     RECT  35.104 60.288 36.349 62.088 ;
     RECT  36.349 60.288 36.385 62.808 ;
     RECT  35.104 63.792 36.385 63.816 ;
     RECT  35.104 67.824 36.493 68.232 ;
     RECT  35.104 69.216 36.493 72.312 ;
     RECT  35.104 44.112 36.529 44.136 ;
     RECT  35.104 45.408 36.529 46.248 ;
     RECT  35.104 47.568 36.601 50.76 ;
     RECT  36.097 51.792 36.601 53.352 ;
     RECT  35.129 56.88 36.709 58.008 ;
     RECT  36.065 78.624 36.997 79.512 ;
     RECT  36.601 47.568 37.069 53.352 ;
     RECT  35.104 54.336 37.069 54.744 ;
     RECT  36.493 67.824 37.141 72.312 ;
     RECT  36.529 44.112 37.177 46.248 ;
     RECT  37.069 47.568 37.177 54.744 ;
     RECT  37.141 67.584 37.285 72.312 ;
     RECT  36.065 75.264 37.429 77.64 ;
     RECT  36.997 78.624 37.429 79.944 ;
     RECT  36.709 56.88 37.537 58.728 ;
     RECT  37.429 75.264 37.541 79.944 ;
     RECT  37.541 79.248 37.573 79.944 ;
     RECT  35.104 82.128 37.573 82.968 ;
     RECT  36.961 84.336 37.573 84.36 ;
     RECT  35.104 65.136 37.609 66.6 ;
     RECT  37.285 67.584 37.609 73.128 ;
     RECT  37.177 44.112 37.715 54.744 ;
     RECT  37.715 45.84 37.753 54.744 ;
     RECT  37.537 56.256 37.753 58.728 ;
     RECT  36.385 60.288 37.753 63.816 ;
     RECT  37.573 79.248 37.753 80.04 ;
     RECT  37.753 79.248 37.897 80.28 ;
     RECT  37.573 82.128 37.897 84.36 ;
     RECT  35.104 41.904 37.901 42.744 ;
     RECT  37.609 65.136 37.933 73.128 ;
     RECT  37.637 86.064 37.933 86.088 ;
     RECT  37.715 44.112 38.005 44.856 ;
     RECT  35.104 40.56 38.041 40.584 ;
     RECT  37.753 45.84 38.077 58.728 ;
     RECT  37.753 59.856 38.077 63.816 ;
     RECT  37.541 75.264 38.149 78.072 ;
     RECT  38.077 45.84 38.185 63.816 ;
     RECT  37.933 65.04 38.185 73.128 ;
     RECT  37.933 86.064 38.185 86.376 ;
     RECT  38.149 75.024 38.221 78.072 ;
     RECT  38.185 45.84 38.293 73.128 ;
     RECT  38.221 74.448 38.293 78.072 ;
     RECT  38.041 40.08 38.333 40.584 ;
     RECT  38.333 40.56 38.365 40.584 ;
     RECT  37.901 41.904 38.365 41.928 ;
     RECT  37.897 79.248 38.401 84.36 ;
     RECT  38.185 85.44 38.401 86.376 ;
     RECT  38.401 79.248 38.509 86.376 ;
     RECT  38.473 91.776 38.557 91.8 ;
     RECT  38.293 45.84 38.581 78.072 ;
     RECT  38.509 79.248 38.581 86.664 ;
     RECT  38.581 45.84 39.013 86.664 ;
     RECT  38.005 43.296 39.121 44.856 ;
     RECT  39.013 45.84 39.121 86.808 ;
     RECT  38.365 40.56 39.161 41.928 ;
     RECT  39.121 43.296 39.193 86.808 ;
     RECT  38.041 87.936 39.193 87.96 ;
     RECT  38.761 90.576 39.197 90.6 ;
     RECT  39.161 40.992 39.517 41.928 ;
     RECT  39.193 43.296 39.517 87.96 ;
     RECT  39.265 39.504 39.589 39.528 ;
     RECT  39.589 38.976 39.625 39.528 ;
     RECT  39.517 40.992 39.697 87.96 ;
     RECT  39.697 40.992 39.769 88.68 ;
     RECT  39.625 38.976 39.829 39.576 ;
     RECT  39.829 38.16 39.877 39.576 ;
     RECT  39.877 38.16 40.208 39.768 ;
     RECT  39.769 40.992 40.208 88.776 ;
     RECT  40.021 90.288 40.208 90.312 ;
     RECT  40.208 2.148 40.312 127.452 ;
     RECT  40.312 2.418 40.504 127.182 ;
     RECT  40.504 58.512 40.529 62.184 ;
     RECT  40.504 77.52 40.565 89.448 ;
     RECT  40.529 58.704 41.569 62.184 ;
     RECT  40.504 63.216 41.569 64.488 ;
     RECT  40.504 65.52 41.569 76.488 ;
     RECT  41.569 58.704 41.605 76.488 ;
     RECT  40.504 39.216 42.109 57.336 ;
     RECT  41.605 58.416 42.109 76.488 ;
     RECT  40.565 77.52 42.109 79.656 ;
     RECT  40.565 80.688 42.109 89.448 ;
     RECT  42.109 39.216 42.145 57.384 ;
     RECT  42.109 58.416 42.145 89.448 ;
     RECT  42.145 39.216 42.181 89.448 ;
     RECT  42.181 39.12 42.973 89.448 ;
     RECT  42.973 39.12 43.085 90.072 ;
     RECT  43.085 39.12 43.164 89.832 ;
     RECT  43.164 89.808 43.193 89.832 ;
    LAYER M5 ;
     RECT  2.4 2.137 2.52 2.151 ;
     RECT  7.8 2.137 7.92 2.151 ;
     RECT  13.2 2.137 13.32 2.151 ;
     RECT  18.6 2.137 18.72 2.151 ;
     RECT  24 2.137 24.12 2.151 ;
     RECT  29.4 2.137 29.52 2.151 ;
     RECT  34.8 2.137 34.92 2.151 ;
     RECT  40.2 2.137 40.32 2.151 ;
     RECT  40.2 2.151 40.512 38.149 ;
     RECT  5.52 39.301 5.544 40.165 ;
     RECT  5.04 40.165 5.544 40.405 ;
     RECT  7.8 2.151 8.112 40.549 ;
     RECT  7.8 40.549 8.76 40.741 ;
     RECT  39.84 38.149 40.512 41.075 ;
     RECT  4.416 40.405 5.544 41.557 ;
     RECT  13.2 2.151 13.512 41.893 ;
     RECT  4.32 41.557 5.544 42.085 ;
     RECT  4.32 42.085 5.592 42.565 ;
     RECT  7.008 40.741 8.76 42.565 ;
     RECT  2.4 2.151 2.712 42.709 ;
     RECT  4.32 42.565 8.76 42.709 ;
     RECT  0.144 44.149 0.168 44.435 ;
     RECT  43.008 45.013 43.032 45.203 ;
     RECT  37.68 45.397 37.704 48.181 ;
     RECT  0.144 48.181 0.168 50.053 ;
     RECT  0.144 50.053 0.264 50.915 ;
     RECT  0.24 50.915 0.264 50.963 ;
     RECT  37.68 48.181 38.52 51.061 ;
     RECT  2.4 42.709 8.76 51.781 ;
     RECT  2.304 51.781 8.76 51.923 ;
     RECT  37.68 51.061 38.808 52.117 ;
     RECT  37.68 52.117 39.192 52.259 ;
     RECT  43.008 52.549 43.032 52.739 ;
     RECT  2.4 51.923 8.76 53.029 ;
     RECT  2.4 53.029 9.192 53.125 ;
     RECT  40.2 41.075 40.512 58.645 ;
     RECT  37.68 52.259 38.52 58.789 ;
     RECT  39.552 58.645 40.512 58.789 ;
     RECT  37.68 58.789 40.512 59.123 ;
     RECT  2.4 53.125 9.384 59.269 ;
     RECT  10.368 42.709 10.392 59.269 ;
     RECT  0.144 61.141 0.168 61.427 ;
     RECT  43.008 61.717 43.032 62.003 ;
     RECT  37.68 59.123 38.52 62.341 ;
     RECT  37.68 62.341 39 62.819 ;
     RECT  0.144 64.117 0.168 64.403 ;
     RECT  2.4 59.269 10.392 65.027 ;
     RECT  24 2.151 24.312 65.413 ;
     RECT  37.68 62.819 38.52 66.133 ;
     RECT  37.68 66.133 38.664 66.373 ;
     RECT  40.2 59.123 40.512 66.373 ;
     RECT  37.68 66.373 40.512 66.563 ;
     RECT  2.4 65.027 9.384 68.101 ;
     RECT  10.368 65.027 10.392 68.101 ;
     RECT  0.24 67.381 0.264 68.243 ;
     RECT  37.68 66.563 38.808 68.243 ;
     RECT  2.4 68.101 10.392 68.483 ;
     RECT  0.192 69.493 0.216 70.067 ;
     RECT  0.144 70.309 0.168 70.499 ;
     RECT  37.68 68.243 38.52 70.693 ;
     RECT  40.2 66.563 40.512 70.693 ;
     RECT  2.4 68.483 9.384 70.741 ;
     RECT  10.368 68.483 10.392 70.741 ;
     RECT  37.68 70.693 40.512 70.883 ;
     RECT  2.4 70.741 10.392 70.931 ;
     RECT  37.68 70.883 39 70.931 ;
     RECT  37.68 70.931 38.52 73.765 ;
     RECT  40.2 70.883 40.512 73.765 ;
     RECT  37.68 73.765 40.512 74.291 ;
     RECT  0.144 73.957 0.168 74.341 ;
     RECT  0.144 74.341 0.216 74.531 ;
     RECT  0.144 74.531 0.168 75.731 ;
     RECT  2.4 70.931 9.384 77.507 ;
     RECT  37.68 74.291 38.52 77.989 ;
     RECT  37.68 77.989 38.808 78.227 ;
     RECT  2.4 77.507 9.288 78.659 ;
     RECT  0.144 77.077 0.168 79.475 ;
     RECT  10.368 70.931 10.392 80.963 ;
     RECT  2.4 78.659 8.76 82.115 ;
     RECT  2.4 82.115 5.592 82.403 ;
     RECT  6.576 82.115 8.76 83.267 ;
     RECT  7.584 83.267 8.76 83.603 ;
     RECT  0.144 81.733 0.168 83.651 ;
     RECT  43.008 83.557 43.032 83.747 ;
     RECT  2.4 82.403 5.4 84.323 ;
     RECT  3.696 84.323 5.4 84.467 ;
     RECT  4.848 84.467 5.4 84.901 ;
     RECT  6.576 83.267 6.6 84.901 ;
     RECT  3.696 84.467 3.72 84.995 ;
     RECT  4.848 84.901 6.6 85.043 ;
     RECT  7.8 83.603 8.76 85.523 ;
     RECT  12.864 41.893 13.512 86.099 ;
     RECT  37.68 78.227 38.52 86.099 ;
     RECT  4.848 85.043 5.4 86.341 ;
     RECT  6.576 85.043 6.6 86.341 ;
     RECT  4.848 86.341 6.6 86.725 ;
     RECT  7.8 85.523 8.112 86.725 ;
     RECT  4.848 86.725 8.112 87.109 ;
     RECT  0.144 86.197 0.168 87.203 ;
     RECT  4.128 87.109 8.112 87.827 ;
     RECT  4.128 87.827 6.6 88.403 ;
     RECT  4.512 88.403 6.6 88.451 ;
     RECT  4.848 88.451 6.6 88.979 ;
     RECT  2.4 84.323 2.712 89.461 ;
     RECT  5.232 88.979 5.688 89.555 ;
     RECT  2.4 89.461 2.808 89.845 ;
     RECT  7.8 87.827 8.112 89.989 ;
     RECT  0.144 89.701 0.168 90.467 ;
     RECT  7.488 89.989 8.112 90.659 ;
     RECT  5.28 89.555 5.688 91.235 ;
     RECT  2.4 89.845 3.432 91.811 ;
     RECT  5.28 91.235 5.304 91.811 ;
     RECT  38.496 86.099 38.52 91.811 ;
     RECT  2.4 91.811 2.712 127.449 ;
     RECT  7.8 90.659 8.112 127.449 ;
     RECT  13.2 86.099 13.512 127.449 ;
     RECT  18.6 2.151 18.912 127.449 ;
     RECT  23.184 65.413 24.312 127.449 ;
     RECT  29.4 2.151 29.712 127.449 ;
     RECT  34.8 2.151 35.112 127.449 ;
     RECT  40.2 74.291 40.512 127.449 ;
     RECT  2.4 127.449 2.52 127.463 ;
     RECT  7.8 127.449 7.92 127.463 ;
     RECT  13.2 127.449 13.32 127.463 ;
     RECT  18.6 127.449 18.72 127.463 ;
     RECT  23.184 127.449 24.12 127.463 ;
     RECT  29.4 127.449 29.52 127.463 ;
     RECT  34.8 127.449 34.92 127.463 ;
     RECT  40.2 127.449 40.32 127.463 ;
     RECT  5.544 40.741 7.008 42.085 ;
     RECT  5.592 42.085 7.008 42.565 ;
     RECT  38.808 51.061 40.2 52.117 ;
     RECT  39.192 52.117 40.2 52.259 ;
     RECT  9.192 53.029 10.368 53.125 ;
     RECT  9.384 53.125 10.368 59.269 ;
     RECT  38.52 58.645 39.552 58.789 ;
     RECT  39 62.341 40.2 62.819 ;
     RECT  9.384 65.027 10.368 68.101 ;
     RECT  38.808 66.563 40.2 68.243 ;
     RECT  9.384 68.483 10.368 70.741 ;
     RECT  39 70.883 40.2 70.931 ;
     RECT  9.384 70.931 10.368 77.507 ;
     RECT  0.144 75.731 0.168 77.077 ;
     RECT  9.288 77.507 10.368 78.659 ;
     RECT  38.808 77.989 40.2 78.227 ;
     RECT  5.592 82.115 6.576 82.403 ;
     RECT  5.4 82.403 6.576 84.901 ;
     RECT  6.6 83.267 7.584 83.603 ;
     RECT  6.6 83.603 7.8 86.725 ;
     RECT  2.712 84.323 3.696 84.995 ;
     RECT  3.72 84.467 4.848 84.995 ;
     RECT  5.4 85.043 6.576 86.341 ;
     RECT  2.712 87.109 4.128 88.403 ;
     RECT  6.6 87.827 7.8 88.979 ;
     RECT  2.712 88.403 4.512 88.451 ;
     RECT  2.712 88.451 4.848 88.979 ;
     RECT  2.712 88.979 3.432 89.461 ;
     RECT  7.488 88.979 7.8 89.989 ;
     RECT  2.808 89.461 3.432 89.845 ;
  END
END ot_hgi_coll_control256_capture
END LIBRARY
